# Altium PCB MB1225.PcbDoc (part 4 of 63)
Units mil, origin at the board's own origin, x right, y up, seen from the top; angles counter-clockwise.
Board outline 5000 x 3464.56 mil, 6 copper layers (TOP, L2_GND, L3_VCC, L4_SIG, L5_GND, BOTTOM), stack 62.2 mil thick; 452 components, 378 nets, 1968 pads, 949 vias.

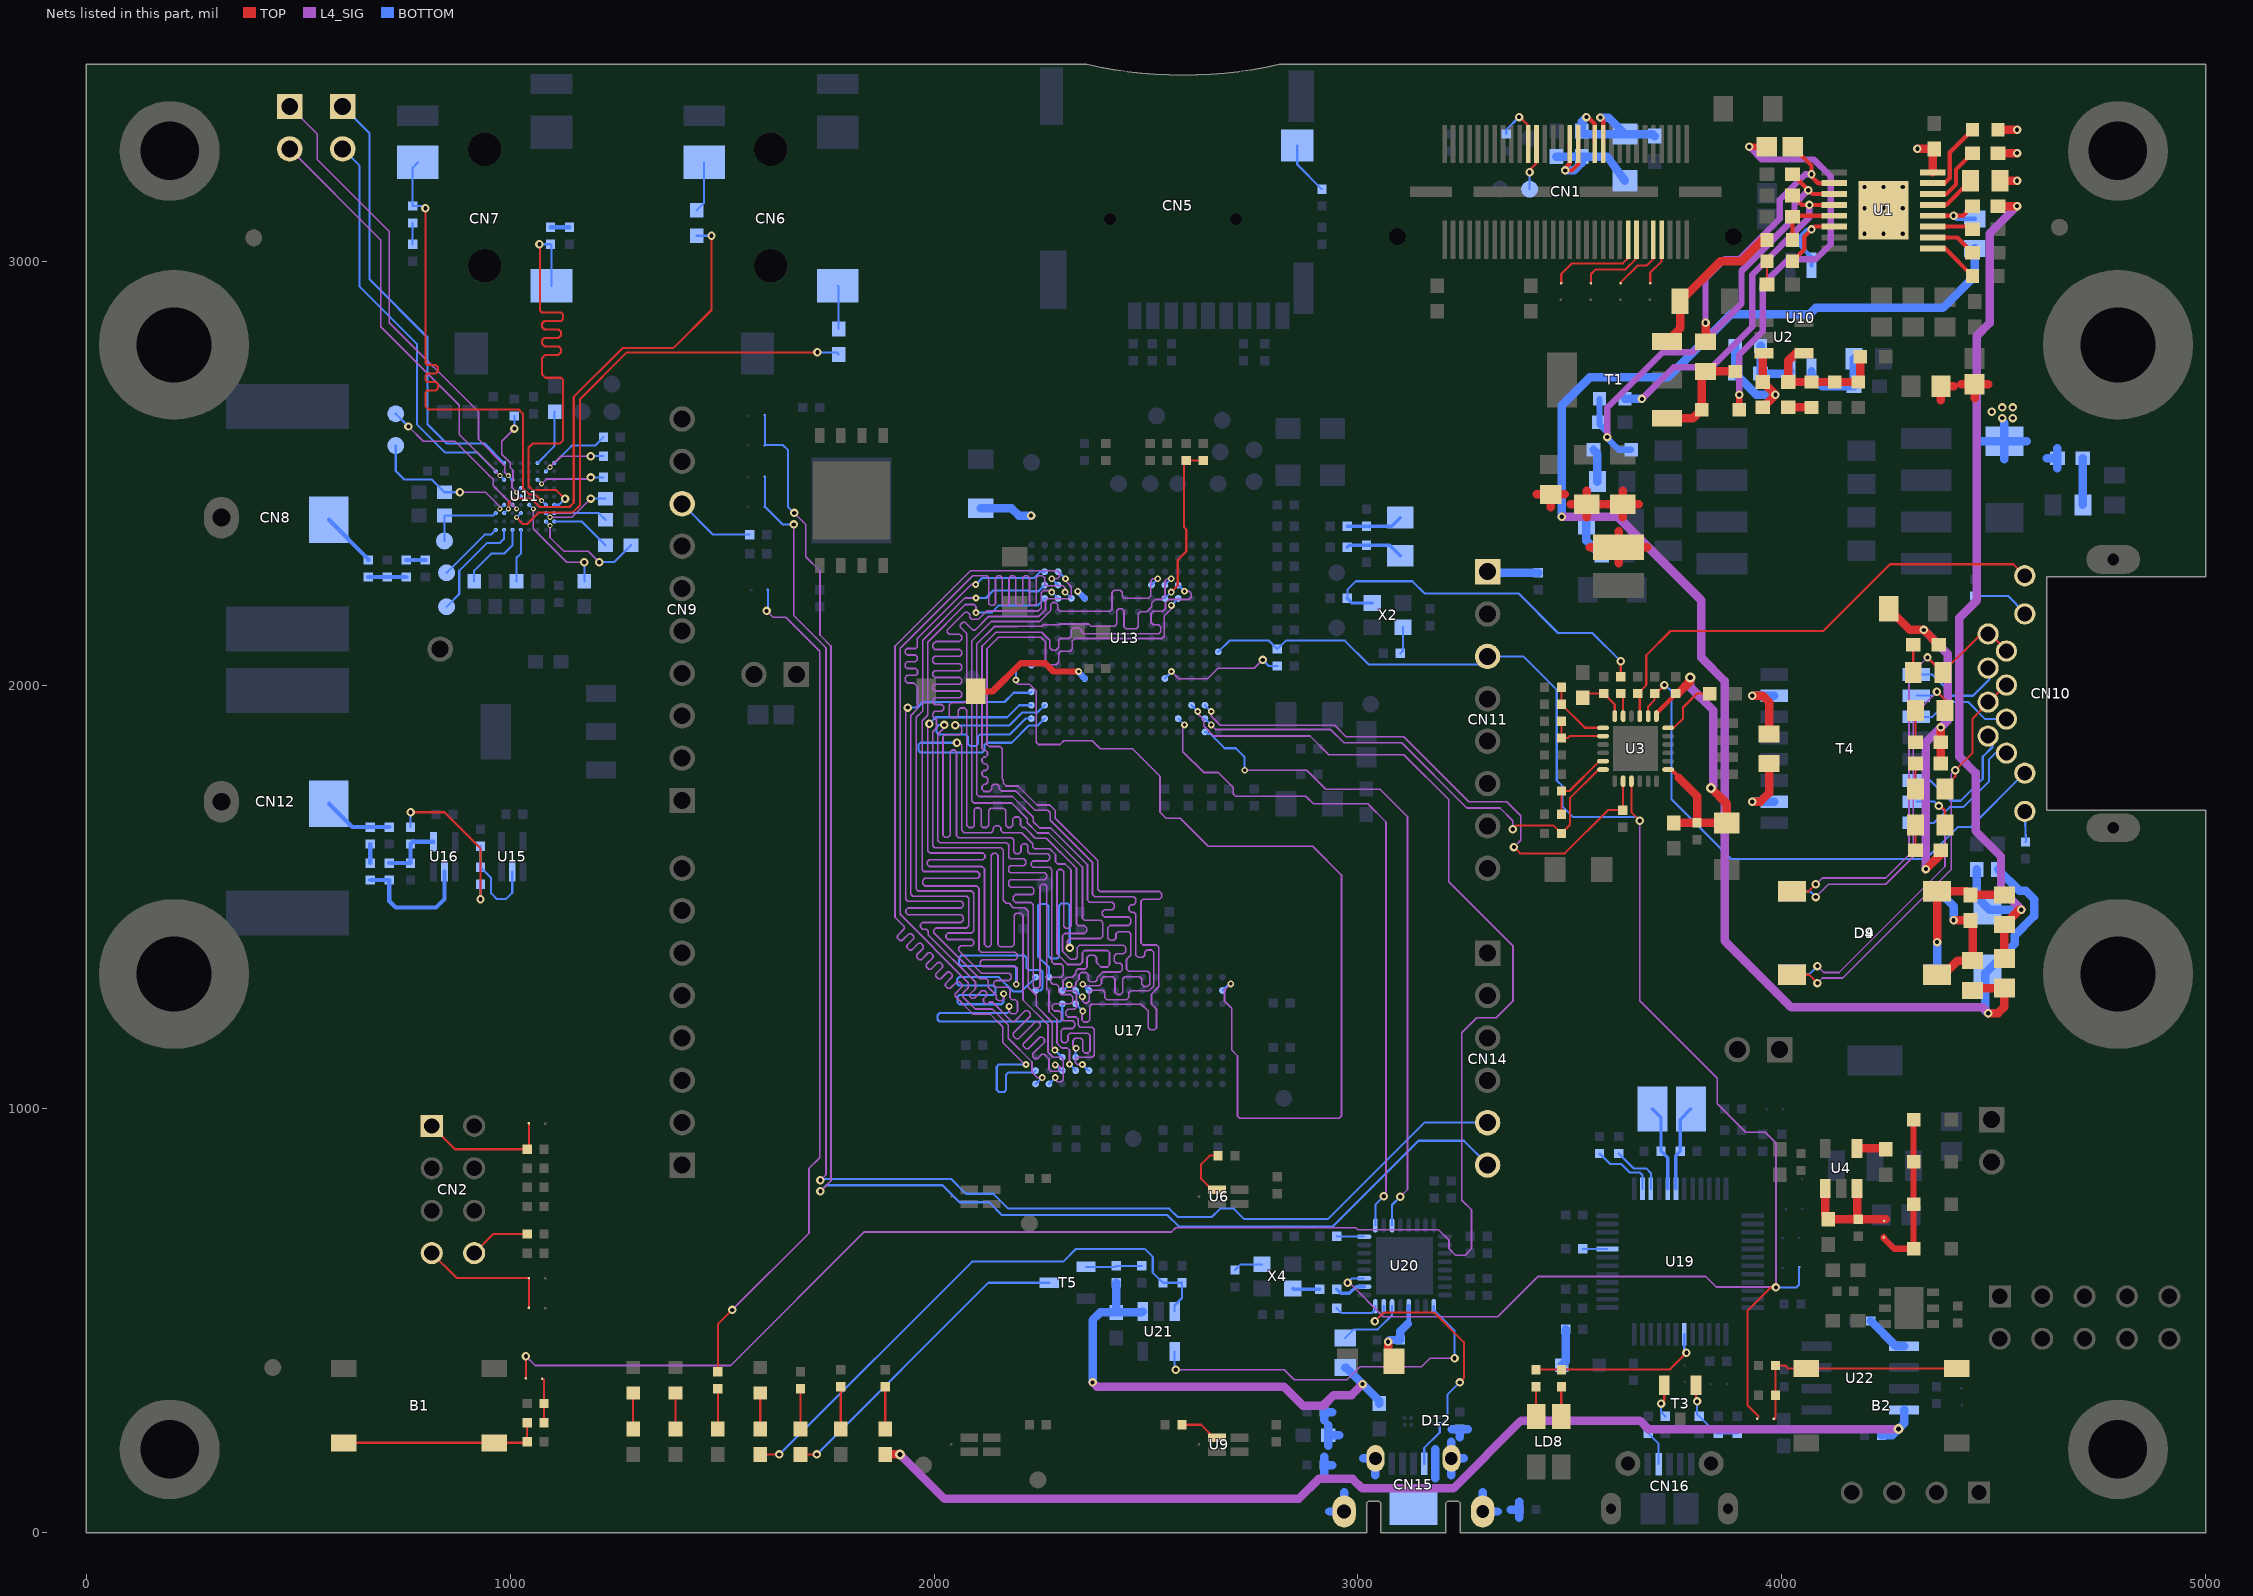
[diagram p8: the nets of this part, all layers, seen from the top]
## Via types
v1: diameter 20, hole 10, TOP to BOTTOM, 354 vias
v2: diameter 24, hole 12, TOP to BOTTOM, 349 vias
v3: diameter 16, hole 8, TOP to BOTTOM, 219 vias
v4: diameter 12, hole 6, TOP to BOTTOM, 27 vias

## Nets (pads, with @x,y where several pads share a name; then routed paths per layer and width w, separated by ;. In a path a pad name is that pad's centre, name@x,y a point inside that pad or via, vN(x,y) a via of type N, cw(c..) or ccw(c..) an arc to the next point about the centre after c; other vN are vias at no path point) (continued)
FMC_D15: U13.K15 U17.R2 | length 2329.2
  L4_SIG w4: v3(2193,2012) 2193,2007 2198,2002 2225,2002 2241,1986 2241,1865 2246,1860 2297,1860 2306,1869 2373,1869 2392,1850 2467.98,1850 2533,1784.98 2533,1700.02 2547.02,1686 2581,1686 2647,1620 2893,1620 2961,1552 2961,983 2956,978 2721,978 2716,983 2716,1125 2702,1139 2702,1238 2685,1255 2685,1280 v3(2700,1295)
  BOTTOM w5: v3(2193,2012) 2193,2035 2205.01,2047.01 U13.K15@2229.53,2047.01 ; U17.R2@2680.47,1279.49 2695.98,1295 v3(2700,1295)
FMC_D16: U13.P14 U17.E8 | length 2227.8
  L4_SIG w4: v1(2054,1864) 2060,1864 2065,1859 2065,1658 2071,1652 2135,1652 2140,1657 2140,1663 2145,1668 2153,1668 2158,1663 2158,1657 2163,1652 2207,1652 2233,1626 2233,1618 2237,1614 2273,1614 2286.5,1600.5 2286.5,1583.5 2292,1578 2309,1578 2323,1564 2323,1430.98 2318.02,1426 2310.98,1426 2306,1430.98 2306,1560.31 2301.31,1565 2294.69,1565 2290,1560.31 2290,1366 2315,1341 2345,1341 2350,1346 2350,1369 2355,1374 2409,1374 2414,1369 2414,1340 2409,1335 2394,1335 2383,1346 2383,1358.02 2378.02,1363 2366,1363 2361,1358 2361,1335 2356,1330 2339,1330 2334,1325 2334,1319 2326,1311 2314,1311 2304,1301 2304,1284 2309,1279 2331,1279 2336,1274 2336,1240 2331,1235 2316,1235 2311,1230 2311,1222 2316,1217 2335,1217 2340,1212 2340,1198 2345,1193 2373,1193 2378,1188 2378,1127 2373,1122 2338,1122 2333,1117 2333,1110 2338,1105 v3(2350,1105)
  BOTTOM w5: v1(2054,1864) 1968,1864 1963,1859 1963,1846 1968,1841 2114,1841 2119,1846 2119,1859 2124,1864 2183,1864 2224.1,1905.1 2245.1,1905.1 U13.P14@2261.02,1921.02 ; v3(2350,1105) 2364.49,1090.51 U17.E8@2365.51,1090.51
FMC_D17: U13.N14 U17.D7 | length 2223.5
  L4_SIG w4: v1(2050,1905) 2060,1905 2065,1900 2065,1888 2060,1883 2026,1883 2021,1878 2021,1645.98 2025.98,1641 2033.02,1641 2038,1645.98 2038,1842.61 2042.39,1847 2048.61,1847 2053,1842.61 2053,1645 2058,1640 2183,1640 2188,1635 2188,1607 2193,1602 2200,1602 2205,1607 2205,1621.31 2209.69,1626 2216,1626 2221,1621 2221,1607 2226,1602 2268.02,1602 2273,1597.02 2273,1589.98 2268.02,1585 2233.39,1585 2229,1580.61 2229,1574.39 2233.39,1570 2273,1570 2278,1565 2278,1347 2283,1342 2300,1342 2305,1337 2305,1316 2300,1311 2279.98,1311 2275,1306.02 2275,1298.98 2279.98,1294 2289,1294 2294,1289 2294,1276 2300,1270 2322,1270 2327,1265 2327,1253 2322,1248 2283.98,1248 2279,1243.02 2279,1235.98 2283.98,1231 2295,1231 2300,1226 2300,1213 2305,1208 2327,1208 2332,1203 2332,1195 2327,1190 2305,1190 2300,1185 2300,1161 2305,1156 2311,1156 2316,1161 2316,1174 2321,1179 2363,1179 2368,1174 2368,1137 2363,1132 2356,1132 2351,1137 2351,1162.31 2346.31,1167 2333,1167 2328,1162 2328,1148.01 2333,1143.01 v3(2335,1143.01)
  BOTTOM w5: v1(2050,1905) 2178,1905 2208.52,1935.52 2244.02,1935.52 U13.N14@2261.02,1952.52 ; U17.D7@2334.02,1122.01 2334.02,1142.03 v3(2335,1143.01)
FMC_D18: U13.P15 U17.D8 | length 2224.4
  L4_SIG w4: v1(2024,1906) 2024,1899 2009,1884 2009,1633 2014,1628 2171,1628 2176,1623 2176,1594 2180,1590 2211.31,1590 2216,1585.31 2216,1578.69 2211.31,1574 2180,1574 2176,1570 2176,1561 2180,1557 2261.31,1557 2266,1552.31 2266,1545.69 2261.31,1541 2180,1541 2176,1537 2176,1528 2181,1523 2231,1523 2235,1519 2235,1509 2232,1506 2192,1506 2187,1501 2187,1492 2192,1487 2229,1487 2234,1482 2234,1289.69 2238.69,1285 2245.31,1285 2250,1289.69 2250,1525.31 2254.69,1530 2261.31,1530 2266,1525.31 2266,1284 2271,1279 2271,1230 2290,1211 2290,1155 2301,1144 2314.41,1144 2319.41,1139 v3(2319.41,1105.61)
  BOTTOM w5: v1(2024,1906) 2011,1906 2006,1901 2006,1888 2011,1883 2075,1883 2080,1878 2080,1861 2085,1856 2098,1856 2103,1861 2103,1878 2108,1883 2178,1883 2216.02,1921.02 U13.P15@2229.53,1921.02 ; v3(2319.41,1105.61) 2334.02,1091 U17.D8@2334.02,1090.51
FMC_D19: U13.N15 U17.B9 | length 2255.1
  L4_SIG w4: v1(1989,1909) 1985,1905 1985,1609 1990,1604 2115.31,1604 2120,1599.31 2120,1592.69 2115.31,1588 1988.69,1588 1984,1583.31 1984,1576.69 1988.69,1572 2114,1572 2119,1567 2119,1388 2124,1383 2130,1383 2135,1388 2135,1598.31 2139.69,1603 2146.31,1603 2151,1598.31 2151,1388 2156,1383 2184,1383 2189,1388 2189,1457 2194,1462 2205,1462 2210,1457 2210,1257 2269,1198 2269,1134 2281,1122 2300,1122 2305,1117 2305,1069 2300,1064 2291,1064 2286,1069 v3(2286,1074)
  BOTTOM w5: v1(1989,1909) 2004,1924 2172.48,1924 2201,1952.52 U13.N15@2229.53,1952.52 ; U17.B9@2271.02,1059.02 v3(2286,1074)
FMC_D20: U13.M15 U17.C8 | length 2245.9
  L4_SIG w4: v1(1938,1947) 1933,1942 1933,1495 1938,1490 2064.31,1490 2069,1485.31 2069,1478.69 2064.31,1474 1938.69,1474 1934,1469.31 1934,1462.69 1938.69,1458 2064,1458 2069,1453 2069,1445 2064,1440 1972.69,1440 1968,1435.31 1968,1429 1973,1424 1981.5,1424 1986.5,1419 1986.5,1410.5 2098,1299 2098,1284.32 2084.82,1271.14 2084.82,1265.18 2089.02,1260.98 2094.98,1260.98 2112.63,1278.63 2119.37,1278.63 2124.13,1273.87 2124.13,1267.13 2116.48,1259.48 2116.48,1253.09 2121.02,1248.56 2127.42,1248.56 2131.43,1252.57 2137.41,1252.57 2183.99,1205.99 2188.99,1205.99 2214.46,1231.46 2221.54,1231.46 2226.96,1226.04 2226.96,1218.96 2187,1179 2187,1171.98 2193.38,1165.6 2199.04,1165.6 2239.4,1205.96 2246.04,1205.96 2250.72,1201.28 2250.72,1194.64 2210.36,1154.28 2210.36,1148.62 2216.75,1142.23 2222.41,1142.23 2249.27,1169.09 2255.91,1169.09 2260.59,1164.41 2260.59,1157.77 2233.16,1130.34 2233.16,1123.84 2237.75,1119.25 2244.25,1119.25 2254,1129 2260,1129 2271,1118 2271,1093.39 2275.39,1089 2292.22,1089 2297,1093.78 2297,1099 2292,1104 v3(2286,1104)
  BOTTOM w5: v1(1938,1947) 1961,1947 1974,1960 2166.04,1960 2188.04,1982 2227.51,1982 U13.M15@2229.53,1984.02 ; v3(2286,1104) 2299.49,1090.51 U17.C8@2302.52,1090.51
FMC_D21: U13.E12 U17.A9 | length 2242.8
  L4_SIG w4: v3(2255,1074) 2244,1074 2231,1087 2231,1111 2175,1167 2175,1198 2138,1235 2136.98,1236 2097,1236 2068,1265 2068,1273 2081,1286 2081,1298 1920,1459 1920,2087 2091,2258 2124.01,2258 2129.01,2253 2129.01,2192 2133.01,2188 2141.01,2188 2145.01,2192 2145.01,2253 2150.01,2258 2156.01,2258 2161.01,2253 2161.01,2192 2165.01,2188 2173.01,2188 2177.01,2192 2177.01,2253 2182.01,2258 2188.01,2258 2193.01,2253 2193.01,2192 2197.01,2188 2205.01,2188 2209.01,2192 2209.01,2253 2214.01,2258 2220.01,2258 2225.01,2253 2225.01,2192 2229.01,2188 2237.01,2188 2241.01,2192 2241.01,2253 2246.01,2258 2256,2258 2261,2253 2261,2239 2266,2234 2304.17,2234 2309.17,2229 v3(2309.17,2219.34)
  BOTTOM w5: U17.A9@2239.53,1059.02 2254.51,1074 v3(2255,1074) ; v3(2309.17,2219.34) U13.E12@2324.02,2204.49
FMC_D22: U13.E13 U17.C7 | length 2228.9
  L4_SIG w4: v3(2277.67,2219.34) 2274.01,2223 2258,2223 2253,2218 2253,2182 2246,2175 2125,2175 2105,2155 2089,2155 2084,2160 2084,2167 2079,2172 2073,2172 2031,2130 2031,2125 2036,2120 2060.02,2120 2065,2115.02 2065,2107.98 2060.02,2103 2004,2103 1997,2096 1997,2088.98 2002,2083.98 2060.31,2083.98 2065,2079.29 2065,2072.67 2060.31,2067.98 2002,2067.98 1997,2062.98 1997,2055 2002,2050 2060.31,2050 2065,2045.31 2065,2038.69 2060.31,2034 2002,2034 1997,2029 1997,2023 2002,2018 2060.31,2018 2065,2013.31 2065,2006.69 2060.31,2002 2002,2002 1997,1997 1997,1991 2002,1986 2060.31,1986 2065,1981.31 2065,1974.69 2060.31,1970 2002,1970 1997,1965 1997,1959 2002,1954 2018.31,1954 2023,1949.31 2023,1942.69 2018.31,1938 2002,1938 1997,1933 1997,1926 2006,1917 2006,1899 1997,1890 1997,1621 2002,1616 2158,1616 2163,1611 2163,1492 2170,1485 2177,1485 2187,1475 2213.85,1475 2222,1466.85 2222,1287 2241,1268 2241,1243 2279,1205 2279,1145 v3(2285,1139)
  BOTTOM w4: v3(2277.67,2219.34) U13.E13@2292.52,2204.49
  BOTTOM w5: v3(2285,1139) 2301.99,1122.01 U17.C7@2302.52,1122.01
FMC_D23: U13.D13 U17.A8 | length 2238.4
  L4_SIG w4: v3(2217,1105) 2214,1105 2162.04,1156.96 2162.04,1193.96 2132,1224 2092,1224 2049.74,1266.26 2049.74,1271.92 2066.08,1288.26 2066.08,1293.92 2059.7,1300.3 2054.04,1300.3 2038.2,1284.46 2032.54,1284.46 2026.88,1290.12 2026.88,1295.78 2042.72,1311.62 2042.72,1317.28 2037.06,1322.94 2031.4,1322.94 2015.56,1307.1 2009.9,1307.1 2004.24,1312.76 2004.24,1318.42 2020.08,1334.26 2020.08,1339.92 2014.42,1345.58 2008.76,1345.58 1992.92,1329.74 1987.26,1329.74 1981.6,1335.4 1981.6,1341.06 1997.44,1356.9 1997.44,1362.56 1991.78,1368.22 1986.12,1368.22 1970.28,1352.38 1964.62,1352.38 1958.96,1358.04 1958.96,1363.7 1974.8,1379.54 1974.8,1385.2 1969.14,1390.86 1963.48,1390.86 1947.64,1375.02 1941.98,1375.02 1936.32,1380.68 1936.32,1386.34 1952.16,1402.18 1952.16,1407.84 1946.5,1413.5 1940.84,1413.5 1925,1397.66 1919.34,1397.66 1913.68,1403.32 1913.68,1408.98 1929.52,1424.82 1929.52,1430.48 1908,1452 1908,2092 2086,2270 2291,2270 2296,2265 2296,2255.83 2291,2250.83 v3(2277.67,2250.83)
  BOTTOM w5: v3(2217,1105) 2153,1105 2148,1100 2148,1045 2153,1040 2165,1040 2170,1045 2170,1081 2175,1086 2235.02,1086 U17.A8@2239.53,1090.51 ; v3(2277.67,2250.83) U13.D13@2292.52,2235.98
FMC_D24: U13.E14 U17.A2 | length 2269.2
  L4_SIG w4: v3(2099,2171) 2099,2186 2095,2190 2074,2190 1985,2101 1985,1929.05 1972,1916.05 1972,1564 1976,1560 2103,1560 2107,1556 2107,1548 2103,1544 1978,1544 1973,1539 1973,1531 1978,1526 2101,1526 2106,1521 2106,1375 2111,1370 2191,1370 2196,1365 2196,1356 2192,1352 2113.69,1352 2109,1347.31 2109,1340.69 2113.69,1336 2192,1336 2196,1332 2196,1296 v3(2194,1294)
  BOTTOM w5: v3(2099,2171) 2136,2171 2153,2188 2244.53,2188 U13.E14@2261.02,2204.49 ; v3(2194,1294) 2194,1332 2189,1337 2064,1337 2059,1342 2059,1357 2064,1362 2213,1362 2218,1357 2218,1333 2223,1328 2251,1328 2256,1323 2256,1284.49 2251,1279.49 U17.A2@2239.53,1279.49
FMC_D25: U13.D14 U17.C3 | length 2242.8
  L4_SIG w4: v3(2099,2205.5) 2072.5,2205.5 1973,2106 1973,1939 1958,1924 1958,1519 1963,1514 2089,1514 2094,1509 2094,1420 2089,1415 2032.39,1415 2028,1410.61 2028,1404.39 2032.39,1400 2089.61,1400 2094,1395.61 2094,1389.39 2089.61,1385 2063,1385 2058,1380 2058,1374 2111.83,1320.17 2177,1320.17 2182,1315.17 2182,1308 2177,1303 2145.69,1303 2141,1298.31 2141,1291.69 2145.69,1287 2174,1287 2179,1282 2179,1263 2184,1258 2192,1258 2197,1253 2197,1230 2192,1225 2182,1225 2177,1230 v3(2177,1242)
  BOTTOM w5: v3(2099,2205.5) 2122.5,2205.5 2140,2223 2222,2223 2223.52,2221.48 2246.52,2221.48 U13.D14@2261.02,2235.98 ; v3(2177,1242) 2177,1230.69 2172.31,1226 2013,1226 2008,1221 2008,1211 2013,1206 2297.52,1206 2302.52,1211 U17.C3@2302.52,1247.99
FMC_D26: U13.C14 U17.A1 | length 2247.2
  L4_SIG w4: v3(2098.61,2237.39) 2087.39,2237.39 1960,2110 1960,2090 1956.5,2086.5 1936.54,2086.5 1932,2081.96 1932,2075.54 1936.54,2071 1956,2071 1960,2067 1960,2059 1956,2055 1936,2055 1932,2051 1932,2043 1936,2039 1957,2039 1961,2035 1961,2027 1957,2023 1937,2023 1932,2018 1932,2010 1937,2005 1952,2005 1961,1996 1961,1944 1945,1928 1945,1507 1950,1502 2077,1502 2082,1497 2082,1432 2077,1427 2003.69,1427 1999,1422.31 1999,1416 2107.51,1307.49 2123.51,1307.49 2128,1303 2128,1287 2147,1268 2147,1259.98 2151.98,1255 2160,1255 2165,1260 2165,1271 v3(2164,1272)
  BOTTOM w5: v3(2098.61,2237.39) 2114.22,2253 2223.5,2253 2236.02,2252.98 2250.52,2267.48 U13.C14@2261.02,2267.48 ; v3(2164,1272) 2164,1252 2159,1247 2060,1247 2055,1252 2055,1264 2060,1269 2140,1269 2145,1274 2145,1286 2140,1291 2059,1291 2054,1296 2054,1305.98 2059,1310.98 2153.02,1310.98 2187,1277 2205.55,1277 U17.A1@2239.53,1310.98
FMC_D27: U13.C13 U17.C2 | length 2224.9
  L4_SIG w4: v3(2310,2251) 2310,2246 2324,2232 2324,2212 2316,2204 2268,2204 2263,2199 2263,2178 2247,2162 2129,2162 2097,2130 2091.34,2130 2073,2148.34 2067.34,2148.34 2061.68,2142.68 2061.68,2137.02 2077,2121.7 2077,1963 2072,1958 2041,1958 2036,1953 2036,1928 2041,1923 2052,1923 2057,1928 2057,1941 2062,1946 2072,1946 2077,1941 2077,1669 2082,1664 2091,1664 2095,1668 2095,1706 2099,1710 2107,1710 2111,1706 2111,1668 2115,1664 2124,1664 2129,1669 2129,1704.68 2134,1709.68 2164,1709.68 2169,1704.68 2169,1669 2174,1664 2181,1664 2186,1669 2186,1684 2191,1689 2199,1689 2204,1684 2204,1669 2209,1664 2214,1664 2239,1639 2265,1639 2336,1568 2336,1437 2341,1432 2355,1432 2360,1427 2360,1419 2355,1414 2308,1414 2303,1409 2303,1372 2322,1353 2333,1353 2338,1358 2338,1381 2343,1386 2447,1386 2452,1381 2452,1371 2447,1366 2430,1366 2425,1361 2425,1349 2430,1344 2439,1344 2444,1339 2444,1328 2439,1323 2398,1323 2385,1310 2385,1305 2380,1300 2368,1300 2364,1304 2364,1317 2359,1322 2347,1322 2342,1317 2342,1306 2335,1299 2335,1291.81 2330.19,1287 2323.4,1287 2318.59,1291.81 v3(2318.59,1293.02)
  BOTTOM w5: U13.C13@2292.52,2267.48 2293.62,2267.48 2310,2251.1 v3(2310,2251) ; U17.C2@2302.52,1279.49 2305.06,1279.49 v3(2318.59,1293.02)
FMC_D28: U13.D6 U17.B1 | length 2244.5
  L4_SIG w4: v1(2320,1380) 2315,1385 2315,1397 2320,1402 2393,1402 2398,1407 2398,1440 2393,1445 2355,1445 2350,1450 2350,1571 2270,1651 2244,1651 2220,1675 2220,1685 2183,1722 2094,1722 2089,1727 2089,2104 2135,2150 2249,2150 2275,2176 2275,2190 2280,2195 2287,2195 2292,2190 2292,2178.84 2297,2173.84 2415,2173.84 2420,2178.84 2420,2219 2425,2224 2439,2224 2444,2219 2444,2210 2449,2205 2506,2205 2511,2210 2511,2245.83 2516,2250.83 v3(2527.84,2250.83)
  BOTTOM w5: U17.B1@2271.02,1310.98 2271.02,1333.98 2245,1360 2245,1479 2250,1484 2265,1484 2270,1479 2270,1360 2275,1355 2290,1355 2295,1360 2295,1480 2300,1485 2315,1485 2320,1480 v1(2320,1380) ; U13.D6@2512.99,2235.98 v3(2527.84,2250.83)
FMC_D29: U13.D4 U17.D2 | length 2229.2
  L4_SIG w4: v3(2350,1265) 2350,1255 2355,1250 2361,1250 2366,1255 2366,1275.61 2370.39,1280 2397.88,1280 2402.88,1275 2402.88,1263 2407.88,1258 2454,1258 2459,1263 2459,1274 2464,1279 2507,1279 2518,1290 2518,1370 2513,1375 2502,1375 2497,1370 2497,1363 2492,1358 2481,1358 2476,1363 2476,1459 2471,1464 2465,1464 2460,1469 2460,1477 2465,1482 2471,1482 2476,1487 2476,1496 2471,1501 2379,1501 2374,1506 2374,1581 2274,1681 2274,1699 2268,1705 2238,1705 2193,1750 2159,1750 2154,1755 2154,1761 2149,1766 2141,1766 2136,1761 2136,1754 2131,1749 2118,1749 2113,1754 2113,1761.31 2117.69,1766 2122,1766 2127,1771 2127,1779 2122,1784 2117.21,1784 2113,1788.21 2113,1794.17 2117.21,1798.38 2122.5,1798.38 2126.5,1802.38 2126.5,1810.38 2122.5,1814.38 2117.69,1814.38 2113,1819.07 2113,1825.69 2117.69,1830.38 2121.31,1830.38 2126,1835.07 2126,1841.69 2121.31,1846.38 2117,1846.38 2113,1850.38 2113,2092 2146,2125 2254,2125 2273,2106 2273,2088 2279,2082 2287,2082 2294,2089 2294,2107 2297,2110 2319,2110 2324,2115 2324,2130 2329,2135 2343,2135 2348,2130 2348,2126 2353,2121 2530,2121 2535,2126 2535,2137 2530,2142 2517,2142 2512,2147 2512,2168.84 2517,2173.84 2539.84,2173.84 2546,2180 2546,2193.8 2554.2,2202 2602,2202 2607,2207 2607,2216.13 2602,2221.13 v3(2590.83,2221.13)
  BOTTOM w5: U17.D2@2334.02,1279.49 2348.51,1265 v3(2350,1265) ; U13.D4@2575.98,2235.98 v3(2590.83,2221.13)
FMC_D30: U13.E4 U17.D3 | length 2236.2
  L4_SIG w4: v3(2351,1231) 2349,1229 2349,1210 2354,1205 2362,1205 2367,1210 2367,1242 2372,1247 2489,1247 2505,1231 2505,1192 2510,1187 2520,1187 2525,1192 2525,1235 2513,1247 2513,1271 2530,1288 2530,1382 2525,1387 2493,1387 2488,1392 2488,1490 2493,1495 2532,1495 2537,1500 2537,1508 2532,1513 2391,1513 2386,1518 2386,1586 2286,1686 2286,1704 2273,1717 2243,1717 2197.95,1762.05 2169.93,1762.05 2163,1768.98 2163,1776.37 2161,1778.37 2161,1850 2156,1855 2130,1855 2125,1860 2125,2086 2152,2113 2252,2113 2263,2102 2263,2054 2269,2048 2288,2048 2294,2054 2294,2075 2299,2080 2321,2080 2326,2085 2326,2104 2332,2110 2538,2110 2543,2115 2543,2163 2560,2180 v3(2560,2188)
  BOTTOM w5: U17.D3@2334.02,1247.99 v3(2351,1231) ; v3(2560,2188) 2560,2188.51 U13.E4@2575.98,2204.49
FMC_D31: U13.D5 U17.E2 | length 2253.8
  L4_SIG w4: v3(2350.66,1294.34) 2354,1291 2390,1291 2395,1296 2395,1307 2400,1312 2422,1312 2427,1307 2427,1275 2432,1270 2440,1270 2445,1275 2445,1307 2450,1312 2485,1312 2490,1307 2490,1294 2495,1289 2504,1289 2509,1294 2509,1320 2504,1325 2459,1325 2454,1330 2454,1353 2464,1363 2464,1413 2459,1418 2434,1418 2429,1413 2429,1403 2424,1398 2415,1398 2410,1403 2410,1428 2415,1433 2459,1433 2464,1438 2464,1448 2459,1453 2402,1453 2397,1458 2397,1465 2402,1470 2420,1470 2425,1475 2425,1483 2420,1488 2367,1488 2362,1493 2362,1576 2275,1663 2249,1663 2234,1678 2234,1688 2185,1737 2106,1737 2101,1742 2101,2097 2142,2138 2195.98,2138 2196.98,2139 2255,2139 2258,2142 2294,2142 2296,2144 2365.15,2144 2370.15,2139 2426,2139 2431,2144 2431,2175.02 2435.98,2180 2443.02,2180 2448,2175.02 2448,2138 2453,2133 2477,2133 2482,2138 2482,2168 2487,2173 2502,2173 2513.84,2184.84 2513.84,2193.64 2522.04,2201.84 2536.84,2201.84 2545,2210 2545,2245.83 2550,2250.83 v3(2559.34,2250.83)
  BOTTOM w5: v3(2350.66,1294.34) U17.E2@2365.51,1279.49 ; U13.D5@2544.49,2235.98 v3(2559.34,2250.83)
LED_G_A: CN10.12 R28.2 U3.3 | length 1147
  TOP w5: U3.3@3664.84,1926.77 3664.84,1975.16 R28.2@3660,1980 3680,2000 3680,2070 3737.5,2127.5 4097.5,2127.5 4255,2285 4546.14,2285 CN10.12@4573.19,2257.95
LED_G_K: CN10.11 R105.2 | length 136.5
  BOTTOM w5: R105.2@4455,2210 4533.77,2210 4553.77,2190 CN10.11@4573.19,2167.8
LED_STLINK: R60.1 R61.1 U19.30 | length 417.4
  TOP w5: R60.1@3420,385 R61.1@3480,385 3735,385 v1(3775,425)
  BOTTOM w5: U19.30@3769.84,468.74 3769.84,430.16 v1(3775,425)
LED_Y_A: CN10.10 R29.2 U3.2 | length 1344.1
  TOP w5: U3.2@3684.53,1926.77 3684.53,1949.53 3700,1965 R29.2@3700,1980 3703,1980 v1(3723,2000)
  BOTTOM w5: v1(3723,2000) 3725,2000 3740,1985 3740,1730 3880,1590 4340,1590 4415,1665 4445,1665 4572.2,1792.2 CN10.10@4573.19,1792.2
LED_Y_K: CN10.9 R113.2 | length 72.5
  BOTTOM w5: CN10.9@4573.19,1702.05 4575.97,1630.97 R113.2@4575,1630
LRCLK: CN1.37 TP3.1 | length 113.2
  TOP w5: v1(3405,3210) 3405,3215 3421.09,3231.09 CN1.37@3421.09,3276.53
  BOTTOM w5: TP3.1@3405,3170 v1(3405,3210)
MIC_CLK: TP105.1 U11.C6 | length 400.8
  L4_SIG w3.5: 950,2495 960,2485 960,2470 1014.44,2415.56 v4(1015.22,2415.56)
  L4_SIG w4: v1(760,2610) 795,2575 870,2575 950,2495
  BOTTOM w3.5: U11.C6@1005.47,2425.31 v4(1015.22,2415.56)
  BOTTOM w5: TP105.1@730,2640 v1(760,2610)
MIC_DATA1: TP106.1 U11.B9 | length 255.1
  BOTTOM w5: TP106.1@850,2185 880,2215 880,2270 945,2335 975,2335 985.79,2345.79 U11.B9@985.79,2366.26
MIC_DATA2: TP107.1 U11.A9 | length 158
  BOTTOM w5: TP107.1@850,2265 940,2355 954.84,2355 U11.A9@966.1,2366.26
MIC_VDD1: C79.2 TP108.1 U11.A7 | length 183.4
  BOTTOM w5: TP108.1@845,2340 C79.2@845,2400 960.47,2400 U11.A7@966.1,2405.63
MIC_VDD2: C73.2 TP109.1 U11.B6 | length 360.2
  L4_SIG w4: v1(881.59,2455) 941.88,2455 975.94,2420.94 v4(975.94,2415.46)
  BOTTOM w3.5: v4(975.94,2415.46) U11.B6@985.79,2425.31
  BOTTOM w5: TP109.1@730,2565 730,2505 750,2485 815,2485 C73.2@845,2455 v1(881.59,2455)
NETB1_2: B1.2 B1.3 R68.2 R70.2 | length 478.2
  TOP w5: B1.3@607.83,212.5 B1.2@962.17,212.5 1037.5,212.5 R70.2@1040,215 R68.2@1040,260
NETB2_1: B2.1 B2.4 C53.2 R67.1 SB10.2 | length 555.3
  TOP w5: 3985,270 R67.1@3985,325 C53.2@3985,395 4007.5,395 4015,387.5 B2.4@4057.83,387.5 B2.1@4412.17,387.5
NETC4_1: C4.1 C5.1 C8.1 C40.1 C122.1 D10.1 R1.1 R3.1 R48.2 U1.8 U1.17 | length 2365.9
  TOP w20: v1(4320,3265) C4.1@4360,3265 4356.14,3261.14 U1.8@4356.14,3209.57 ; C8.1@4510,3130 v1(4555,3130) ; C5.1@4510,3255 v1(4555,3255) ; R1.1@4510,3310 v1(4555,3310) ; R3.1@4515,3190 v1(4555,3190) ; C40.1@4525,1355 R48.2@4525,1435 4560,1470 v1(4565,1470)
  L4_SIG w20: v1(4555,3130) 4490,3065 4490,2854 4460,2824 4460,2200 4419,2159 4419,1831 4457,1793 4457,1656 4517,1596 4517,1518 v1(4565,1470)
  BOTTOM w20: C122.1@4460,1565 4460,1499.8 D10.1@4485,1474.8 4489.8,1470 v1(4565,1470)
  other v1: 4195,3065 4240,3065 4285,3065 4195,3125 4240,3125 4285,3125 4195,3175 4240,3175 4285,3175
NETC5_2: C5.2 U1.6 | length 154.4
  TOP w10: U1.6@4356.14,3158.39 4388.39,3158.39 4411.14,3181.14 4411.14,3216.14 C5.2@4450,3255
NETC6_2: C6.2 C24.2 D3.2 R25.2 U1.11 | length 1106.7
  TOP w10: C6.2@4025,3205 v1(4062.5,3167.5) 4071.61,3158.39 U1.11@4123.86,3158.39
  L4_SIG w15: v1(3588,2585) 3588,2654 3719,2785 3790,2785 3905,2900 3905,2977 4030,3102 4030,3135 v1(4062.5,3167.5)
  BOTTOM w15: R25.2@3570,2675 C24.2@3570,2620 3570,2615 3588,2597 v1(3588,2585) 3588,2582 3615,2555 D3.2@3644.29,2555
NETC7_2: C7.2 R25.1 U1.12 | length 822.2
  TOP w10: C7.2@4025,3155 4047.2,3132.8 v1(4065,3132.8) U1.12@4123.86,3132.8
  L4_SIG w15: v1(3670,2675) 3744.99,2749.99 3834.99,2749.99 3930,2845 3930,2968 4065,3103 v1(4065,3132.8)
  BOTTOM w20: R25.1@3630,2675 v1(3670,2675)
NETC8_2: C8.2 R75.1 U1.4 | length 156.3
  TOP w10: U1.4@4356.14,3107.2 v1(4405,3107.2) 4427.2,3107.2 C8.2@4450,3130
  BOTTOM w10: v1(4405,3107.2) 4412.2,3100 R75.1@4455,3100
NETC9_2: C9.2 R4.1 U1.13 | length 154.8
  TOP w10: R4.1@4025,3050 C9.2@4025,3105 4027.2,3107.2 U1.13@4123.86,3107.2
NETC10_1: C10.1 U1.3 | length 96.6
  TOP w10: U1.3@4356.14,3081.61 4443.39,3081.61 C10.1@4450,3075
NETC11_1: C11.1 U1.2 | length 108.8
  TOP w10: U1.2@4356.14,3056.02 4413.98,3056.02 C11.1@4450,3020
NETC12_2: C12.2 R5.1 | length 55
  TOP w5: C12.2@3965,2945 R5.1@3965,3000
NETC17_1: C17.1 C19.1 C200.2 R85.2 U2.3 | length 334.3
  TOP w20: C19.1@3955,2655 v1(3985,2685) C17.1@3955,2715 3955,2779.84 U2.3@3957.76,2782.6
  BOTTOM w20: R85.2@3890,2800 C200.2@3890,2735 3940,2685 v1(3985,2685)
NETC17_2: C17.2 R11.1 R13.2 R14.2 R15.2 U2.4 | length 321.6
  TOP w20: U2.4@4052.24,2782.6 4032.6,2782.6 4015,2765 C17.2@4015,2715 R13.2@4070,2715 R14.2@4125,2715 R15.2@4180,2715 4185,2720 R11.1@4185,2775
NETC18_2: C18.2 C21.2 D2.2 R16.1 | length 424.7
  TOP w20: 4375,2671.98 C18.2@4375,2705 4405.52,2705 ; 4423.48,2709.49 R16.1@4455,2709.49 ; 4455,2676.97 R16.1@4455,2709.49 ; 4486.52,2709.49 R16.1@4455,2709.49
  BOTTOM w20: 4471.98,2575.55 D2.2@4525,2575.55 ; 4525,2532.53 D2.2@4525,2575.55 ; 4525,2618.57 D2.2@4525,2575.55 ; 4578.02,2575.55 D2.2@4525,2575.55 ; 4624.48,2535 C21.2@4650,2535 ; 4650,2510.98 C21.2@4650,2535 ; 4650,2559.02 C21.2@4650,2535
  other v1: 4520,2630 4545,2630 4495,2645 4520,2655 4545,2655
NETC19_2: C19.2 R13.1 | length 55
  TOP w20: C19.2@4015,2655 R13.1@4070,2655
NETC21_1: C21.1 R22.2 | length 110
  BOTTOM w20: R22.2@4710,2425 C21.1@4710,2535
NETC22_1: C22.1 R23.1 | length 94.9
  BOTTOM w20: R23.1@3539,2385 3539,2341 C22.1@3575,2305
NETC26_1: C26.1 C32.1 C34.1 C37.1 C89.2 | length 905
  TOP w20: C89.2@4252,2180 4302,2130 v1(4335,2130) C26.1@4370,2095 ; v1(4340,1566) 4375,1601 C37.1@4375,1610 ; C34.1@4375,1815 C32.1@4375,1865 v1(4375,1900)
  L4_SIG w20: v1(4335,2130) 4391,2074 4391,1916 v1(4375,1900) 4340,1865 v1(4340,1566)
NETC26_2: C26.2 R26.1 | length 65
  TOP w5: R26.1@4310,2030 C26.2@4310,2095
NETC28_2: C28.2 C29.2 U3.6 | length 118.1
  TOP w5: C28.2@3530,1970 3540,1980 C29.2@3580,1980 3605.79,1954.21 U3.6@3605.79,1926.77
NETC30_2: C30.2 C35.2 C36.1 L2.1 U3.1 U3.19 | length 793.4
  TOP w10: U3.1@3704.21,1926.77 3704.21,1933.71 3750,1979.5 C30.2@3750,1980 ; U3.19@3731.77,1800.79 3739.21,1800.79 3757,1783 3757,1781
  TOP w20: L2.1@3745,1675 C35.2@3800,1675 ; C30.2@3750,1980 3755,1980 3784,2009 v2(3784,2018) ; 3757,1781 3800,1738 C35.2@3800,1675 ; v2(3833,1757) 3870,1720 C36.1@3870,1675 C35.2@3800,1675
  L4_SIG w20: v2(3784,2018) 3784,1995 3838,1941 3838,1762 v2(3833,1757)
NETC31_2: C31.2 U13.L11 | length 301.1
  TOP w15: C31.2@2098,1985 2138,1985 2204.5,2051.5 2262.24,2051.5 2281.74,2032 v3(2341,2032)
  BOTTOM w15: v3(2341,2032) 2341,2030.02 U13.L11@2355.51,2015.51
NETC32_2: C32.2 R33.1 | length 75
  TOP w5: C32.2@4315,1865 R33.1@4315,1940
NETC34_2: C34.2 R42.1 | length 60
  TOP w5: R42.1@4315,1755 C34.2@4315,1815
NETC37_2: C37.2 R46.1 | length 60
  TOP w5: C37.2@4315,1610 R46.1@4315,1670
NETC39_1: C39.1 D4.2 D9.2 R48.1 | length 359.1
  TOP w20: v1(4366.26,1393.74) D4.2@4366.26,1513.43 4436.57,1513.43 C39.1@4445,1505 R48.1@4525,1505
  BOTTOM w20: D9.2@4366.26,1316.57 v1(4366.26,1393.74)
NETC39_2: C39.2 D4.1 D9.1 R49.1 | length 323.8
  TOP w20: D4.1@4366.26,1316.57 4376.57,1311.57 4415,1350 R49.1@4450,1350 4450,1440 C39.2@4445,1445 v1(4405,1445)
  BOTTOM w20: D9.1@4366.26,1513.43 4375,1508.43 4405,1478.43 v1(4405,1445)
NETC40_2: C40.2 C70.2 C75.2 C81.2 C121.2 D10.2 L5.2 R49.2 R75.2 | length 4541.2
  TOP w20: 3421.98,2450 C81.2@3455,2450 ; 3455,2419.48 C81.2@3455,2450 ; 3488.02,2450 C81.2@3455,2450 ; 3501.98,2427 C70.2@3540,2427 ; 3540,2395.98 C70.2@3540,2427 ; 3540,2458.02 C70.2@3540,2427 ; 3546.98,2325.08 L5.2@3615,2325.08 ; 3578.02,2427 C70.2@3540,2427 ; 3586.98,2427 C75.2@3625,2427 ; 3615,2287.06 L5.2@3615,2325.08 ; 3615,2363.1 L5.2@3615,2325.08 ; 3625,2395.98 C75.2@3625,2427 ; 3625,2458.02 C75.2@3625,2427 ; 3663.02,2427 C75.2@3625,2427 ; 3683.02,2325.08 L5.2@3615,2325.08 ; R49.2@4450,1280 4455,1285 C40.2@4525,1285 4525,1241 4510,1226 v1(4487,1226)
  L4_SIG w20: v1(3481,2397) 3613,2397 3810,2200 3810,2065 3865,2010 3865,1397 4022,1240 4473,1240 v1(4487,1226)
  BOTTOM w20: v1(3481,2397) 3481,2660 3547,2726 3731,2726 3880,2875 4065,2875 4080,2890 4380,2890 4455,2965 R75.2@4455,3030 ; v1(4487,1226) 4480,1233 4480,1320.2 D10.2@4485,1325.2 4549.8,1390 4549.8,1409.8 4595,1455 4595,1495 4575,1515 4560,1515 C121.2@4510,1565
NETC43_2: C43.2 U4.4 | length 68.5
  TOP w20: U4.4@4177.4,907.24 4242.76,907.24 C43.2@4245,905
NETC46_2: C46.2 C47.2 SB7.2 U4.1 U4.3 | length 286.7
  TOP w20: U4.1@4102.6,812.76 4102.6,747.4 C47.2@4110,740 C46.2@4180,740 ; U4.3@4177.4,812.76 4177.4,747.4 4182.4,742.4 C46.2@4180,740 ; 4245,740 C46.2@4180,740
NETC52_2: C52.2 C149.2 U20.20 | length 170.4
  TOP w20: v1(3071,451) 3071,419 C52.2@3085,405
  BOTTOM w10: 3117,493 3119.84,495.84 U20.20@3119.84,534.72
  BOTTOM w20: v1(3071,451) 3075,455 C149.2@3100,455 3100,476 3117,493
NETC54_2: C54.2 R68.1 SB9.2 | length 102.4
  TOP w5: 1079,362 1080,361 C54.2@1080,305 R68.1@1080,260
NETC57_1: C57.1 CN7.4 U11.G6 | length 1185
  TOP w5: v1(800,3125) 800,2759.98 805,2754.98 824.14,2754.98 830,2749.12 830,2740.84 824.14,2734.98 805,2734.98 800,2729.98 800,2719.98 805,2714.98 824.14,2714.98 830,2709.12 830,2700.84 824.14,2694.98 805,2694.98 800,2689.98 800,2658 808,2650 1020,2650 1030,2640 1030,2465 1045,2450 1058.12,2450 1072.96,2435.16 v4(1074.36,2435.16)
  BOTTOM w5: CN7.4@782.52,3233.06 770,3220.54 C57.1@770,3130 795,3130 v1(800,3125) ; v4(1074.36,2435.16) U11.G6@1084.21,2425.31
NETC57_2: C57.2 R78.1 | length 50
  BOTTOM w5: R78.1@770,3040 C57.2@770,3090
NETC58_1: C58.1 U11.B7 | length 1069.3
  TOP w5: v4(995.64,2415.48) 995.64,2430 1005.64,2440 1050,2440 1070,2420 1140,2420 1150,2430 1150,2680 1265,2795 1385,2795 1475,2885 v1(1475,3060)
  BOTTOM w5: U11.B7@985.79,2405.63 v4(995.64,2415.48) ; C58.1@1440,3060 v1(1475,3060)
NETC58_2: C58.2 CN6.4 | length 120.3
  BOTTOM w5: C58.2@1440,3120 1457.52,3137.52 CN6.4@1457.52,3233.06
NETC59_1: C59.1 CN7.6 U11.H6 | length 1184.2
  TOP w5: v1(1069,3040) 1070,3039 1070,2884 1075,2879 1120,2879 1125,2874 1125,2864 1120,2859 1080.86,2859 1075,2853.14 1075,2844.86 1080.86,2839 1114.14,2839 1120,2833.14 1120,2824.86 1114.14,2819 1080.86,2819 1075,2813.14 1075,2804.86 1080.86,2799 1114.14,2799 1120,2793.14 1120,2784.86 1114.14,2779 1083,2779 1075,2771 1075,2733 1083,2725 1120,2725 1125,2720 1125,2578 1117,2570 1053.2,2570 1043.2,2560 1043.2,2499 1042.97,2498.77 1042.97,2489.23 1043.19,2489.01 1043.19,2469.77 1052.96,2460 1109,2460 v1(1129.49,2439.51)
  BOTTOM w5: v1(1069,3040) C59.1@1095,3040 1097.48,3037.52 CN7.6@1097.48,2941.73 ; U11.H6@1103.9,2425.31 1115.31,2425.31 v1(1129.49,2439.51)
NETC59_2: C59.2 R77.1 | length 45
  BOTTOM w10: C59.2@1095,3080 R77.1@1140,3080
NETC60_1: C60.1 C61.2 CN1.27 CN1.29 L3.2 | length 404
  TOP w10: CN1.29@3499.83,3276.53 3499.83,3230.83 3489,3220 v1(3489,3214) 3505,3214 3519.52,3228.52 CN1.27@3519.52,3276.53
  BOTTOM w20: L3.2@3467.51,3246.92 C60.1@3527.51,3246.92 ; v1(3489,3214) 3510,3214 3527.51,3231.51 C60.1@3527.51,3246.92 ; C61.2@3630,3190 3588.08,3246.92 C60.1@3527.51,3246.92
NETC60_2: C60.2 C61.1 CN1.21 CN1.23 L4.2 | length 428.1
  TOP w10: v1(3539,3340) 3542,3340 3558.89,3323.11 CN1.23@3558.89,3276.53 ; v1(3572,3339) 3578.57,3332.43 CN1.21@3578.57,3276.53
  BOTTOM w20: v1(3539,3340) 3527.51,3328.51 C60.2@3527.51,3306.92 3534.43,3300 C61.1@3630,3300 ; v1(3572,3339) 3573,3338 3592,3338 C61.1@3630,3300 ; L4.2@3700,3295 3695,3300 C61.1@3630,3300
NETC62_1: C62.1 U11.D7 | length 1097.1
  TOP w5: v4(1015.3,2395.77) 1015.3,2394.7 1030,2380 1040,2380 1067.28,2407.28 1089.09,2407.28 1089.19,2407.38 1147.38,2407.38 1165,2425 1165,2675 1275,2785 v1(1725,2785)
  BOTTOM w5: v4(1015.3,2395.77) U11.D7@1025.16,2405.63 ; v1(1725,2785) 1770,2785 C62.1@1775,2780
NETC62_2: C62.2 CN6.6 | length 102.8
  BOTTOM w5: CN6.6@1772.48,2941.73 1775,2939.21 C62.2@1775,2840
NETC63_2: C63.2 U11.F1 | length 138
  BOTTOM w5: U11.F1@1064.53,2523.74 1105,2564.21 C63.2@1105,2645
NETC66_1: C66.1 R84.1 U10.1 | length 185.3
  BOTTOM w20: U10.1@4070,2739.92 4070,2730 4095,2705 C66.1@4170,2705 R84.1@4170,2770
NETC72_2: C72.2 U13.E11 | length 149.4
  BOTTOM w15: v3(2339,2221) U13.E11@2355.51,2204.49
  BOTTOM w20: C72.2@2110,2417 2183,2417 2200,2400 v1(2229,2400)
NETC74_1: C74.1 U11.G7 | length 163.1
  L4_SIG w3.5: v4(1093.96,2395.88) 1120,2395.88
  L4_SIG w4: 1120,2395.88 1145.88,2395.88 v1(1190,2440)
  BOTTOM w3.5: U11.G7@1084.21,2405.63 v4(1093.96,2395.88)
  BOTTOM w5: v1(1190,2440) C74.1@1225,2440
NETC77_2: C77.2 R97.1 X1.1 | length 133.4
  BOTTOM w8: R97.1@2975,2375 C77.2@3020,2375 3079.72,2375 X1.1@3100,2395.28
NETC78_1: C78.1 U11.H7 | length 127.6
  BOTTOM w5: U11.H7@1103.9,2405.63 1209.37,2405.63 C78.1@1225,2390
NETC82_1: C82.1 U11.H8 | length 144.3
  BOTTOM w5: U11.H8@1103.9,2385.94 1169.06,2385.94 C82.1@1225,2330
NETC82_2: C82.2 U11.G8 | length 273.4
  L4_SIG w4: v4(1093.96,2376.19) 1093.96,2348.32 1126.87,2315.41 1184.59,2315.41 v1(1210,2290)
  BOTTOM w3.5: U11.G8@1084.21,2385.94 v4(1093.96,2376.19)
  BOTTOM w5: v1(1210,2290) 1245,2290 C82.2@1285,2330
NETC84_2: C84.2 R99.1 X1.2 | length 137.5
  BOTTOM w8: R99.1@2975,2325 2980,2330 C84.2@3020,2330 3074.72,2330 X1.2@3100,2304.72
NETC87_1: C87.1 R101.2 R102.1 | length 90
  BOTTOM w10: C87.1@665,2255 R102.1@710,2255 R101.2@755,2255
NETC87_2: C87.2 CN8.4 | length 133.4
  BOTTOM w10: CN8.4@572.41,2390 665,2297.41 C87.2@665,2295
NETC90_1: C90.1 U11.E6 | length 258.4
  L4_SIG w4: v4(1054.59,2415.56) 1054.59,2369.13 1133.72,2290 v1(1175,2290)
  BOTTOM w3.5: U11.E6@1044.84,2425.31 v4(1054.59,2415.56)
  BOTTOM w5: C90.1@1175,2245 v1(1175,2290)
NETC93_1: C93.1 U11.D9 | length 125.5
  BOTTOM w5: C93.1@1015,2245 1015,2300 1025.16,2310.16 U11.D9@1025.16,2366.26
NETC95_2: C95.2 U11.C9 | length 176.6
  BOTTOM w5: C95.2@915,2245 915,2270 955,2310 985.47,2310 1005.47,2330 U11.C9@1005.47,2366.26
NETC119_1: C119.1 R114.1 R115.2 U16.4 | length 151.7
  BOTTOM w10: R115.2@715,1580 R114.1@765,1580 C119.1@765,1625 770.43,1630.43 U16.4@819.41,1630.43
NETC119_2: C119.2 R117.1 | length 390.2
  TOP w5: v1(765,1700) 845,1700 930,1615 v1(930,1495)
  BOTTOM w5: C119.2@765,1665 v1(765,1700) ; v1(930,1495) R117.1@930,1530
NETC120_1: C120.1 CN12.4 R111.2 | length 165.4
  BOTTOM w10: CN12.4@572.41,1720 627.41,1665 C120.1@670,1665 R111.2@715,1665
NETC120_2: C120.2 R116.1 | length 45
  BOTTOM w10: R116.1@670,1580 C120.2@670,1625
NETC148_1: C148.1 L7.1 R132.1 R142.2 U21.1 | length 1144.2
  L4_SIG w20: v1(2374,355) 2384,345 2825,345 2870,300 2918,300 2943,325 2985,325 v1(3011,351)
  BOTTOM w20: v1(2374,355) 2374,502 2392,520 C148.1@2430,520 ; R132.1@2430,590 C148.1@2430,520 ; U21.1@2492.6,522.24 2490.36,520 C148.1@2430,520 ; R142.2@2970,390 2972,390 v1(3011,351) 3050,312 L7.1@3050,305
NETC153_2: C153.2 C154.2 C156.2 C157.2 CN15.5 CN15.6 CN15.7 CN15.8 CN15.9 CN15.10 L8.2 | length 709.5
  BOTTOM w20: 2920,140.98 C156.2@2920,160 ; 2920,179.02 C156.2@2920,160 ; 2920,265.98 C153.2@2920,285 ; 2920,304.02 C153.2@2920,285 ; 2930,205.98 L8.2@2930,230 ; 2930,254.02 L8.2@2930,230 ; 2931.96,50.4 CN15.9@2967.48,50.4 2967.48,95.92 ; 2939.02,160 C156.2@2920,160 ; 2939.02,285 C153.2@2920,285 ; 2955.52,230 L8.2@2930,230 ; 3012.28,175.6 CN15.6@3041.3,175.6 3041.3,136.08 ; 3182.05,128.28 CN15.5@3182.05,162.8 3182.05,197.32 ; 3220.44,136.08 CN15.7@3220.44,175.6 ; 3220.44,215.12 CN15.7@3220.44,175.6 ; 3220.98,245 C154.2@3240,245 ; 3240,225.98 C154.2@3240,245 ; 3249.46,175.6 CN15.7@3220.44,175.6 ; 3259.02,245 C154.2@3240,245 ; 3294.26,95.92 CN15.8@3294.26,50.4 3329.78,50.4 ; 3360.98,55 C157.2@3380,55 ; 3380,35.98 C157.2@3380,55 ; 3380,74.02 C157.2@3380,55
NETC200_1: C200.1 R85.1 U10.2 | length 137
  BOTTOM w20: R85.1@3950,2800 C200.1@3950,2735 4015.08,2735 U10.2@4020,2739.92
NETCN1_8: CN1.8 SB1.1 | length 113.6
  TOP w5: SB1.1@3689.67,2948.01 3689.67,2973.3 3716.37,3000 CN1.8@3716.37,3050.55
NETCN1_10: CN1.10 SB2.1 | length 145
  TOP w5: SB2.1@3620,2950 3660,2990 3681.68,2990 3696.68,3005 CN1.10@3696.68,3050.55
NETCN1_14: CN1.14 SB3.1 | length 188.1
  TOP w5: SB3.1@3549.67,2948.01 3549.67,2969.67 3560,2980 3630,2980 3657.31,3007.31 CN1.14@3657.31,3050.55
NETCN1_16: CN1.16 SB4.1 | length 238.3
  TOP w5: SB4.1@3479.67,2948.01 3479.67,2969.67 3505,2995 3625,2995 3637.63,3007.63 CN1.16@3637.63,3050.55
NETCN1_39: CN1.39 R7.2 | length 125.6
  TOP w5: v1(3380,3340) 3381.41,3340 3401.41,3320 CN1.39@3401.41,3276.53
  BOTTOM w5: R7.2@3350,3300 3350,3310 v1(3380,3340)
NETCN2_1: CN2.1 R50.2 SB5.2 | length 310.7
  TOP w5: CN2.1@815,960 870,905 R50.2@1040,905 1044.17,909.17 SB5.2@1044.17,966.19
NETCN2_7: CN2.7 SB6.2 SB8.2 | length 323.5
  TOP w5: CN2.7@815,660 873.81,601.19 SB6.2@1044.17,601.19 SB8.2@1044.17,531.19
NETCN2_8: CN2.8 R57.1 | length 143.6
  TOP w5: CN2.8@915,660 960,705 R57.1@1040,705
NETCN5_10: CN5.10 R73.2 | length 126.8
  BOTTOM w5: CN5.10@2856.93,3272.79 2856.93,3228.07 R73.2@2915,3170
NETCN9_8: CN9.8 R98.1 | length 189.3
  BOTTOM w5: CN9.8@1405.8,2427.7 1478.5,2355 R98.1@1565,2355
NETCN10_1: CN10.1 T4.16 | length 310.8
  BOTTOM w5.1: T4.16@4317.52,1675 4359,1675 4396,1712 4428,1712 4489,1773 4489,1824.78 4503.67,1839.45 CN10.1@4529.88,1839.45
NETCN10_2: CN10.2 T4.14 | length 313.2
  BOTTOM w5.1: T4.14@4317.52,1775 4350,1775 4398,1727 4421.78,1727 4474,1779.22 4474,1831 4497,1854 4497,1871.97 CN10.2@4486.58,1879.61
NETCN10_3: CN10.3 T4.11 | length 243.5
  BOTTOM w5.1: T4.11@4317.52,1925 4355,1925 4390,1960 4440,1960 4480.24,1919.76 CN10.3@4529.88,1919.76
NETCN10_4: CN10.4 CN10.5 D4.4 R42.2 | length 1038.5
  TOP w5: D4.4@4023.74,1316.57 4064.43,1316.57 v1(4084,1297) ; R42.2@4385,1755 4385,1761 4409,1785 v1(4409,1799) 4450,1840 4450,1920.56 CN10.4@4486.58,1959.92 4529.52,2000.08 CN10.5@4529.88,2000.08
  L4_SIG w4: v1(4084,1297) 4096,1309 4144,1309 4400,1565 4400,1790 v1(4409,1799)
NETCN10_6: CN10.6 T4.9 | length 244.3
  BOTTOM w5.1: T4.9@4317.52,2025 4355,2025 4385,1995 4385,1980 4390,1975 4451.12,1975 4489.36,2013.24 CN10.6@4486.58,2040.24
NETCN10_7: CN10.7 CN10.8 D4.3 R26.2 | length 1051.2
  TOP w5: D4.3@4023.74,1513.43 4063.43,1513.43 v1(4080,1530) ; v1(4343.61,2065.18) 4378.79,2030 R26.2@4380,2030 4470.55,2120.55 CN10.8@4486.58,2120.55 4492.5,2120.55 CN10.7@4529.88,2080.39
  L4_SIG w4: v1(4080,1530) 4095,1545 4245,1545 4300,1600 4300,2021.57 v1(4343.61,2065.18)
NETCN11_1: CN11.1 R103.1 | length 120.3
  BOTTOM w20: CN11.1@3305.8,2267.7 3308.5,2265 R103.1@3425,2265
NETCN14_5: CN14.5 SB13.2 SB14.2 | length 3464.8
  L4_SIG w4: v1(1669,2379) 1669,2164 1745,2088 1745,845 v1(1732,832)
  BOTTOM w5: SB13.2@1600.83,2491.19 SB14.2@1600.83,2421.19 1643.02,2379 v1(1669,2379) ; v1(1732,832) 1735,835 2040,835 2075,800 2140,800 2175,765 2555,765 2575,745 2655,745 2675,765 2707,765 2732,740 2929,740 3156.7,967.7 CN14.5@3305.8,967.7
NETCN14_6: CN14.6 SB11.2 SB12.2 | length 3658.5
  L4_SIG w4: v1(1670,2406) 1697,2379 1697,2303 1731,2269 1731,2118 1757,2092 1757,831 v1(1732,806)
  BOTTOM w5: SB11.2@1600.83,2636.19 SB12.2@1600.83,2566.19 1643.81,2566.19 1655,2555 1655,2421 v1(1670,2406) ; v1(1732,806) 1746,820 2020,820 2060,780 2130,780 2160,750 2550,750 2577,723 2941,723 3143,925 3250,925 3305.8,869.2 CN14.6@3305.8,867.7
NETCN15_4: CN15.4 D12.A2 U20.23 | length 621.1
  TOP w5: v1(3040,499) 3061,520 3180,520 3250,450 3250,365 v1(3240,355)
  BOTTOM w5: v1(3040,499) 3060.79,519.79 U20.23@3060.79,534.72 ; CN15.4@3156.46,162.8 3156.46,200.46 3192.87,236.87 D12.A2@3192.87,257.13 3198.13,257.13 3211,270 3211,326 v1(3240,355)
NETCN16_4: CN16.4 R149.2 | length 82.7
  BOTTOM w5: R149.2@3685,235 3709.41,210.59 CN16.4@3709.41,162.4
NETD1_1: D1.1 R10.2 R12.2 T1.1 | length 254.1
  TOP w20: T1.1@3729.02,2629.45 3790.16,2629.45 D1.1@3810.71,2650 3810.71,2730.71 R10.2@3820,2740 R12.2@3890,2740
NETD1_2: D1.2 R2.2 | length 939.9
  TOP w15: D1.2@3899.29,2650 v1(3899.29,2685) ; v1(3923,3270) R2.2@3964.49,3270
  L4_SIG w15: v1(3899.29,2685) 3899.29,2779.29 3955,2835 3955,2945 4015,3005 4080,3005 4115,3040 4115,3200 4075,3240 3953,3240 v1(3923,3270)
NETD3_1: D3.1 R24.1 | length 78.8
  BOTTOM w20: D3.1@3555.71,2555 3565,2545.71 R24.1@3565,2480
NETD5_2: D5.2 D6.2 D7.2 D8.2 SB7.1 | length 387.9
  TOP w15: SB7.1@4240.33,696.99 4240.33,694.67 4265,670 D8.2@4310.71,670 D7.2@4310.71,775 D6.2@4310.71,875 D5.2@4310.71,975
NETD9_3: D9.3 R46.2 T4.15 | length 739.5
  TOP w5: v1(4370,1715) 4375,1715 4385,1705 R46.2@4385,1670
  L4_SIG w4: v1(4084,1337) 4099,1322 4135,1322 4385,1572 4385,1700 v1(4370,1715)
  BOTTOM w5: D9.3@4023.74,1316.57 4063.57,1316.57 v1(4084,1337) ; T4.15@4317.52,1725 4360,1725 v1(4370,1715)
NETD9_4: D9.4 R33.2 T4.10 | length 847.4
  TOP w5: v1(4366,1984) 4385,1965 R33.2@4385,1940
  L4_SIG w4: v1(4080,1500) 4110,1530 4245,1530 4310,1595 4310,1928 v1(4366,1984)
  BOTTOM w5: D9.4@4023.74,1513.43 4066.57,1513.43 v1(4080,1500) ; T4.10@4317.52,1975 4357,1975 v1(4366,1984)
NETD11_2: D11.2 R141.2 | length 88.8
  BOTTOM w20: D11.2@3480.71,395 3490,404.29 R141.2@3490,480
NETJP2_1: JP2.1 U11.B1 | length 1051.4
  BOTTOM w5: JP2.1@605,3365 668,3302 668,2957 805,2820 805,2615 850.21,2569.79 939.74,2569.79 U11.B1@985.79,2523.74
NETJP2_2: JP2.2 U11.A2 | length 954.5
  BOTTOM w5: JP2.2@605,3265 645,3225 645,2940 780,2805 780,2615 845.96,2549.04 921.12,2549.04 U11.A2@966.1,2504.06
NETJP3_1: JP3.1 U11.C3 | length 1098.3
  L4_SIG w4: JP3.1@480,3365 545,3300 545,3240 715,3070 715,2855 925.35,2644.65 925.35,2580 987.54,2517.81 987.54,2502.3 v4(995.72,2494.12)
  BOTTOM w3.5: v4(995.72,2494.12) U11.C3@1005.47,2484.37
NETJP3_2: JP3.2 U11.B3 | length 990.1
  L4_SIG w4: JP3.2@480,3265 695,3050 695,2845 880,2660 880,2591.23 965,2506.23 965,2505.16 v4(976.04,2494.12)
  BOTTOM w3.5: v4(976.04,2494.12) U11.B3@985.79,2484.37
NETLD1_1: LD1.1 R62.2 | length 85
  TOP w5: LD1.1@1290,245 R62.2@1290,330
NETLD2_1: LD2.1 R63.2 | length 85
  TOP w5: LD2.1@1390,245 R63.2@1390,330
NETLD3_1: LD3.1 R64.1 | length 95
  TOP w5: LD3.1@1490,245 R64.1@1490,340
NETLD4_1: LD4.1 R65.1 | length 85
  TOP w5: LD4.1@1590,245 R65.1@1590,330
NETLD4_2: LD4.2 R129.1 R130.2 U21.3 | length 1325.8
  TOP w5: LD4.2@1590,185 v1(1635,185)
  BOTTOM w5: v1(1635,185) 2090,640 2305,640 2335,670 2497,670 2516,651 2516,614 R130.2@2540,590 R129.1@2585,590 2585,554 2567.4,536.4 U21.3@2567.4,522.24
NETLD5_1: LD5.1 R66.1 | length 95
  TOP w5: LD5.1@1685,245 R66.1@1685,340
NETLD5_2: LD5.2 T5.3 | length 754.4
  TOP w5: LD5.2@1685,185 v1(1723,185)
  BOTTOM w5: v1(1723,185) 2128,590 T5.3@2271.69,590
NETLD6_1: LD6.1 R58.2 | length 100
  TOP w5: LD6.1@1780,245 R58.2@1780,345
NETLD7_1: LD7.1 R59.1 | length 100
  TOP w5: LD7.1@1885,245 R59.1@1885,345
NETLD7_2: LD7.2 R150.1 U22.8 | length 2633.8
  TOP w20: LD7.2@1885,185 v2(1920,185)
  L4_SIG w20: v2(1920,185) 2025,80 2860,80 2907.49,127.49 2987.51,127.49 3010,105 3225,105 3385,265 3665,265 3685,245 v2(4275,245)
  BOTTOM w20: R150.1@4235,230 4260,230 v2(4275,245) 4288.3,258.3 U22.8@4288.3,290
NETLD8_2: LD8.2 R60.2 | length 71.1
  TOP w5: R60.2@3420,345 3420.47,344.53 LD8.2@3420.47,274.06
NETLD8_3: LD8.3 R61.2 | length 71.1
  TOP w5: LD8.3@3479.53,274.06 3479.53,344.53 R61.2@3480,345
NETR1_2: R1.2 U1.7 | length 181.2
  TOP w10: U1.7@4356.14,3183.98 4383.98,3183.98 4396.14,3196.14 4396.14,3256.14 R1.2@4450,3310
NETR2_1: R2.1 R10.1 U1.10 | length 676.8
  TOP w10: R2.1@4025.51,3270 4070,3225.51 v1(4070,3205) 4070,3200 4086.02,3183.98 U1.10@4123.86,3183.98
  TOP w20: R10.1@3820,2810 v1(3820,2855)
  L4_SIG w15: v1(3820,2855) 3820,2960 3865,3005 3900,3005 3995,3100 3995,3145 4055,3205 v1(4070,3205)
NETR3_2: R3.2 U1.5 | length 112.6
  TOP w10: U1.5@4356.14,3132.8 4387.8,3132.8 R3.2@4445,3190
NETR4_2: R4.2 R9.2 T1.3 | length 372.3
  TOP w20: T1.3@3729.02,2810.55 3760,2841.53 R9.2@3760,2905 3855,3000 3905,3000 3955,3050 R4.2@3965,3050
NETR5_2: R5.2 U1.14 U10.4 | length 261.7
  TOP w10: R5.2@4025,3000 4053,3028 4053,3058 v1(4070,3075) 4076.61,3081.61 U1.14@4123.86,3081.61
  BOTTOM w10: U10.4@4070,2990.08 4070,3010 4045,3035 4045,3060 4060,3075 v1(4070,3075)
NETR6_1: R6.1 U1.1 | length 121
  TOP w10: U1.1@4356.14,3030.43 4384.57,3030.43 R6.1@4450,2965
NETR20_2: R20.2 R21.2 U13.E5 | length 391
  TOP w5: v3(2559.34,2219.34) 2575,2235 2575,2295 2595,2315 2595,2367 2590,2372 2590,2492.25 2589.5,2492.75 2589.5,2507.25 2590,2507.75 2590,2525 R20.2@2595,2530 R21.2@2635,2530
  BOTTOM w4: U13.E5@2544.49,2204.49 v3(2559.34,2219.34)
NETR27_2: R27.2 U3.5 | length 55.5
  TOP w5: R27.2@3620,1980 3625.47,1974.53 U3.5@3625.47,1926.77
NETR30_1: R30.1 R32.1 U3.7 | length 161.3
  TOP w5: R30.1@3480,1995 R32.1@3480,1955 3535.79,1899.21 U3.7@3578.23,1899.21
NETR31_1: R31.1 U3.24 | length 146.9
  TOP w5: U3.24@3731.77,1899.21 3745.21,1899.21 3767,1921 3767,1947 3800,1980 R31.1@3830,1980
NETR34_1: R34.1 R36.1 U3.8 | length 140.1
  TOP w5: R34.1@3480,1915 R36.1@3480,1875 3495,1875 3499.53,1879.53 U3.8@3578.23,1879.53
NETR38_1: R38.1 T4.7 | length 173.7
  TOP w20: v1(3930,1975) 3955,1975 3970,1960 R38.1@3970,1885
  BOTTOM w20: v1(3930,1975) T4.7@3982.48,1975
NETR38_2: R38.2 T4.2 | length 170.8
  TOP w20: v1(3930,1725) 3950,1725 3970,1745 R38.2@3970,1815
  BOTTOM w20: v1(3930,1725) T4.2@3982.48,1725
NETR43_1: R43.1 R44.1 U3.11 | length 182.4
  TOP w5: R44.1@3480,1695 R43.1@3480,1750 3499,1750 3569.47,1820.47 U3.11@3578.23,1820.47
NETR51_1: R51.1 U6.2 | length 131.4
  TOP w5: U6.2@2667.47,809.28 2655.72,809.28 2630,835 2630,870 2650,890 R51.1@2670,890
NETR64_2: R64.2 SB15.1 | length 2014.7
  TOP w5: R64.2@1490,380 1490,492 v1(1524,526)
  L4_SIG w4: v1(1524,526) 1705,707 1705,860 1730,885 1730,2080 1650,2160 1620,2160 v1(1605,2175)
  BOTTOM w5: v1(1605,2175) 1608.01,2178.01 SB15.1@1608.01,2224.67
NETR71_1: R71.1 U9.2 | length 95
  TOP w5: R71.1@2585,255 2630,255 2660.33,224.67 U9.2@2667.47,224.67
NETR87_1: R87.1 U11.D4 U11.D5 | length 237
  L4_SIG w4: v1(1010,2605) 980,2575 980,2544.54 1000,2524.54 1000,2513.42 1006.72,2506.7 1006.72,2485 1004.45,2482.73 1004.45,2465.71 v4(1015.45,2454.71)
  BOTTOM w3.5: U11.D5@1025.16,2445 v4(1015.45,2454.71) 1015.45,2454.98 U11.D4@1025.16,2464.69
  BOTTOM w5: v1(1010,2605) R87.1@1010,2635
NETR88_2: R88.2 U11.H1 | length 141.5
  BOTTOM w5: U11.H1@1103.9,2523.74 1145.16,2565 1200,2565 R88.2@1220,2585
NETR94_1: R94.1 U11.G2 | length 150.7
  L4_SIG w3.5: v4(1093.96,2513.81) 1120,2539.85
  L4_SIG w4: 1120,2539.85 1120.15,2540 v1(1190,2540)
  BOTTOM w3.5: U11.G2@1084.21,2504.06 v4(1093.96,2513.81)
  BOTTOM w5: v1(1190,2540) R94.1@1220,2540
NETR95_2: R95.2 U11.F3 | length 165.9
  L4_SIG w4: v4(1074.28,2474.62) 1085.66,2486 1186,2486 v1(1190,2490)
  BOTTOM w3.5: U11.F3@1064.53,2484.37 v4(1074.28,2474.62)
  BOTTOM w5: v1(1190,2490) R95.2@1220,2490
NETR100_2: R100.2 R101.1 | length 45
  BOTTOM w10: R101.1@755,2295 R100.2@800,2295
NETR107_2: R107.2 X2.1 | length 64.1
  BOTTOM w5: R107.2@3100,2075 3106.42,2081.42 X2.1@3106.42,2136.46
NETR108_2: R108.2 U13.L5 | length 304.4
  L4_SIG w4: v3(2560,2032) 2577,2015 2645,2015 2670,2040 2755.74,2040 2775.12,2059.38 2775.12,2059.31 v1(2775.21,2059.31)
  BOTTOM w5: U13.L5@2544.49,2015.51 2560,2031.02 v3(2560,2032) ; v1(2775.21,2059.31) 2789.5,2045 R108.2@2810,2045
NETR112_1: R112.1 R117.2 U15.2 | length 232.9
  BOTTOM w5: R112.1@930,1620 R117.2@930,1570 955,1545 955,1509 969,1495 990,1495 1005,1510 U15.2@1005,1559.57
NETR115_1: R115.1 R116.2 U16.2 | length 304.1
  BOTTOM w10: R116.2@670,1540 R115.1@715,1540 715,1490 730,1475 825,1475 845,1495 U16.2@845,1559.57
NETR121_2: R121.2 U19.3 | length 132.8
  BOTTOM w5: R121.2@3615,895 3650,860 3680,860 3691.1,848.9 U19.3@3691.1,811.26
NETR122_2: R122.2 U19.2 | length 155
  BOTTOM w5: R122.2@3570,895 3594.5,870.5 3620.5,870.5 3641,850 3665,850 3671.42,843.58 U19.2@3671.42,811.26
NETR126_1: R126.1 U20.32 | length 65.2
  BOTTOM w5: R126.1@2950,700 2951.1,698.9 U20.32@3014.72,698.9
NETR127_2: R127.2 U19.44 | length 58.9
  BOTTOM w5: R127.2@3530,670 3530.47,669.53 U19.44@3588.74,669.53
NETR131_1: R131.1 R132.2 T5.1 | length 132.8
  BOTTOM w5: T5.1@2358.31,627.4 2427.4,627.4 R132.2@2430,630 R131.1@2490,630
NETR134_2: R134.2 X4.1 | length 69.2
  BOTTOM w5: R134.2@2710,620 2723.54,633.54 X4.1@2773.58,633.54
NETR136_2: R136.2 U20.26 | length 75.4
  BOTTOM w8: R136.2@2950,575 2960,565 2980,565 2995.79,580.79 U20.26@3014.72,580.79
NETR139_1: R139.1 U20.24 | length 106.6
  BOTTOM w5: R139.1@2950,530 2961,519 3033,519 3041.1,527.1 U20.24@3041.1,534.72
NETR140_1: R140.1 U22.5 | length 103.2
  BOTTOM w20: R140.1@4210,500 4270,440 U22.5@4288.3,440
NETR142_1: R142.1 U20.22 | length 153.9
  BOTTOM w5: R142.1@2970,460 2990,480 3047,480 3080.47,513.47 U20.22@3080.47,534.72
NETR145_1: R145.1 R146.2 R147.1 T3.1 | length 183
  TOP w5: T3.1@3797.4,348.31 3797.4,312.6 v1(3800,310)
  BOTTOM w5: v1(3800,310) 3800,280 R147.1@3805,275 3845,235 R146.2@3850,235 R145.1@3895,235
NETR148_2: R148.2 T3.2 | length 80.6
  TOP w5: v1(3715,305) 3722.6,312.6 T3.2@3722.6,348.31
  BOTTOM w5: v1(3715,305) 3715,285 R148.2@3725,275
NETU20_17: U20.17 U21.4 | length 876
  L4_SIG w4: v1(2570,385) 2826,385 2850,361 2974,361 3005,392 3150,392 3170,412 v1(3228,412)
  BOTTOM w5: U21.4@2567.4,427.76 2567.4,387.6 v1(2570,385) ; U20.17@3178.9,534.72 3178.9,526.1 3228,477 v1(3228,412)
NRST: CN11.3 R106.1 SB10.1 SB20.2 U3.15 U13.J1 U20.27 | length 4315.3
  TOP w5: U3.15@3645.16,1773.23 3645.16,1699.84 v1(3665,1680) ; 3945,275 3919,301 3919,524 3974,579 v1(3986,579)
  L4_SIG w4: v1(2975.63,590) 2975,589.37 2980.63,589.37 3060,510 3330,510 3425,605 3820,605 3845,580 3985,580 v1(3986,579) 3986,920 3961,945 3915,945 3847.5,1012.5 3847.5,1072.5 3665,1255 v1(3665,1680)
  BOTTOM w5: U13.J1@2670.47,2078.5 2696.97,2105 2790,2105 R106.1@2810,2085 2830,2105 2969,2105 3025,2049 3287.1,2049 CN11.3@3305.8,2067.7 3390.3,2067.7 3469,1989 3469,1775 3483,1761 3483,1713 3507,1689 3656,1689 v1(3665,1680) ; v1(2975.63,590) 2986.1,600.47 U20.27@3014.72,600.47 ; v1(3986,579) 4034,579 4040.83,585.83 SB20.2@4040.83,626.19
OSC_24M: R136.1 X4.3 | length 64.2
  BOTTOM w8: X4.3@2846.42,576.46 2847.88,575 R136.1@2910,575
OSC_25M: R27.1 R104.1 X2.3 | length 850.9
  TOP w5: R27.1@3620,2020 v1(3620,2056)
  BOTTOM w5: R104.1@2975,2205 2975,2225 2995,2245 3128.5,2245 3157.5,2216 3379,2216 3472,2123 3553,2123 v1(3620,2056)
  BOTTOM w8: R104.1@2975,2205 2986.46,2193.54 X2.3@3033.58,2193.54
OSC_IN: C142.2 U19.5 X3.2 | length 203.5
  BOTTOM w8: X3.2@3694.72,1000 3715,979.72 C142.2@3715,900 3730.47,884.53 U19.5@3730.47,811.26
OSC_OUT: C141.2 U19.6 X3.1 | length 203.3
  BOTTOM w8: U19.6@3750.16,811.26 3750.16,890.16 C141.2@3760,900 3760,974.72 X3.1@3785.28,1000
PA0: SB9.1 U13.N3 | length 4391.8
  TOP w5: SB9.1@1037.13,364.47 v1(1037.13,416.87)
  L4_SIG w4: v1(1037.13,416.87) 1059,395 1520,395 1835,710 2560,710 2570,720 2995,720 3000,715 3190,715 3215,690 3215,670 3230,655 3253,655 3268,670 3268,762 3245,785 3245,1180 3280,1215 3326,1215 3366,1255 3366,1384 3214,1536 3214,1730 3108,1836 2931,1836 2887,1880 2660,1880 2636.33,1903.67 2636.33,1918.67 2622.33,1932.67 v3(2622.33,1937.67)
  BOTTOM w5: U13.N3@2607.48,1952.52 v3(2622.33,1937.67)
PA1: R45.1 U3.14 U13.N2 | length 1314.2
  TOP w5: v1(3368,1618) 3383,1603 3488,1603 3590,1705 R45.1@3625,1705 3625.47,1705.47 U3.14@3625.47,1773.23
  L4_SIG w4: v3(2653.83,1937.67) 2653.83,1926.17 2675,1905 2945,1905 2972,1878 3108,1878 3261,1725 3351,1725 3384,1692 3384,1634 v1(3368,1618)
  BOTTOM w5: U13.N2@2638.98,1952.52 v3(2653.83,1937.67)
PA2: R47.1 U3.12 U13.P2 | length 1170
  TOP w5: v1(3365,1660) 3374,1669 3461,1669 R47.1@3480,1650 3500,1670 3500,1733 3567.79,1800.79 U3.12@3578.23,1800.79
  L4_SIG w4: v3(2653.83,1906.17) 2665,1895 2936,1895 2967,1864 3103,1864 3257,1710 3335,1710 3365,1680 v1(3365,1660)
  BOTTOM w5: U13.P2@2638.98,1921.02 v3(2653.83,1906.17)
PA3: U13.R2 U20.3 | length 1558.1
  L4_SIG w4: v3(2733,1799) 2879,1799 2924,1754 3052,1754 3117,1689 3117,810 v1(3100,793)
  BOTTOM w5: U13.R2@2638.98,1889.53 2641.47,1889.53 2646,1885 2651.66,1885 2685.66,1851 2712,1851 2732,1831 2732,1800 v3(2733,1799) ; U20.3@3080.47,725.28 3080.47,773.47 v1(3100,793)
PA5: U13.P4 U20.1 | length 1604.4
  L4_SIG w4: v3(2590.83,1906.17) 2590.83,1905.83 2586.89,1901.89 2586.89,1843.11 2636,1794 2670,1794 2705.5,1758.5 2705.5,1743.5 2711,1738 2877,1738 2895,1720 3023,1720 3066,1677 3066,799 v1(3061,794)
  BOTTOM w4: U13.P4@2575.98,1921.02 v3(2590.83,1906.17)
  BOTTOM w5: U20.1@3041.1,725.28 3041.1,774.1 v1(3061,794)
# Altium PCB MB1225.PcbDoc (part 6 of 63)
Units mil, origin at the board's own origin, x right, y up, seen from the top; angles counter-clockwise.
Board outline 5000 x 3464.56 mil, 6 copper layers (TOP, L2_GND, L3_VCC, L4_SIG, L5_GND, BOTTOM), stack 62.2 mil thick; 452 components, 378 nets, 1968 pads, 949 vias.

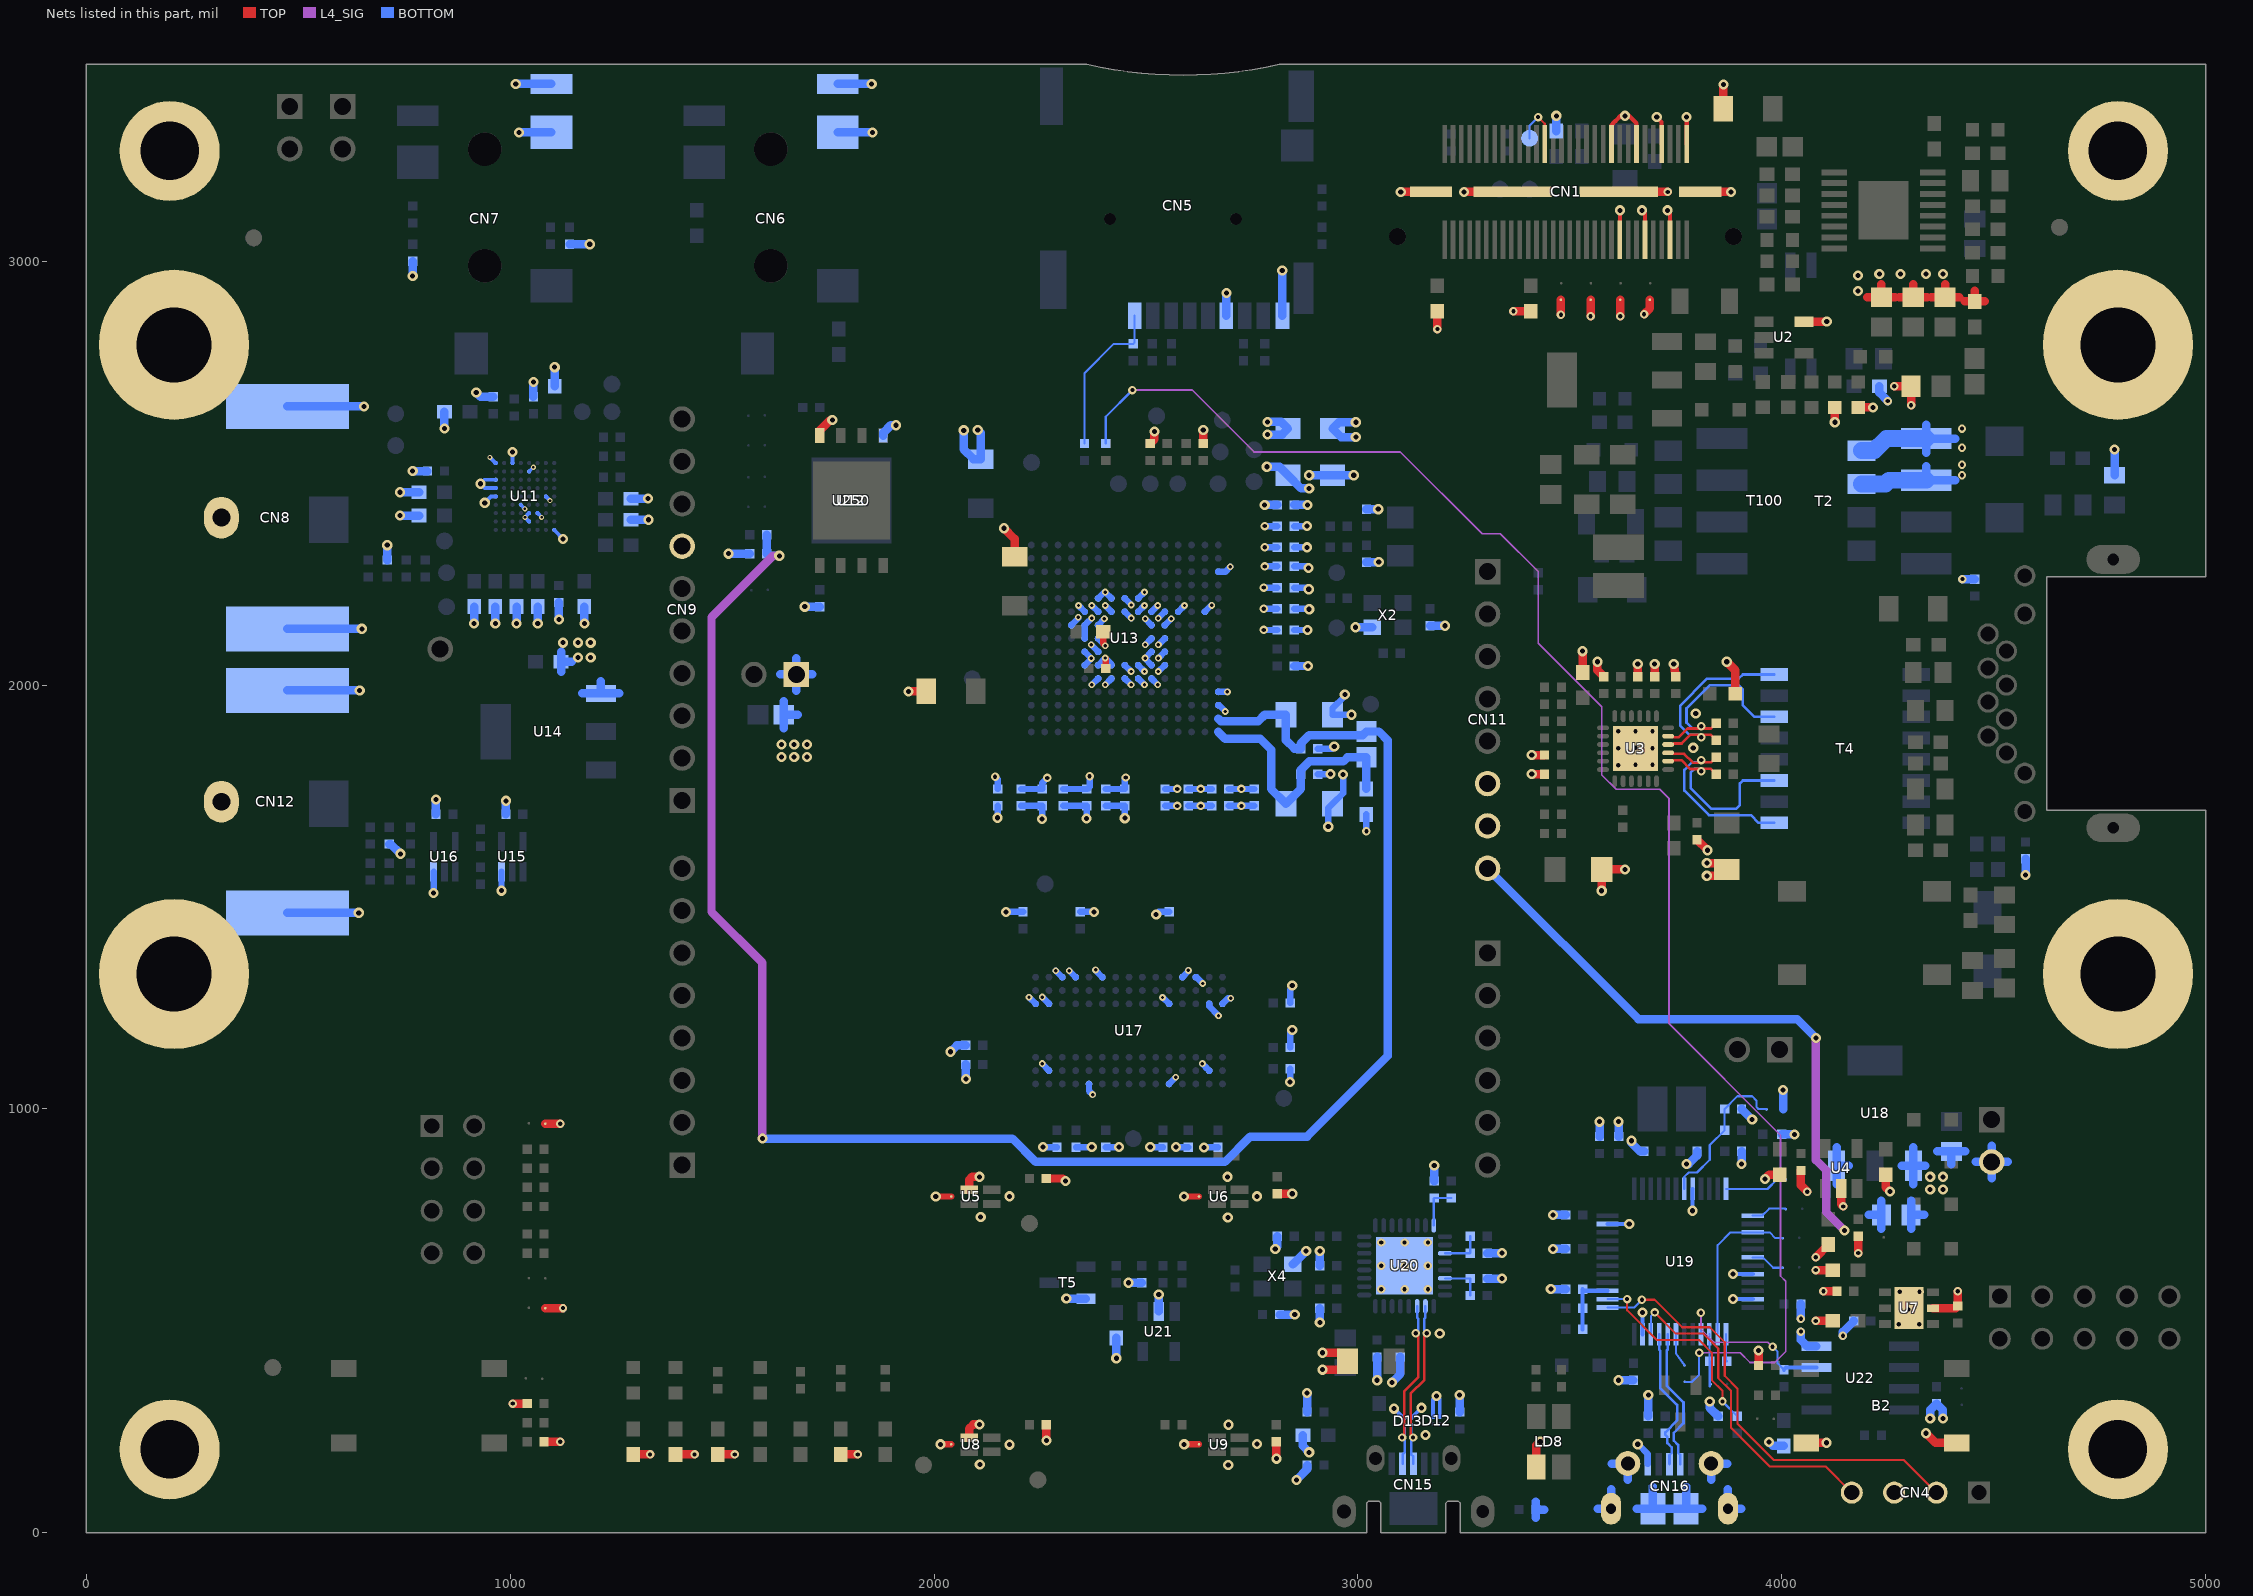
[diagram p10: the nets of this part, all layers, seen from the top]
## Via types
v1: diameter 20, hole 10, TOP to BOTTOM, 354 vias
v2: diameter 24, hole 12, TOP to BOTTOM, 349 vias
v3: diameter 16, hole 8, TOP to BOTTOM, 219 vias
v4: diameter 12, hole 6, TOP to BOTTOM, 27 vias

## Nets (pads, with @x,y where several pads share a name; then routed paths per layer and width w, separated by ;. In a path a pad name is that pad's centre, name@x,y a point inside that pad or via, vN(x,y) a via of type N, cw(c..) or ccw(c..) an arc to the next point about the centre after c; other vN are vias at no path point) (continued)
POE7: B2.2 B2.3 C1.1 C2.1 C3.2 C13.1 C14.1 C15.1 C16.1 C18.1 C23.1 C25.1 C27.1 C28.1 C29.1 C30.1 C31.1 C33.1 C35.1 C36.2 C38.2 C41.2 C42.1 C43.1 C44.2 C45.2 C46.1 C47.1 C48.1 C49.1 C50.1 C51.1 C52.1 C53.1 C54.1 C55.2 C56.2 C63.1 C64.2 C65.2 C66.2 C67.1 C68.2 C69.2 C71.2 C72.1 C73.1 C74.2 C76.1 C77.1 C78.2 C79.1 C80.1 C83.1 C84.1 C85.1 C86.1 C88.1 C90.2 C91.2 C92.2 C93.2 C94.2 C95.1 C96.1 C97.1 C98.1 C99.1 C100.1 C101.2 C102.1 C103.1 C104.1 C105.1 C106.1 C107.1 C108.1 C109.1 C110.1 C111.1 C112.1 C113.1 C114.1 C115.1 C116.2 C117.1 C118.1 C123.1 C124.1 C125.1 C126.1 C127.1 C128.1 C129.1 C130.1 C131.1 C132.1 C133.1 C134.1 C135.1 C136.1 C137.1 C138.1 C139.1 C140.2 C141.1 C142.1 C143.1 C144.2 C145.1 C146.1 C147.2 C148.2 C149.1 C150.2 C151.1 C152.1 C153.1 C154.1 C155.1 C156.1 C157.1 CN1.1 CN1.6 CN1.7 CN1.12 CN1.13 CN1.18 CN1.19 CN1.61 CN1.62 CN1.63 CN1.64 CN4.3 CN5.6 CN5.9 CN6.2 CN6.3 CN7.2 CN7.3 CN8.1 CN8.2 CN8.3 CN9.7 CN11.6 CN11.7 CN12.1 CN12.2 CN12.3 CN16.5 CN16.6 CN16.7 CN16.8 CN16.9 CN16.10 CN16.11 D12.B1 D12.B2 D13.B1 D13.B2 H1.1 H2.1 H3.1 H4.1 H5.1 H6.1 H7.1 H8.1 JP1.2 L3.1 L8.1 LD1.2 LD2.2 LD3.2 LD6.2 LD8.1 R14.1 R15.1 R18.1 R21.1 R28.1 R29.1 R31.2 R40.1 R70.1 R77.2 R78.2 R96.2 R102.2 R105.1 R108.1 R111.1 R113.1 R119.1 R121.1 R122.1 R124.1 R127.1 R128.1 R131.2 R133.1 R135.1 R139.2 R140.2 R146.1 R149.1 SB1.2 SB2.2 SB3.2 SB4.2 SB5.1 SB8.1 SB16.1 T2.7 T2.8 T5.2 T100.5 T100.6 U2.5 U3.25 U4.2 U5.2 U5.5 U6.5 U7.2 U7.7 U8.2 U8.5 U9.5 U11.A1 U11.A3 U11.A4 U11.A5 U11.C1 U11.D6 U11.E2 U11.E7 U11.E8 U11.F7 U11.G5 U11.H9 U12.4 U13.F2 U13.F6 U13.F7 U13.F8 U13.F9 U13.F10 U13.G6 U13.G10 U13.G12 U13.H6 U13.H10 U13.J6 U13.J10 U13.K6 U13.K7 U13.K8 U13.K9 U13.K10 U13.L6 U13.M1 U13.N1 U14.1 U15.3 U16.3 U17.A3 U17.B3 U17.B8 U17.C1 U17.D1 U17.E9 U17.F1 U17.L3 U17.L9 U17.M1 U17.N1 U17.P3 U17.P8 U17.R3 U18.1 U19.8 U19.20 U19.23 U19.35 U19.47 U20.33 U21.2 U22.4 U250.4 X2.2 X4.2 | length 13554.8
  TOP w10: CN1.19@3598.26,3276.53 3598.26,3321.26 3602.44,3325.44 3602.44,3325.68 3608.29,3331.53 3608.53,3331.53 3620,3343 v2(3630,3343) 3639.62,3343 3657.31,3325.31 CN1.13@3657.31,3276.53 ; CN1.18@3617.94,3050.55 v2(3617.94,3120) ; v2(3670,3120) 3677,3113 CN1.12@3677,3050.55 ; v2(3705,3340) 3716.37,3328.63 CN1.7@3716.37,3276.53 ; v2(3730,3120) 3736.05,3113.95 CN1.6@3736.05,3050.55
  TOP w11: CN1.1@3775.42,3276.53 v2(3775.42,3340)
  TOP w15: v2(2004,793.55) U5.5@2040.43,793.55 ; v2(2015.06,208.94) U8.5@2040.43,208.94 ; C25.1@2399,2126 2399,2098 v3(2404,2093) ; v3(2404,2064) 2405,2063 C27.1@2405,2039 ; v2(2590,793.55) U6.5@2625.04,793.55 ; v2(2590.06,208.94) U9.5@2625.04,208.94
  TOP w20: v1(1006,305) C54.1@1040,305 ; R70.1@1080,215 v1(1118,215) ; SB8.1@1083.01,530.33 v1(1124.67,530.33) ; SB5.1@1083.01,965.33 v1(1118.01,965.33) ; LD1.2@1290,185 v1(1330,185) ; LD2.2@1390,185 v1(1435,185) ; LD3.2@1490,185 v1(1530,185) ; U250.4@1730,2588.98 1730,2600 1755,2625 v2(1760,2625) ; LD6.2@1780,185 v1(1820,185) ; v2(1940,1985) C31.1@1982,1985 ; U8.2@2082.86,224.67 2082.86,245.86 2093,256 v2(2107,256) ; U5.2@2082.86,809.28 2082.86,832.86 2090,840 v2(2107,840) ; v2(2165,2370) 2190,2345 C23.1@2190,2303 ; v2(2265,218) C55.2@2265,255 ; C44.2@2265,836 2304,836 v2(2310,830) ; R18.1@2510,2570 2519.76,2579.76 v2(2519.76,2598) ; R21.1@2635,2570 v2(2635,2602) ; v2(2807.57,175) C56.2@2807.57,215 ; C45.2@2810,800 v2(2845,800) ; v2(2916,385) 2955,385 C52.1@2975,405 2955,425 v2(2916,425) ; v2(3101,3163.54) CN1.64@3172.47,3163.54 ; v1(3187.51,2840) C2.1@3187.51,2881.92 ; v2(3250,3163.54) CN1.63@3364.99,3163.54 ; v1(3366.92,2881.92) C1.1@3407.51,2881.92 ; v2(3410,1790) R40.1@3440,1790 ; v2(3410,1835) C33.1@3440,1835 ; LD8.1@3420.47,155.94 3420.47,206.47 3429,215 v2(3430,215) ; v1(3478.81,2873.81) SB4.2@3478.81,2909.17 ; C28.1@3530,2030 v2(3530,2080) ; v1(3548.81,2870) SB3.2@3548.81,2909.17 ; v2(3565,2055) 3565,2035 C29.1@3580,2020 ; v2(3575,1514.9) C38.2@3575,1565 v2(3630,1565) ; CN1.62@3614.99,3163.54 v1(3731,3163.54) ; v1(3618.81,2870) SB2.2@3618.81,2909.17 ; R28.1@3660,2020 v2(3660,2050) ; v1(3675,2875) 3688.81,2888.81 SB1.2@3688.81,2909.17 ; R29.1@3700,2020 v2(3700,2050) ; v2(3745,2050) C30.1@3750,2020 ; C35.1@3800,1635 3824.3,1610.7 v2(3824.3,1610.4) ; CN1.61@3807.51,3163.54 v2(3880,3163.54) ; v2(3823,1550) 3855,1550 C36.2@3870,1565 3855,1580 v2(3823,1580) ; C3.2@3862,3360 v2(3862,3417) ; v2(3870,2055) 3890,2035 R31.2@3890,1980 ; C53.1@3945,395 v2(3945,430) ; v2(3960,835) 3970,845 C41.2@3995,845 ; C42.1@4045,855 4045,820 v1(4060,805) ; U2.5@4052.24,2857.4 v2(4106,2857.4) ; B2.3@4057.83,212.5 v2(4105,212.5) ; v1(4080,500) C51.1@4120,500 ; v1(4080,620) C48.1@4120,620 ; v1(4080,650) C47.1@4110,680 ; v1(4098,570) C49.1@4130,570 ; v2(4125,2620) R14.1@4125,2655 ; U4.2@4140,812.76 4140,775 v1(4145,770) ; v1(4180,660) C46.1@4180,700 ; R15.1@4180,2655 v2(4215,2655) ; 4201.98,2915 C13.1@4235,2915 ; 4235,2945.52 C13.1@4235,2915 ; C43.1@4245,845 4245,815 v2(4255,805) ; v1(4265,2705) C18.1@4305,2705 v1(4305,2660) ; 4268.02,2915 C13.1@4235,2915 ; 4276.98,2915 C14.1@4310,2915 ; 4310,2945.52 C14.1@4310,2915 ; v2(4340,235) 4362.5,212.5 B2.2@4412.17,212.5 ; 4343.02,2915 C14.1@4310,2915 ; 4351.98,2915 C15.1@4385,2915 ; U7.2@4356.52,530 4410,530 C50.1@4415,535 v1(4415,570) ; 4385,2945.52 C15.1@4385,2915 ; 4418.02,2915 C15.1@4385,2915 ; 4430.98,2905 C16.1@4455,2905 ; 4455,2930.52 C16.1@4455,2905 ; 4479.02,2905 C16.1@4455,2905
  BOTTOM w9: v2(930,2475) 939.37,2484.37 U11.A3@966.1,2484.37 ; U11.C1@1005.47,2523.74 v2(1005.47,2549.6) ; U11.D6@1025.16,2425.31 v4(1034.91,2415.56) ; U11.E8@1044.84,2385.94 v4(1035,2395.79) U11.E7@1044.84,2405.63 ; U11.E2@1044.84,2504.06 1049.88,2509.1 v4(1054.7,2513.9) ; U11.F7@1064.53,2405.63 v4(1074.38,2395.78) ; U11.G5@1084.21,2445 v4(1093.96,2435.25) ; U11.H9@1103.9,2366.26 1103.9,2366.1 v2(1125,2345) ; v2(3085,293) 3107.13,270.87 D13.B1@3110.13,270.87 ; D13.B2@3125.87,270.87 v2(3150,295) ; D12.B1@3177.13,272.87 3177.13,314.46 v2(3185.67,323) 3192.87,315.8 D12.B2@3192.87,272.87
  BOTTOM w10: v2(930,2475) 940.31,2464.69 U11.A4@966.1,2464.69 ; v2(940,2430) 955,2445 U11.A5@966.1,2445 ; v4(952.26,2537.36) 952.26,2536.48 965,2523.74 U11.A1@966.1,2523.74 ; U19.47@3588.74,728.58 v2(3640,728.58) ; U19.35@3671.42,468.74 v2(3671.42,520) ; v2(3789.53,760) U19.8@3789.53,811.26 ; v2(3885,551.42) U19.23@3931.26,551.42 ; v2(3885,610.47) U19.20@3931.26,610.47
  BOTTOM w15: v2(819.41,1509.41) U16.3@819.41,1559.57 ; v2(979.41,1515) U15.3@979.41,1559.57 ; v2(2150,1687) C115.1@2150,1715 ; v2(2170,1465) C125.1@2210,1465 ; C114.1@2205,1715 C113.1@2255,1715 v2(2255,1684) ; v3(2224,1263.51) U17.A3@2239.53,1247.99 ; v3(2255,1107) 2255,1106.53 U17.B8@2271.02,1090.51 ; v3(2255,1264) U17.B3@2271.02,1247.99 ; v2(2257,910) C138.1@2290,910 ; v3(2287,1326) 2287,1326.5 U17.C1@2302.52,1310.98 ; C112.1@2305,1715 C111.1@2360,1715 v2(2360,1685) ; v3(2319,1325.99) U17.D1@2334.02,1310.98 ; U13.G12@2324.02,2141.5 2340,2157.48 v3(2340,2159.84) ; C137.1@2335,910 v2(2372,910) ; C124.1@2345,1465 v2(2377,1465) ; U17.E9@2365.51,1059.02 2365.51,1042.49 v3(2374,1034) ; v3(2371,2095) 2387.01,2078.99 U13.J10@2387.01,2078.5 ; v3(2372.16,2187.84) U13.F10@2387.01,2172.99 ; v3(2381,1328) 2380,1328 U17.F1@2397.01,1310.98 ; U13.K10@2387.01,2047.01 v3(2404,2064) 2418.5,2049.5 U13.K9@2418.5,2047.01 ; U13.H10@2387.01,2110 v3(2404,2093) ; U13.G10@2387.01,2141.5 v3(2401.86,2156.35) ; v3(2403.65,2187.84) U13.F9@2418.5,2172.99 ; C136.1@2405,910 v2(2436,910) ; C110.1@2405,1715 C109.1@2450,1715 v2(2450,1686) ; U13.K8@2450,2047.01 v3(2464.85,2032.16) ; U13.F8@2450,2172.99 v3(2465,2157.99) ; U13.K7@2481.5,2047.01 v3(2496.35,2032.16) ; U13.F7@2481.5,2172.99 v3(2496.35,2187.84) ; v3(2498,2156.49) U13.G6@2512.99,2141.5 ; v3(2498.14,2095.15) U13.H6@2512.99,2110 ; v2(2510,910) C135.1@2540,910 ; U13.L6@2512.99,2015.51 v3(2527.84,2000.66) ; U13.K6@2512.99,2047.01 2497.84,2062.16 v3(2497.84,2063.65) 2512.69,2078.5 U13.J6@2512.99,2078.5 ; U13.F6@2512.99,2172.99 v3(2527.84,2187.84) ; v2(2524,1459) 2530,1465 C123.1@2555,1465 ; v3(2539,1263) 2539,1263.48 U17.L3@2554.49,1247.99 ; C108.1@2545,1715 v1(2574,1715) ; U17.L9@2554.49,1059.02 2554.49,1059.49 v3(2570,1075) ; v2(2571,910) C134.1@2600,910 ; U17.M1@2585.98,1310.98 2600,1325 v3(2600,1327) ; C107.1@2600,1715 v1(2629,1715) C106.1@2655,1715 ; U17.N1@2617.48,1310.98 2619.02,1310.98 v3(2634,1296) ; v3(2633,1107) 2640.53,1099.47 2640.53,1098.96 U17.P8@2648.98,1090.51 ; v2(2637,909) 2638,910 C133.1@2670,910 ; U13.F2@2638.98,2172.99 2654,2188.01 v3(2655,2188.01) ; U17.P3@2648.98,1247.99 2648.98,1242.02 v3(2671,1220) ; U13.N1@2670.47,1952.52 2672.48,1952.52 2686.99,1938.01 v3(2686.99,1937.67) ; U13.M1@2670.47,1984.02 v3(2692,1984.02) ; U17.R3@2680.47,1247.99 2693.48,1261 v3(2700,1261) ; C105.1@2695,1715 v1(2725,1715) C104.1@2755,1715 ; v2(2840,1064) C131.1@2840,1095 ; C128.1@2840,1145 2840,1181 v2(2845,1186) ; C126.1@2840,1250 2840,1282 2845,1287 v2(2845,1291) ; C99.1@2850,2130 v2(2881,2130) ; C97.1@2850,2180 2884,2180 v2(2885,2179) ; C88.1@2850,2230 2880,2230 v2(2884,2226) ; C86.1@2850,2280 2879,2280 v2(2883,2276) ; C83.1@2850,2325 v2(2880,2325) ; C80.1@2850,2375 v2(2880,2375) ; C103.1@2905,1790 v2(2935,1790) ; C102.1@2905,1850 2940,1850 2944,1854 v2(2944,1855) ; v2(2930,1666) 2930,1710 C116.2@2940,1720 2965,1745 v2(2965,1789) ; v2(2969,1978) 2969,1974 2940,1945 C101.2@2940,1930 v2(2985,1930) ; v2(3660,209) 3661,209 3683.82,186.18 CN16.5@3683.82,162.4
  BOTTOM w20: CN12.2@474.65,1462.72 v2(642.72,1462.72) ; CN12.3@474.65,1987.28 v2(645.03,1987.32) v2(645.03,1987.32) ; CN8.2@474.65,2132.72 v2(650,2132.72) ; CN8.3@474.65,2657.28 v2(655,2657.28) ; R102.2@710,2295 v2(710,2330) ; R111.1@715,1625 718,1625 v2(741,1602) ; v2(740,2400) C79.1@785,2400 ; v2(740,2455) C73.1@785,2455 ; v2(770,2505) C71.2@805,2505 ; v2(770,2965) R78.2@770,3000 ; C118.1@825,1695 v2(825,1730) ; v2(845,2605) C67.1@845,2645 ; v2(915,2145) C95.1@915,2185 ; v2(920,2690) 930,2680 C65.2@960,2680 ; v2(965,2145) C94.2@965,2185 ; C117.1@990,1695 v2(990,1727) ; v2(1013.1,3418.1) CN7.2@1097.48,3418.1 ; v2(1015,2145) C93.2@1015,2185 ; v2(1021.07,3303.93) CN7.3@1097.48,3303.93 ; C64.2@1055,2680 v2(1055,2715) ; v2(1065,2145) C92.2@1065,2185 ; C63.1@1105,2705 v2(1105,2750) ; v2(1115,2155) C91.2@1115,2195 ; 1120,2030.98 C100.1@1120,2055 ; 1120,2079.02 C100.1@1120,2055 ; R77.2@1140,3040 v2(1187.7,3040) ; 1145.52,2055 C100.1@1120,2055 ; 1170.5,1980.55 U14.1@1214.02,1980.55 ; v2(1175,2145) C90.2@1175,2185 ; 1214.02,2008.57 U14.1@1214.02,1980.55 ; 1257.54,1980.55 U14.1@1214.02,1980.55 ; C78.2@1285,2390 v2(1326,2390) ; C74.2@1285,2440 v2(1325,2440) ; v2(1515,2310) C85.1@1565,2310 ; v2(1695,2185) C96.1@1730,2185 ; CN6.3@1772.48,3303.93 v2(1854.93,3303.93) ; CN6.2@1772.48,3418.1 v2(1852.9,3418.1) ; U12.4@1880,2588.54 1880,2595 1898,2613 v2(1910,2613) ; v2(2039,1135) 2054,1150 C127.1@2075,1150 ; v2(2070,2601) 2070,2556 2093,2533 C72.1@2110,2533 2110,2595 v2(2103,2602) ; v2(2075,1071) C130.1@2075,1105 ; v2(2312,552.6) T5.2@2358.31,552.6 ; v2(2430,412) C148.2@2430,460 ; v2(2459,590) R131.2@2490,590 ; U21.2@2530,522.24 v2(2530,562) ; CN5.6@2689.61,2871.21 v2(2689.61,2925) ; v2(2787,2591) 2821,2591 C69.2@2835,2605 2819,2621 v2(2787,2621) ; v2(2805,670) 2810,675 C144.2@2810,700 ; C147.2@2815,515 v2(2851,515) ; CN5.9@2821.5,2871.21 v2(2821.5,2978) ; X4.2@2846.42,633.54 v2(2877.88,665.04) ; R108.1@2850,2045 v2(2882,2045) ; C76.1@2850,2425 v2(2880.86,2425) ; v2(2855,125) 2880,150 C156.1@2880,160 ; L8.1@2870,230 2870,205 v2(2885,190) ; C153.1@2880,285 v2(2880,330) ; v2(2910,496) R139.2@2910,530 ; C145.1@2910,630 v2(2910,665) ; v2(2994,2136.46) X2.2@3033.58,2136.46 ; v2(2995,2585) 2960,2585 C68.2@2940,2605 2955,2620 v2(2995,2620) ; C84.1@3020,2290 v2(3049,2290) ; C77.1@3020,2415 v2(3048,2415) ; C150.2@3045,415 3045.36,414.64 v2(3045.36,360) ; v2(3080,355) 3100,375 C149.1@3100,415 ; C98.1@3170,2140 v2(3205,2140) ; R124.1@3180,830 v2(3180,867) ; C154.1@3240,285 v2(3240,325) ; R133.1@3305,600 v2(3340,600) ; R128.1@3305,660 v2(3340,660) ; 3420,35.98 C157.1@3420,55 ; 3420,74.02 C157.1@3420,55 ; 3439.02,55 C157.1@3420,55 ; v2(3455,575) R135.1@3490,575 ; v2(3460,670) R127.1@3490,670 ; v2(3460,750) C143.1@3490,750 ; L3.1@3467.51,3306.92 3467.51,3342.51 v2(3468,3343) ; 3565.68,57.09 CN16.7@3597.2,57.09 3597.2,102.61 ; R122.1@3570,935 v2(3570,970) ; 3599.05,163.39 CN16.9@3636.57,163.39 3636.57,125.87 ; v2(3615,360) C151.1@3650,360 ; R121.1@3615,935 v2(3615,970) ; v2(3645,925) 3645,920 3665,900 C142.1@3675,900 ; 3657.91,57.09 CN16.11@3695.63,57.09 ; R149.1@3685,275 v2(3685,325) ; 3695.63,109.37 CN16.11@3695.63,57.09 ; 3774.37,109.37 CN16.10@3774.37,57.09 ; v2(3775,870) 3780,870 3800,890 C141.1@3800,900 ; 3812.09,57.09 CN16.10@3774.37,57.09 ; v2(3830,310) 3830,295 R146.1@3850,275 ; 3833.43,125.87 CN16.8@3833.43,163.39 3870.95,163.39 ; 3872.8,102.61 CN16.6@3872.8,57.09 3904.32,57.09 ; v2(3905,870) C140.2@3905,900 ; C132.1@3905,1000 v2(3930,975) ; v2(3970,214) 3979,205 C155.1@4005,205 ; R119.1@4000,940 v2(4030,940) ; SB16.1@4003.01,999.67 v2(4003.01,1045) ; v1(4045,475) 4045,455 4060,440 U22.4@4081.7,440 ; v1(4045,505) C146.1@4045,540 ; v1(4144,465) 4144,474 R140.2@4170,500 ; C66.2@4230,2705 4230,2690 v1(4250,2670) ; 4282.53,865.98 U18.1@4310.55,865.98 ; 4305,716.98 C129.1@4305,750 ; 4305,783.02 C129.1@4305,750 ; 4310.55,822.46 U18.1@4310.55,865.98 ; 4310.55,909.5 U18.1@4310.55,865.98 ; 4335.52,750 C129.1@4305,750 ; 4338.57,865.98 U18.1@4310.55,865.98 ; 4340.79,2516.23 T2.7@4340.79,2483.21 4408.81,2483.21 ; 4340.79,2548.62 T2.8@4340.79,2581.64 ; 4340.79,2614.66 T2.8@4340.79,2581.64 ; v2(4350,270) 4350,290 C152.1@4365,305 4380,290 v2(4380,270) ; 4366.98,900 C139.1@4400,900 ; 4400,869.48 C139.1@4400,900 ; 4408.81,2581.64 T2.8@4340.79,2581.64 ; v1(4426,2250) R105.1@4455,2250 ; 4433.02,900 C139.1@4400,900 ; 4456.98,875 JP1.2@4495,875 ; 4495,836.98 JP1.2@4495,875 ; 4495,913.02 JP1.2@4495,875 ; 4533.02,875 JP1.2@4495,875 ; v2(4575,1551.8) R113.1@4575,1590 ; R96.2@4785,2495 v2(4785,2556) ; CN16.11@3695.63,57.09 CN16.10@3774.37,57.09
  BOTTOM w40: T100.6@4187.95,2474.37 4244.37,2474.37 4253.21,2483.21 T2.7@4340.79,2483.21 ; T100.5@4187.95,2553.11 4218.11,2553.11 4246.64,2581.64 T2.8@4340.79,2581.64
  other v1: 4276,492 4324,492 4299,527 4278,569 4325,569 3055,575 3110,575 3165,575 3055,630 3110,630 3165,630 3055,685 3110,685 3165,685 3614,1811 3655,1812 3695,1812 3614,1851 3695,1851 3655,1852 3614,1891 3655,1891 3695,1891 4425,2495 4425,2520 4425,2560 4425,2605
  other v2: 2694,160 2108,161 2178,208 2762,210 3159,231 2695,255 3193,470 2693,744 2110,745 2178,794 2762,794 4350,810 4380,810 2692,840 4350,840 4380,840 3791,1852 3797,1933 1160,2065 1190,2065 1125,2100 1160,2100 1190,2100 4180,2930 4180,2966 4230,2970 4280,2970 4340,2970 4380,2970
PWR_ENN: R144.1 U19.28 U22.3 | length 418.9
  L4_SIG w4: v1(3809.21,519.21) 3809.21,480.79 3840,450 3967,450 v1(3978,439)
  BOTTOM w5: U19.28@3809.21,468.74 v1(3809.21,519.21) ; v1(3978,439) 3990,427 3990,400 R144.1@4005,385
  BOTTOM w10: R144.1@4005,385 4010,390 U22.3@4081.7,390
PWR_EXT: R135.2 R138.1 R141.1 U19.39 | length 155.4
  BOTTOM w10: R141.1@3530,480 R138.1@3530,530 R135.2@3530,575 3533.9,571.1 U19.39@3588.74,571.1
RD_N: R37.2 T4.8 U3.22 | length 493
  TOP w6.1: U3.22@3731.77,1859.84 3742.65,1859.84 3745,1862.19 3763.41,1862.19 3783.72,1882.5 3804.31,1882.5 v1(3809.81,1877) 3815.31,1882.5 3832.5,1882.5 R37.2@3845,1870
  BOTTOM w6.1: v1(3809.81,1877) 3804.31,1882.5 3782.5,1882.5 3760,1905 3760,1951.22 3823.78,2015 3898,2015 3908,2025 T4.8@3982.48,2025
RD_P: R35.2 T4.6 U3.23 | length 492.5
  TOP w6.1: U3.23@3731.77,1879.53 3742.66,1879.53 3745,1877.19 3757.19,1877.19 3777.5,1897.5 3804.31,1897.5 v1(3809.81,1903) 3815.31,1897.5 3832.5,1897.5 R35.2@3845,1910
  BOTTOM w6.1: v1(3809.81,1903) 3804.31,1897.5 3788.72,1897.5 3775,1911.22 3775,1945 3830,2000 3898,2000 3908,1990 3908,1952 3935,1925 T4.6@3982.48,1925
REFSEL0: R123.1 R124.2 U20.8 | length 105.2
  BOTTOM w5: U20.8@3178.9,725.28 3178.9,788.9 R124.2@3180,790 R123.1@3220,790
REFSEL1: R125.1 R128.2 U20.11 | length 99.9
  BOTTOM w5: U20.11@3205.28,659.53 3264.53,659.53 R128.2@3265,660 R125.1@3265,700
REFSEL2: R133.2 R137.1 U20.14 | length 99.9
  BOTTOM w5: U20.14@3205.28,600.47 3264.53,600.47 R133.2@3265,600 R137.1@3265,560
SCLK_MCLK: CN1.35 TP1.1 | length 128.3
  TOP w5: v1(3425,3340) 3440.78,3324.22 CN1.35@3440.78,3276.53
  BOTTOM w5: TP1.1@3405,3290 3405,3320 v1(3425,3340)
STLINK_RX: SB18.2 U19.13 | length 85.3
  BOTTOM w5: U19.13@3931.26,748.27 3953.27,748.27 3970,765 4007.98,765 SB18.2@4009.17,763.81
STLINK_TX: SB17.2 U19.12 | length 150.2
  BOTTOM w5: U19.12@3868.27,811.26 3966.26,811.26 3988.81,833.81 SB17.2@4009.17,833.81
STM_JTCK: CN4.2 U19.37 | length 1067.2
  TOP w5: v1(3670,550) 3700,550 3765,485 3830,485 3865.39,449.61 3865.39,370.28 3895,340.67 3895,258 3981,172 4288,172 CN4.2@4365,95
  BOTTOM w5: U19.37@3588.74,531.73 3651.73,531.73 v1(3670,550)
STM_JTMS: CN4.4 U19.34 | length 788
  TOP w5: v1(3700,520) 3750,470 3815,470 3850,435 3850,365 3880,335 3880,248 3971,157 4103,157 CN4.4@4165,95
  BOTTOM w5: U19.34@3691.1,468.74 3691.1,511.1 v1(3700,520)
STM_RST: C132.2 R118.1 SB16.2 U19.7 | length 373.2
  BOTTOM w5: U19.7@3769.84,811.26 3769.84,839.84 3780,850 3800,850 3830,880 3830,915 R118.1@3865,950 C132.2@3865,1000 3895,1030 3930,1030 3940,1020 3940,1005 3945,1000 3962.98,1000 SB16.2@3964.17,998.81
SWO: R92.1 SB21.2 | length 3745.7
  L4_SIG w4: v1(2468,2696) 2609,2696 2755,2550 3100,2550 3293,2357 3336.02,2357 3425,2268.02 3425,2099 3575,1949 3575,1788 3609,1754 3712,1754 3734,1732 3734,1201 3997,938 3997,606 4009,594 4009,428 3983,402 3925,402 3902,425 v1(3805,425)
  BOTTOM w5: R92.1@2405,2570 2405,2633 v1(2468,2696) ; SB21.2@3771.19,356.17 3788.17,356.17 3805,373 v1(3805,425)
T_JTCK: SB19.1 U19.15 U19.26 | length 381.4
  BOTTOM w5: U19.26@3848.58,468.74 3848.58,678.58 3878.9,708.9 U19.15@3931.26,708.9 3971.1,708.9 3984.67,695.33 SB19.1@4001.99,695.33
T_JTMS: R143.1 SB22.1 U19.27 | length 124.2
  BOTTOM w5: U19.27@3828.9,468.74 3828.9,406.1 R143.1@3830,405 3830,345
T_NRST: SB20.1 U19.18 | length 80.9
  BOTTOM w5: U19.18@3931.26,649.84 3955.16,649.84 3979.67,625.33 SB20.1@4001.99,625.33
T_SWDIO_IN: R143.2 U19.25 | length 64.5
  BOTTOM w5: U19.25@3868.27,468.74 3868.27,406.73 R143.2@3870,405
T_SWO: SB21.1 U19.31 | length 80.2
  BOTTOM w5: U19.31@3750.16,468.74 3750.16,423.18 SB21.1@3770.33,395.01
TD_N: R41.2 T4.3 U3.20 | length 475.1
  TOP w6.1: U3.20@3731.77,1820.47 3742.65,1820.47 3745,1822.82 3762.96,1822.82 3783.78,1802 3804.81,1802 v1(3809.81,1797) 3815.31,1802.5 3832.5,1802.5 R41.2@3845,1790
  BOTTOM w6.1: v1(3809.81,1797) 3804.31,1802.5 3793.72,1802.5 3785,1793.78 3785,1757.22 3834.22,1708 3892,1708 3901,1717 3901,1768 3908,1775 T4.3@3982.48,1775
TD_P: R39.2 T4.1 U3.21 | length 475.1
  TOP w6.1: U3.21@3731.77,1840.16 3740,1840.16 3742.34,1837.82 3769.18,1837.82 3790,1817 3803.81,1817 v1(3809.81,1823) 3815.31,1817.5 3832.5,1817.5 R39.2@3845,1830
  BOTTOM w6.1: v1(3809.81,1823) 3804.31,1817.5 3787.5,1817.5 3770,1800 3770,1751 3828,1693 3927,1693 3945,1675 T4.1@3982.48,1675
USB_HS_N: CN15.2 D13.A1 U20.19 | length 431.1
  TOP w6.1: v1(3104,225) 3109.5,230.5 3109.5,334.5 3141.87,366.87 3141.87,465.31 v1(3136.37,470.81)
  BOTTOM w6.1: CN15.2@3105.28,162.8 3105.28,185 3110.57,190.29 3110.57,218.43 v1(3104,225) 3110.57,231.57 3110.57,254.69 D13.A1@3110.13,255.13 ; v1(3136.37,470.81) 3141.87,476.31 3141.87,505.35 3139.53,507.69 U20.19@3139.53,534.72
USB_HS_P: CN15.3 D13.A2 U20.18 | length 429.3
  TOP w6.1: v1(3130,225) 3124.5,230.5 3124.5,328.28 3156.87,360.65 3156.87,465.31 v1(3162.37,470.81)
  BOTTOM w6.1: D13.A2@3125.87,255.13 3125.57,254.83 3125.57,229.43 v1(3130,225) 3125.57,220.57 3125.57,185 3130.87,179.7 CN15.3@3130.87,162.8 ; U20.18@3159.21,534.72 3159.21,507.69 3156.87,505.35 3156.87,476.31 v1(3162.37,470.81)
USB_RENUMN: R145.2 U19.38 | length 489
  TOP w5: v1(3635,551.42) 3635,525 3705,455 3805,455 3835,425 3835,360 3860,335 v1(3860,310)
  BOTTOM w5: U19.38@3588.74,551.42 v1(3635,551.42) ; v1(3860,310) R145.2@3895,275
USB_STLK_N: CN16.2 U19.32 | length 339.8
  BOTTOM w6.1: U19.32@3730.47,468.74 3730.47,432.21 3728.13,429.87 3728.13,347.87 3768,308 3768,259 3745,236 3745,218 3755.3,207.7 3755.3,189 3760.59,183.71 CN16.2@3760.59,162.4
USB_STLK_P: CN16.3 R148.1 U19.33 | length 344
  BOTTOM w6.1: U19.33@3710.79,468.74 3710.79,432.21 3713.13,429.87 3713.13,341.65 3753,301.78 3753,265.22 3725,237.22 R148.1@3725,235 3725,231 3730,226 3730,211.78 3740.3,201.48 3740.3,189 3735,183.7 CN16.3@3735,162.4
USD_D2: CN5.1 R83.1 R93.1 | length 377.1
  BOTTOM w5: R93.1@2355,2570 2355,2736 2424,2805 R83.1@2470,2805 2473.07,2808.07 CN5.1@2473.07,2871.21
VDD: C68.1 C69.1 C76.2 C80.2 C83.2 C86.2 C88.2 C97.2 C99.2 C104.2 C105.2 C106.2 C107.2 C108.2 C109.2 C110.2 C111.2 C112.2 C113.2 C114.2 C115.2 JP4.1 L6.1 R109.1 U13.C1 U13.E7 U13.E8 U13.E9 U13.E10 U13.F4 U13.F5 U13.F11 U13.G5 U13.G11 U13.H5 U13.H11 U13.J5 U13.J11 U13.K5 U13.K11 U13.L7 U13.L8 U13.L9 U13.L10 | length 1600.3
  BOTTOM w15: v1(2144,1784) 2150,1778 C115.2@2150,1755 ; C114.2@2205,1755 C113.2@2255,1755 2255,1769 v1(2267,1781) ; C112.2@2305,1755 C111.2@2360,1755 2362,1755 2367,1760 v1(2367,1785) ; v3(2340.66,2187.84) U13.F11@2355.51,2172.99 ; U13.K11@2355.51,2047.01 2371,2062.5 v3(2371,2063) U13.J11@2355.51,2078.5 ; U13.H11@2355.51,2110 U13.G11@2355.51,2141.5 2362,2147.99 v3(2372,2158) ; v3(2372.16,2000.66) U13.L10@2387.01,2015.51 ; U13.E10@2387.01,2204.49 2401.86,2219.34 v3(2403.65,2219.34) U13.E9@2418.5,2204.49 ; v3(2403.65,2000.66) U13.L9@2418.5,2015.51 ; C110.2@2405,1755 C109.2@2450,1755 2450,1780 v1(2452,1782) ; U13.L8@2450,2015.51 v3(2464.85,2000.66) ; U13.E8@2450,2204.49 2465,2189.49 v3(2465,2189) ; U13.L7@2481.5,2015.51 v3(2496.35,2000.66) ; U13.E7@2481.5,2204.49 v3(2496.35,2219.34) ; v3(2529,2032) 2544.01,2047.01 U13.K5@2544.49,2047.01 ; v3(2529,2157.5) U13.F5@2544.49,2172.99 ; v3(2529.34,2063.65) 2529.64,2063.65 U13.J5@2544.49,2078.5 ; v3(2529.34,2095.15) 2529.64,2095.15 U13.H5@2544.49,2110 ; U13.G5@2544.49,2141.5 v3(2559.34,2156.35) ; C108.2@2545,1755 v1(2574,1755) ; U13.F4@2575.98,2172.99 v3(2590.83,2187.84) ; C107.2@2600,1755 v1(2629,1755) C106.2@2655,1755 ; U13.C1@2670.47,2267.48 2687.48,2267.48 v3(2699,2279) ; C105.2@2695,1755 v1(2725,1755) C104.2@2755,1755 ; v1(2778,2130) C99.2@2810,2130 ; v1(2778,2180) C97.2@2810,2180 ; v1(2778,2230) C88.2@2810,2230 ; v1(2780,2280) C86.2@2810,2280 ; v1(2780,2325) C83.2@2810,2325 ; v1(2780,2375) C80.2@2810,2375 ; v1(3020,1655) L6.1@3020,1695
  BOTTOM w20: 1636.98,2025 JP4.1@1675,2025 ; 1645.51,1898.48 R109.1@1645.51,1930 ; 1645.51,1961.52 R109.1@1645.51,1930 ; 1675,1986.98 JP4.1@1675,2025 ; 1675,2063.02 JP4.1@1675,2025 ; 1678.03,1930 R109.1@1645.51,1930 ; 1713.02,2025 JP4.1@1675,2025 ; v2(2780,2425) C76.2@2810,2425 ; v2(2785,2515) 2815,2515 C69.1@2835,2495 2866,2464 v2(2885,2464) ; v2(2885,2495) C68.1@2940,2495 v2(2990,2495)
  other v2: 1640,1830 1670,1830 1700,1830 1640,1860 1670,1860 1700,1860
VDDA: C103.2 C116.1 L6.2 R110.1 U13.R1 | length 620.4
  BOTTOM w20: U13.R1@2670.47,1889.53 2687,1873 2770,1873 2795,1848 2795,1755 C116.1@2830,1720 2865,1755 C103.2@2865,1790 2865,1800 2885,1820 2965.51,1820 2975,1829.49 R110.1@3020,1829.49 L6.2@3020,1755
VIN: C129.2 CN11.8 U18.3 | length 1634.5
  L4_SIG w20: v2(4080.51,1167.49) 4080.51,879.49 4105,855 4105,756 v2(4148,713)
  BOTTOM w20: CN11.8@3305.8,1567.7 3661.5,1212 4036,1212 v2(4080.51,1167.49) ; 4129.45,822.46 U18.3@4129.45,865.98 ; 4129.45,909.5 U18.3@4129.45,865.98 ; 4157.47,865.98 U18.3@4129.45,865.98 ; 4204.48,750 C129.2@4235,750 ; 4235,716.98 C129.2@4235,750 ; 4235,783.02 C129.2@4235,750
VREF+: C85.2 C101.1 C102.2 R98.2 R110.2 U13.P1 | length 4432
  L4_SIG w20: v2(1595,930) 1595,1345 1475,1465 1475,2160 1620,2305 v2(1635,2305)
  BOTTOM w20: v2(1595,930) 2185,930 2240,875 2686,875 2746,935 2880,935 3070,1125 3070,1870 3049.49,1890.51 R110.2@3020,1890.51 3011.49,1882 2885,1882 2865,1862 C102.2@2865,1850 2850,1850 2830,1870 C101.1@2830,1930 2780,1930 2765,1915 2676.49,1915 U13.P1@2670.47,1921.02 ; R98.2@1605,2355 C85.2@1605,2310 1610,2305 v2(1635,2305)
pads on no net: "CN1. " "CN5. " "CN6. " "CN7. " CN1.2 CN1.20 CN1.22 CN1.24 CN1.25 CN1.26 CN1.28 CN1.30 CN1.31 CN1.32 CN1.33 CN1.34 CN1.38 CN1.41 CN1.42 CN1.43 CN1.46 CN1.48 CN1.50 CN1.51 CN1.52 CN1.54 CN1.55 CN1.56 CN1.58 CN1.59 CN5.11 CN5.12 CN5.13 CN5.14 CN6.5 CN6.7 CN7.5 CN7.7 T4.4 T4.5 T4.12 T4.13 U2.1 U2.2 U3.4 U7.3 U7.5 U11.A6 U11.A8 U11.B4 U11.B5 U11.B8 U11.C4 U11.C5 U11.C7 U11.C8 U11.E1 U11.E5 U11.F4 U11.F5 U11.F6 U11.F8 U11.F9 U11.G4 U11.H2 U11.H3 U11.H4 U11.H5 U12.9 U15.1 U16.1 U17.E7 U17.H3 U17.H7 U17.K2 U17.K3 U19.4 U19.11 U19.14 U19.16 U19.17 U19.19 U19.21 U19.22 U19.29 U19.40 U19.41 U19.42 U19.43 U19.45 U19.46 U20.12 U20.15 U20.16 U20.25 U250.9
copper on no net: | length 384679.8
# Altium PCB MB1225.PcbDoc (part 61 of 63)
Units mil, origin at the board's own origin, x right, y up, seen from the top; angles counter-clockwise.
Board outline 5000 x 3464.56 mil, 6 copper layers (TOP, L2_GND, L3_VCC, L4_SIG, L5_GND, BOTTOM), stack 62.2 mil thick; 452 components, 378 nets, 1968 pads, 949 vias.

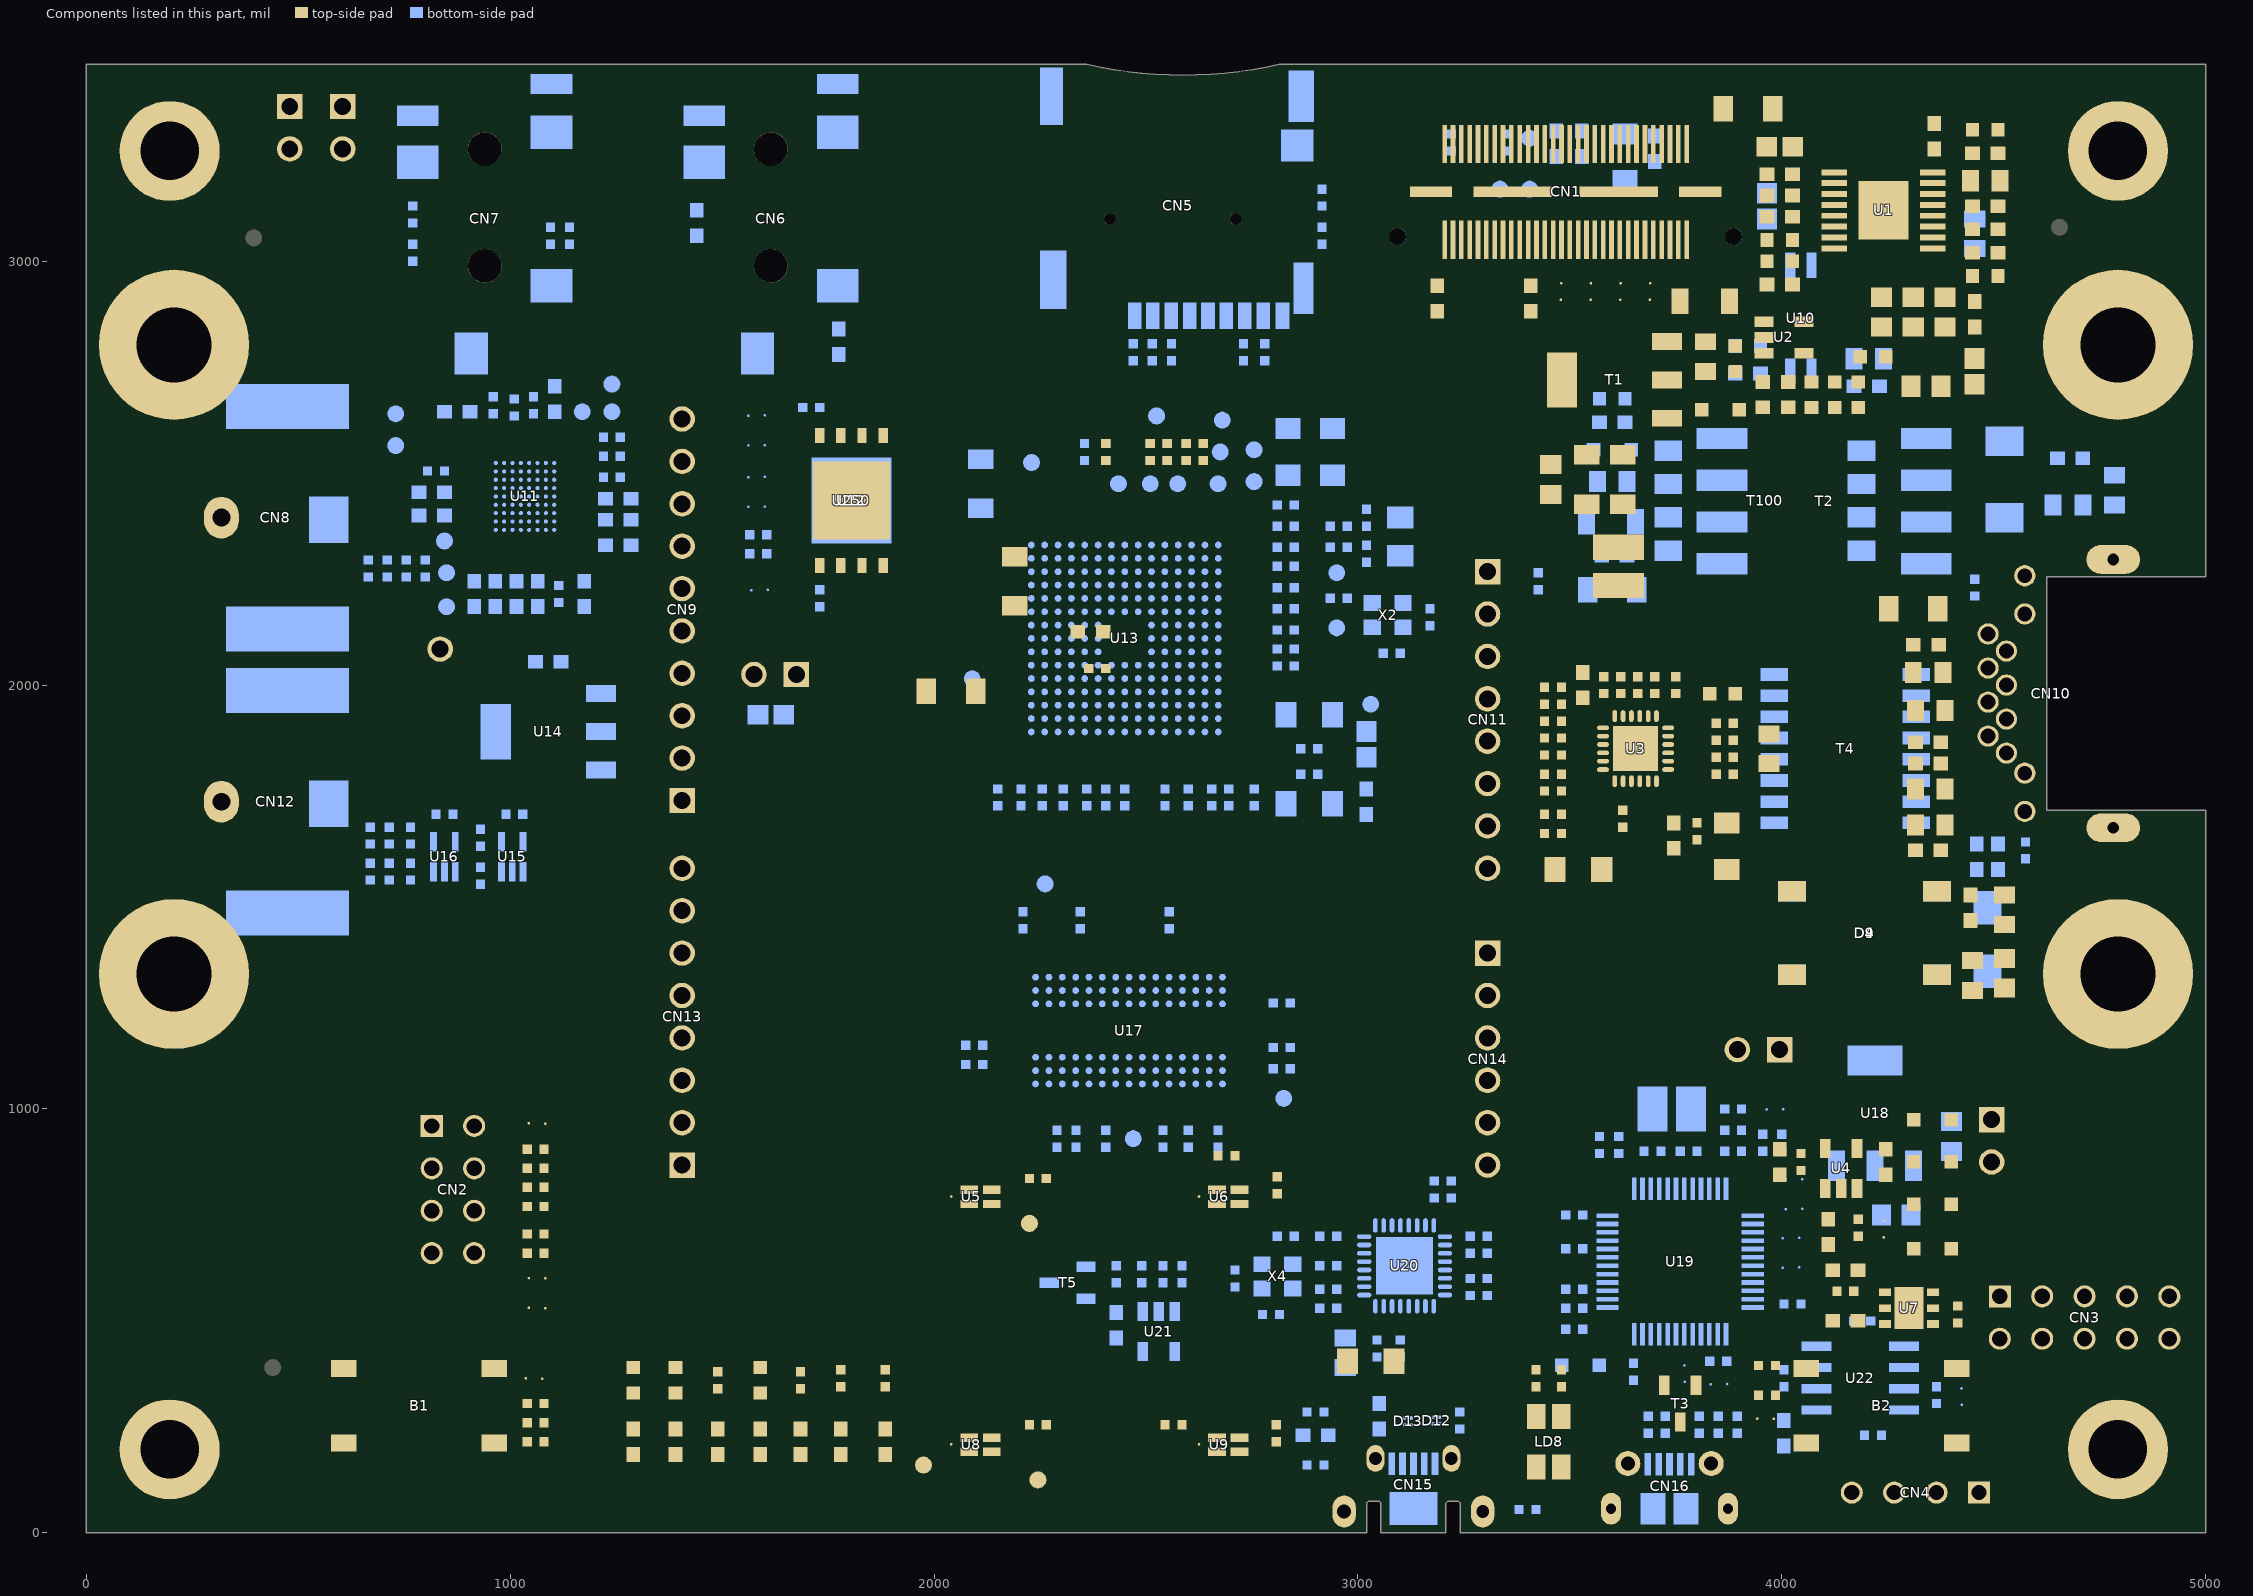
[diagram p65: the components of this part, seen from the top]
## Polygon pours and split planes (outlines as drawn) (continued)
no net on MB988 (solid): 1726.97,6530.31 1805.71,6530.31 1805.71,6569.68 1726.97,6569.68 1726.97,6530.31
no net on MB988 (solid): 1726.97,6230.31 1805.71,6230.31 1805.71,6269.68 1726.97,6269.68 1726.97,6230.31
no net on MB988 (solid): 1726.97,6330.31 1805.71,6330.31 1805.71,6369.68 1726.97,6369.68 1726.97,6330.31
no net on MB988 (solid): 1726.97,6430.31 1805.71,6430.31 1805.71,6469.68 1726.97,6469.68 1726.97,6430.31
no net on MB988 (solid): 1463.84,6550 1713.84,6550 1713.84,6600 1463.84,6600 1463.84,6550
no net on MB988 (solid): 1413.84,6600 1413.84,6550 1463.84,6550 1463.84,6600 1413.84,6600
no net on MB988 (solid): 1323.84,6570 1323.84,6530 1398.84,6530 1398.84,6570 1323.84,6570
no net on MB988 (solid): 1321.97,6228.35 1400.71,6228.35 1400.71,6271.65 1321.97,6271.65 1321.97,6228.35
no net on MB988 (solid): 1321.97,6328.35 1400.71,6328.35 1400.71,6371.65 1321.97,6371.65 1321.97,6328.35
no net on MB988 (solid): 1321.97,6428.35 1400.71,6428.35 1400.71,6471.65 1321.97,6471.65 1321.97,6428.35
no net on MB988 (solid): 0,6100 660,6100 660,6800 0,6800 0,6100
no net on DXF_0731 (solid): 3459.78,5620.18 3487.62,5648.02 3418.02,5717.62 3390.18,5689.78 3459.78,5620.18
no net on DXF_0731 (solid): 3459.78,5614.52 3493.27,5648.02 3418.02,5723.27 3384.52,5689.78 3459.78,5614.52
no net on DXF_0731 (solid): 3487.62,5051.98 3459.78,5079.82 3390.18,5010.22 3418.02,4982.38 3487.62,5051.98
no net on DXF_0731 (solid): 3493.27,5051.98 3459.78,5085.48 3384.52,5010.22 3418.02,4976.73 3493.27,5051.98
no net on DXF_0731 (solid): 2849.82,5689.78 2821.98,5717.62 2752.38,5648.02 2780.22,5620.18 2849.82,5689.78
no net on DXF_0731 (solid): 2855.48,5689.78 2821.98,5723.27 2746.73,5648.02 2780.22,5614.52 2855.48,5689.78
no net on DXF_0731 (solid): 2821.98,4982.38 2849.82,5010.22 2780.22,5079.82 2752.38,5051.98 2821.98,4982.38
no net on DXF_0731 (solid): 2821.98,4976.73 2855.48,5010.22 2780.22,5085.48 2746.73,5051.98 2821.98,4976.73
no net on DXF_0731 (solid): 1961.38,273.28 2010.88,223.78 2039.17,252.07 1989.67,301.56 1961.38,273.28
no net on DXF_0731 (solid): 1955.73,273.28 2010.88,218.13 2044.82,252.07 1989.67,307.22 1955.73,273.28
no net on DXF_0731 (solid): 1935.1,419.6 1984.6,370.1 2012.89,398.39 1963.39,447.89 1935.1,419.6
no net on DXF_0731 (solid): 1929.45,419.6 1984.6,364.45 2018.54,398.39 1963.39,453.54 1929.45,419.6
no net on DXF_0731 (solid): 1922.41,234.31 1971.91,184.81 2000.19,213.09 1950.69,262.59 1922.41,234.31
no net on DXF_0731 (solid): 1916.75,234.31 1971.91,179.15 2005.85,213.09 1950.69,268.25 1916.75,234.31
no net on DXF_0731 (solid): 1883.44,195.33 1932.93,145.83 1961.22,174.12 1911.72,223.62 1883.44,195.33
no net on DXF_0731 (solid): 1877.78,195.33 1932.93,140.18 1966.87,174.12 1911.72,229.27 1877.78,195.33
no net on DXF_0731 (solid): 1788.78,445.88 1838.28,396.38 1866.57,424.67 1817.07,474.17 1788.78,445.88
no net on DXF_0731 (solid): 1783.13,445.88 1838.28,390.73 1872.22,424.67 1817.07,479.82 1783.13,445.88
no net on DXF_0731 (solid): 1749.81,406.91 1799.31,357.41 1827.59,385.69 1778.09,435.19 1749.81,406.91
no net on DXF_0731 (solid): 1744.15,406.91 1799.31,351.75 1833.25,385.69 1778.09,440.85 1744.15,406.91
no net on DXF_0731 (solid): 1710.83,367.93 1760.33,318.43 1788.62,346.72 1739.12,396.22 1710.83,367.93
no net on DXF_0731 (solid): 1733.58,218.08 1783.08,168.58 1811.36,196.86 1761.86,246.36 1733.58,218.08
no net on DXF_0731 (solid): 1727.92,218.08 1783.08,162.92 1817.02,196.86 1761.86,252.02 1727.92,218.08
no net on DXF_0731 (solid): 1705.18,367.93 1760.33,312.78 1794.27,346.72 1739.12,401.87 1705.18,367.93
no net on DXF_0731 (solid): 7.03,12.17 7.12,12.17 7.12,12.22 7.03,12.22 7.03,12.17
no net on DXF_0731 (solid): 7.03,12.17 7.11,12.17 7.11,12.22 7.03,12.22 7.03,12.17
no net on DXF_0731 (solid): 7.03,12.27 7.12,12.27 7.12,12.32 7.03,12.32 7.03,12.27
no net on DXF_0731 (solid): 7.03,12.27 7.11,12.27 7.11,12.32 7.03,12.32 7.03,12.27
no net on DXF_0731 (solid): 7.03,12.37 7.12,12.37 7.12,12.42 7.03,12.42 7.03,12.37
no net on DXF_0731 (solid): 7.03,12.37 7.11,12.37 7.11,12.42 7.03,12.42 7.03,12.37
no net on DXF_0731 (solid): 7.03,12.52 7.03,12.47 7.11,12.47 7.11,12.52 7.03,12.52
no net on DXF_0731 (solid): 7.04,12.52 7.04,12.48 7.11,12.48 7.11,12.52 7.04,12.52
no net on DXF_0731 (solid): 7.43,12.17 7.52,12.17 7.52,12.22 7.43,12.22 7.43,12.17
no net on DXF_0731 (solid): 7.44,12.18 7.52,12.18 7.52,12.21 7.44,12.21 7.44,12.18
no net on DXF_0731 (solid): 7.43,12.27 7.52,12.27 7.52,12.32 7.43,12.32 7.43,12.27
no net on DXF_0731 (solid): 7.44,12.28 7.52,12.28 7.52,12.31 7.44,12.31 7.44,12.28
no net on DXF_0731 (solid): 7.43,12.37 7.52,12.37 7.52,12.42 7.43,12.42 7.43,12.37
no net on DXF_0731 (solid): 7.44,12.38 7.52,12.38 7.52,12.41 7.44,12.41 7.44,12.38
no net on DXF_0731 (solid): 7.43,12.47 7.52,12.47 7.52,12.52 7.43,12.52 7.43,12.47
no net on DXF_0731 (solid): 7.44,12.48 7.52,12.48 7.52,12.51 7.44,12.51 7.44,12.48
no net on DXF_0731 (solid): 7.13,12.55 7.13,12.5 7.18,12.5 7.18,12.55 7.13,12.55
no net on DXF_0731 (solid): 10.86,10.01 10.86,9.97 10.96,9.97 10.96,10.01 10.86,10.01
no net on DXF_0731 (solid): 10.86,10 10.86,9.98 10.96,9.98 10.96,10 10.86,10
no net on DXF_0731 (solid): 10.86,10.06 10.86,10.02 10.96,10.02 10.96,10.06 10.86,10.06
no net on DXF_0731 (solid): 10.86,10.05 10.86,10.03 10.96,10.03 10.96,10.05 10.86,10.05
no net on DXF_0731 (solid): 10.86,10.11 10.86,10.07 10.96,10.07 10.96,10.11 10.86,10.11
no net on DXF_0731 (solid): 10.86,10.1 10.86,10.08 10.96,10.08 10.96,10.1 10.86,10.1
no net on DXF_0731 (solid): 10.86,10.16 10.86,10.12 10.96,10.12 10.96,10.16 10.86,10.16
no net on DXF_0731 (solid): 10.86,10.15 10.86,10.13 10.96,10.13 10.96,10.15 10.86,10.15
no net on DXF_0731 (solid): 10.69,10.01 10.69,9.97 10.79,9.97 10.79,10.01 10.69,10.01
no net on DXF_0731 (solid): 10.69,10 10.69,9.98 10.79,9.98 10.79,10 10.69,10
no net on DXF_0731 (solid): 10.69,10.06 10.69,10.02 10.79,10.02 10.79,10.06 10.69,10.06
no net on DXF_0731 (solid): 10.69,10.05 10.69,10.03 10.79,10.03 10.79,10.05 10.69,10.05
no net on DXF_0731 (solid): 10.69,10.11 10.69,10.07 10.79,10.07 10.79,10.11 10.69,10.11
no net on DXF_0731 (solid): 10.69,10.1 10.69,10.08 10.79,10.08 10.79,10.1 10.69,10.1
no net on DXF_0731 (solid): 10.86,10.21 10.86,10.17 10.96,10.17 10.96,10.21 10.86,10.21
no net on DXF_0731 (solid): 10.86,10.2 10.86,10.18 10.96,10.18 10.96,10.2 10.86,10.2
no net on DXF_0731 (solid): 10.69,10.21 10.69,10.17 10.79,10.17 10.79,10.21 10.69,10.21
no net on DXF_0731 (solid): 10.69,10.2 10.69,10.18 10.79,10.18 10.79,10.2 10.69,10.2
no net on DXF_0731 (solid): 10.69,10.16 10.69,10.12 10.79,10.12 10.79,10.16 10.69,10.16
no net on DXF_0731 (solid): 10.69,10.15 10.69,10.13 10.79,10.13 10.79,10.15 10.69,10.15
no net on DXF_0731 (solid): 10.86,9.96 10.86,9.92 10.96,9.92 10.96,9.96 10.86,9.96
no net on DXF_0731 (solid): 10.86,9.95 10.86,9.93 10.96,9.93 10.96,9.95 10.86,9.95
no net on DXF_0731 (solid): 10.69,9.96 10.69,9.92 10.79,9.92 10.79,9.96 10.69,9.96
no net on DXF_0731 (solid): 10.69,9.95 10.69,9.93 10.79,9.93 10.79,9.95 10.69,9.95
no net on DXF_0731 (solid): 10.86,9.91 10.86,9.87 10.96,9.87 10.96,9.91 10.86,9.91
no net on DXF_0731 (solid): 10.86,9.9 10.86,9.88 10.96,9.88 10.96,9.9 10.86,9.9
no net on DXF_0731 (solid): 10.69,9.91 10.69,9.87 10.79,9.87 10.79,9.91 10.69,9.91
no net on DXF_0731 (solid): 10.69,9.9 10.69,9.88 10.79,9.88 10.79,9.9 10.69,9.9
no net on DXF_0731 (solid): 10.86,9.86 10.86,9.82 10.96,9.82 10.96,9.86 10.86,9.86
no net on DXF_0731 (solid): 10.86,9.85 10.86,9.83 10.96,9.83 10.96,9.85 10.86,9.85
no net on DXF_0731 (solid): 10.69,9.86 10.69,9.82 10.79,9.82 10.79,9.86 10.69,9.86
no net on DXF_0731 (solid): 10.69,9.85 10.69,9.83 10.79,9.83 10.79,9.85 10.69,9.85
no net on DXF_0731 (solid): 10.86,9.81 10.86,9.77 10.96,9.77 10.96,9.81 10.86,9.81
no net on DXF_0731 (solid): 10.86,9.8 10.86,9.78 10.96,9.78 10.96,9.8 10.86,9.8
no net on DXF_0731 (solid): 10.69,9.81 10.69,9.77 10.79,9.77 10.79,9.81 10.69,9.81
no net on DXF_0731 (solid): 10.69,9.8 10.69,9.78 10.79,9.78 10.79,9.8 10.69,9.8
no net on DXF_0731 (solid): 10.86,9.76 10.86,9.72 10.96,9.72 10.96,9.76 10.86,9.76
no net on DXF_0731 (solid): 10.86,9.75 10.86,9.73 10.96,9.73 10.96,9.75 10.86,9.75
no net on DXF_0731 (solid): 10.69,9.76 10.69,9.72 10.79,9.72 10.79,9.76 10.69,9.76
no net on DXF_0731 (solid): 10.69,9.75 10.69,9.73 10.79,9.73 10.79,9.75 10.69,9.75
no net on DXF_0731 (solid): 11.89,7.42 11.89,7.46 11.83,7.46 11.83,7.42 11.89,7.42
no net on DXF_0731 (solid): 11.89,7.43 11.89,7.45 11.84,7.45 11.84,7.43 11.89,7.43
no net on DXF_0731 (solid): 12.02,7.42 12.02,7.46 11.96,7.46 11.96,7.42 12.02,7.42
no net on DXF_0731 (solid): 12.02,7.43 12.02,7.45 11.96,7.45 11.96,7.43 12.02,7.43
no net on DXF_0731 (solid): 11.89,7.38 11.89,7.42 11.83,7.42 11.83,7.38 11.89,7.38
no net on DXF_0731 (solid): 11.89,7.39 11.89,7.41 11.84,7.41 11.84,7.39 11.89,7.39
no net on DXF_0731 (solid): 12.02,7.38 12.02,7.42 11.96,7.42 11.96,7.38 12.02,7.38
no net on DXF_0731 (solid): 12.02,7.39 12.02,7.41 11.96,7.41 11.96,7.39 12.02,7.39
no net on DXF_0731 (solid): 11.89,7.34 11.89,7.38 11.83,7.38 11.83,7.34 11.89,7.34
no net on DXF_0731 (solid): 11.89,7.35 11.89,7.37 11.84,7.37 11.84,7.35 11.89,7.35
no net on DXF_0731 (solid): 12.02,7.34 12.02,7.38 11.96,7.38 11.96,7.34 12.02,7.34
no net on DXF_0731 (solid): 12.02,7.35 12.02,7.37 11.96,7.37 11.96,7.35 12.02,7.35
no net on DXF_0731 (solid): 11.89,7.3 11.89,7.34 11.83,7.34 11.83,7.3 11.89,7.3
no net on DXF_0731 (solid): 11.89,7.31 11.89,7.33 11.84,7.33 11.84,7.31 11.89,7.31
no net on DXF_0731 (solid): 12.02,7.3 12.02,7.34 11.96,7.34 11.96,7.3 12.02,7.3
no net on DXF_0731 (solid): 12.02,7.31 12.02,7.33 11.96,7.33 11.96,7.31 12.02,7.31
no net on DXF_0731 (solid): 11.89,7.27 11.89,7.3 11.83,7.3 11.83,7.27 11.89,7.27
no net on DXF_0731 (solid): 11.89,7.27 11.89,7.29 11.84,7.29 11.84,7.27 11.89,7.27
no net on DXF_0731 (solid): 12.02,7.27 12.02,7.3 11.96,7.3 11.96,7.27 12.02,7.27
no net on DXF_0731 (solid): 12.02,7.27 12.02,7.29 11.96,7.29 11.96,7.27 12.02,7.27
no net on DXF_0731 (solid): 11.89,7.23 11.89,7.26 11.83,7.26 11.83,7.23 11.89,7.23
no net on DXF_0731 (solid): 11.89,7.23 11.89,7.25 11.84,7.25 11.84,7.23 11.89,7.23
no net on DXF_0731 (solid): 12.02,7.23 12.02,7.26 11.96,7.26 11.96,7.23 12.02,7.23
no net on DXF_0731 (solid): 12.02,7.23 12.02,7.25 11.96,7.25 11.96,7.23 12.02,7.23
no net on DXF_0731 (solid): 11.89,7.19 11.89,7.22 11.83,7.22 11.83,7.19 11.89,7.19
no net on DXF_0731 (solid): 11.89,7.19 11.89,7.21 11.84,7.21 11.84,7.19 11.89,7.19
no net on DXF_0731 (solid): 12.02,7.19 12.02,7.22 11.96,7.22 11.96,7.19 12.02,7.19
no net on DXF_0731 (solid): 12.02,7.19 12.02,7.21 11.96,7.21 11.96,7.19 12.02,7.19
no net on DXF_0731 (solid): 11.89,7.15 11.89,7.18 11.83,7.18 11.83,7.15 11.89,7.15
no net on DXF_0731 (solid): 11.89,7.15 11.89,7.18 11.84,7.18 11.84,7.15 11.89,7.15
no net on DXF_0731 (solid): 12.02,7.15 12.02,7.18 11.96,7.18 11.96,7.15 12.02,7.15
no net on DXF_0731 (solid): 11.89,7.11 11.89,7.14 11.83,7.14 11.83,7.11 11.89,7.11
no net on DXF_0731 (solid): 11.89,7.11 11.89,7.14 11.84,7.14 11.84,7.11 11.89,7.11
no net on DXF_0731 (solid): 12.02,7.11 12.02,7.14 11.96,7.14 11.96,7.11 12.02,7.11
no net on DXF_0731 (solid): 11.89,7.07 11.89,7.1 11.83,7.1 11.83,7.07 11.89,7.07
no net on DXF_0731 (solid): 11.89,7.07 11.89,7.1 11.84,7.1 11.84,7.07 11.89,7.07
no net on DXF_0731 (solid): 12.02,7.07 12.02,7.1 11.96,7.1 11.96,7.07 12.02,7.07
no net on DXF_0731 (solid): 12.02,7.03 12.02,7.06 11.96,7.06 11.96,7.03 12.02,7.03
no net on DXF_0731 (solid): 12.01,7.03 12.01,7.06 11.96,7.06 11.96,7.03 12.01,7.03
no net on DXF_0731 (solid): 11.89,7.03 11.89,7.06 11.83,7.06 11.83,7.03 11.89,7.03
no net on DXF_0731 (solid): 12.02,6.99 12.02,7.02 11.96,7.02 11.96,6.99 12.02,6.99
no net on DXF_0731 (solid): 12.01,6.99 12.01,7.02 11.96,7.02 11.96,6.99 12.01,6.99
no net on DXF_0731 (solid): 11.89,6.99 11.89,7.02 11.83,7.02 11.83,6.99 11.89,6.99
no net on DXF_0731 (solid): 12.02,6.95 12.02,6.98 11.96,6.98 11.96,6.95 12.02,6.95
no net on DXF_0731 (solid): 12.01,6.95 12.01,6.98 11.96,6.98 11.96,6.95 12.01,6.95
no net on DXF_0731 (solid): 11.89,6.95 11.89,6.98 11.83,6.98 11.83,6.95 11.89,6.95
no net on DXF_0731 (solid): 12.02,6.91 12.02,6.94 11.96,6.94 11.96,6.91 12.02,6.91
no net on DXF_0731 (solid): 12.01,6.92 12.01,6.94 11.96,6.94 11.96,6.92 12.01,6.92
no net on DXF_0731 (solid): 11.89,6.91 11.89,6.94 11.83,6.94 11.83,6.91 11.89,6.91
no net on DXF_0731 (solid): 11.89,6.92 11.89,6.94 11.83,6.94 11.83,6.92 11.89,6.92
no net on DXF_0731 (solid): 12.02,6.87 12.02,6.9 11.96,6.9 11.96,6.87 12.02,6.87
no net on DXF_0731 (solid): 12.01,6.88 12.01,6.9 11.96,6.9 11.96,6.88 12.01,6.88
no net on DXF_0731 (solid): 11.89,6.87 11.89,6.9 11.83,6.9 11.83,6.87 11.89,6.87
no net on DXF_0731 (solid): 11.89,6.88 11.89,6.9 11.83,6.9 11.83,6.88 11.89,6.88
no net on DXF_0731 (solid): 12.02,6.71 12.02,6.75 11.96,6.75 11.96,6.71 12.02,6.71
no net on DXF_0731 (solid): 12.01,6.72 12.01,6.74 11.96,6.74 11.96,6.72 12.01,6.72
no net on DXF_0731 (solid): 12.02,6.67 12.02,6.71 11.96,6.71 11.96,6.67 12.02,6.67
no net on DXF_0731 (solid): 12.01,6.68 12.01,6.7 11.96,6.7 11.96,6.68 12.01,6.68
no net on DXF_0731 (solid): 11.89,6.67 11.89,6.71 11.83,6.71 11.83,6.67 11.89,6.67
no net on DXF_0731 (solid): 11.89,6.68 11.89,6.7 11.83,6.7 11.83,6.68 11.89,6.68
no net on DXF_0731 (solid): 12.02,6.75 12.02,6.79 11.96,6.79 11.96,6.75 12.02,6.75
no net on DXF_0731 (solid): 12.01,6.76 12.01,6.78 11.96,6.78 11.96,6.76 12.01,6.76
no net on DXF_0731 (solid): 12.02,6.79 12.02,6.83 11.96,6.83 11.96,6.79 12.02,6.79
no net on DXF_0731 (solid): 12.01,6.8 12.01,6.82 11.96,6.82 11.96,6.8 12.01,6.8
no net on DXF_0731 (solid): 12.02,6.83 12.02,6.86 11.96,6.86 11.96,6.83 12.02,6.83
no net on DXF_0731 (solid): 12.01,6.84 12.01,6.86 11.96,6.86 11.96,6.84 12.01,6.84
no net on DXF_0731 (solid): 11.89,6.71 11.89,6.75 11.83,6.75 11.83,6.71 11.89,6.71
no net on DXF_0731 (solid): 11.89,6.72 11.89,6.74 11.83,6.74 11.83,6.72 11.89,6.72
no net on DXF_0731 (solid): 11.89,6.75 11.89,6.79 11.83,6.79 11.83,6.75 11.89,6.75
no net on DXF_0731 (solid): 11.89,6.76 11.89,6.78 11.83,6.78 11.83,6.76 11.89,6.76
no net on DXF_0731 (solid): 11.89,6.79 11.89,6.83 11.83,6.83 11.83,6.79 11.89,6.79
no net on DXF_0731 (solid): 11.89,6.8 11.89,6.82 11.83,6.82 11.83,6.8 11.89,6.8
no net on DXF_0731 (solid): 11.89,6.83 11.89,6.86 11.83,6.86 11.83,6.83 11.89,6.83
no net on DXF_0731 (solid): 11.89,6.84 11.89,6.86 11.83,6.86 11.83,6.84 11.89,6.84
no net on DXF_0731 (solid): 12.05,6.67 12.05,6.69 12.02,6.69 12.02,6.67 12.05,6.67
no net on DXF_0731 (solid): 5.9,8.77 5.9,8.65 5.99,8.65 5.99,8.77 5.9,8.77
no net on DXF_0731 (solid): 5.9,8.77 5.9,8.65 5.98,8.65 5.98,8.77 5.9,8.77
no net on DXF_0731 (solid): 6.04,8.7 6.04,8.67 6.1,8.67 6.1,8.7 6.04,8.7
no net on DXF_0731 (solid): 6.04,8.69 6.04,8.68 6.1,8.68 6.1,8.69 6.04,8.69
no net on DXF_0731 (solid): 6.04,8.72 6.04,8.7 6.1,8.7 6.1,8.72 6.04,8.72
no net on DXF_0731 (solid): 6.04,8.67 6.04,8.65 6.1,8.65 6.1,8.67 6.04,8.67
no net on DXF_0731 (solid): 6.04,8.77 6.04,8.75 6.1,8.75 6.1,8.77 6.04,8.77
no net on DXF_0731 (solid): 6.04,8.75 6.04,8.72 6.1,8.72 6.1,8.75 6.04,8.75
no net on DXF_0731 (solid): 6.04,8.74 6.04,8.73 6.1,8.73 6.1,8.74 6.04,8.74
no net on DXF_0731 (solid): 5.92,8.52 6.01,8.52 6.01,8.57 5.92,8.57 5.92,8.52
no net on DXF_0731 (solid): 5.92,8.51 6.01,8.51 6.01,8.58 5.92,8.58 5.92,8.51
no net on DXF_0731 (solid): 5.92,8.85 6.01,8.85 6.01,8.9 5.92,8.9 5.92,8.85
no net on DXF_0731 (solid): 5.92,8.84 6.01,8.84 6.01,8.91 5.92,8.91 5.92,8.84
no net on DXF_0731 (solid): 5.92,9.33 5.92,9.22 6,9.22 6,9.33 5.92,9.33
no net on DXF_0731 (solid): 6.05,9.26 6.05,9.24 6.12,9.24 6.12,9.26 6.05,9.26
no net on DXF_0731 (solid): 6.06,9.26 6.06,9.24 6.11,9.24 6.11,9.26 6.06,9.26
no net on DXF_0731 (solid): 6.05,9.29 6.05,9.26 6.12,9.26 6.12,9.29 6.05,9.29
no net on DXF_0731 (solid): 6.06,9.28 6.06,9.27 6.11,9.27 6.11,9.28 6.06,9.28
no net on DXF_0731 (solid): 6.05,9.24 6.05,9.21 6.12,9.21 6.12,9.24 6.05,9.24
no net on DXF_0731 (solid): 6.06,9.23 6.06,9.22 6.11,9.22 6.11,9.23 6.06,9.23
no net on DXF_0731 (solid): 6.05,9.34 6.05,9.31 6.12,9.31 6.12,9.34 6.05,9.34
no net on DXF_0731 (solid): 6.06,9.33 6.06,9.32 6.11,9.32 6.11,9.33 6.06,9.33
no net on DXF_0731 (solid): 6.05,9.31 6.05,9.29 6.12,9.29 6.12,9.31 6.05,9.31
no net on DXF_0731 (solid): 6.06,9.31 6.06,9.29 6.11,9.29 6.11,9.31 6.06,9.31
no net on DXF_0731 (solid): 5.94,9.08 6.02,9.08 6.02,9.14 5.94,9.14 5.94,9.08
no net on DXF_0731 (solid): 5.93,9.08 6.03,9.08 6.03,9.14 5.93,9.14 5.93,9.08
no net on DXF_0731 (solid): 5.94,9.41 6.02,9.41 6.02,9.47 5.94,9.47 5.94,9.41
no net on DXF_0731 (solid): 5.93,9.41 6.03,9.41 6.03,9.47 5.93,9.47 5.93,9.41
no net on DXF_0731 (solid): 5.92,9.87 5.92,9.75 6,9.75 6,9.87 5.92,9.87
no net on DXF_0731 (solid): 6.05,9.8 6.05,9.77 6.12,9.77 6.12,9.8 6.05,9.8
no net on DXF_0731 (solid): 6.06,9.79 6.06,9.78 6.11,9.78 6.11,9.79 6.06,9.79
no net on DXF_0731 (solid): 6.05,9.82 6.05,9.8 6.12,9.8 6.12,9.82 6.05,9.82
no net on DXF_0731 (solid): 6.06,9.82 6.06,9.8 6.11,9.8 6.11,9.82 6.06,9.82
no net on DXF_0731 (solid): 6.05,9.77 6.05,9.75 6.12,9.75 6.12,9.77 6.05,9.77
no net on DXF_0731 (solid): 6.06,9.77 6.06,9.75 6.11,9.75 6.11,9.77 6.06,9.77
no net on DXF_0731 (solid): 6.05,9.87 6.05,9.85 6.12,9.85 6.12,9.87 6.05,9.87
no net on DXF_0731 (solid): 6.06,9.87 6.06,9.85 6.11,9.85 6.11,9.87 6.06,9.87
no net on DXF_0731 (solid): 6.05,9.85 6.05,9.82 6.12,9.82 6.12,9.85 6.05,9.85
no net on DXF_0731 (solid): 6.06,9.84 6.06,9.83 6.11,9.83 6.11,9.84 6.06,9.84
no net on DXF_0731 (solid): 5.94,9.62 6.02,9.62 6.02,9.67 5.94,9.67 5.94,9.62
no net on DXF_0731 (solid): 5.93,9.61 6.03,9.61 6.03,9.68 5.93,9.68 5.93,9.61
no net on DXF_0731 (solid): 5.94,9.95 6.02,9.95 6.02,10 5.94,10 5.94,9.95
no net on DXF_0731 (solid): 5.93,9.94 6.03,9.94 6.03,10.01 5.93,10.01 5.93,9.94
no net on DXF_0731 (solid): 8.21,6.4 8.21,6.45 8.14,6.45 8.14,6.4 8.21,6.4
no net on DXF_0731 (solid): 8.2,6.4 8.2,6.44 8.14,6.44 8.14,6.4 8.2,6.4
no net on DXF_0731 (solid): 8.56,6.4 8.56,6.45 8.49,6.45 8.49,6.4 8.56,6.4
no net on DXF_0731 (solid): 8.56,6.4 8.56,6.44 8.5,6.44 8.5,6.4 8.56,6.4
no net on DXF_0731 (solid): 8.56,6.22 8.56,6.27 8.49,6.27 8.49,6.22 8.56,6.22
no net on DXF_0731 (solid): 8.56,6.23 8.56,6.27 8.5,6.27 8.5,6.23 8.56,6.23
no net on DXF_0731 (solid): 8.21,6.22 8.21,6.27 8.14,6.27 8.14,6.22 8.21,6.22
no net on DXF_0731 (solid): 8.2,6.23 8.2,6.27 8.14,6.27 8.14,6.23 8.2,6.23
no net on DXF_0731 (solid): 8.81,6.38 8.81,6.43 8.74,6.43 8.74,6.38 8.81,6.38
no net on DXF_0731 (solid): 8.8,6.39 8.8,6.43 8.74,6.43 8.74,6.39 8.8,6.39
no net on DXF_0731 (solid): 9.16,6.38 9.16,6.43 9.09,6.43 9.09,6.38 9.16,6.38
no net on DXF_0731 (solid): 9.16,6.39 9.16,6.43 9.1,6.43 9.1,6.39 9.16,6.39
no net on DXF_0731 (solid): 9.16,6.21 9.16,6.26 9.09,6.26 9.09,6.21 9.16,6.21
no net on DXF_0731 (solid): 9.16,6.21 9.16,6.25 9.1,6.25 9.1,6.21 9.16,6.21
no net on DXF_0731 (solid): 8.81,6.21 8.81,6.26 8.74,6.26 8.74,6.21 8.81,6.21
no net on DXF_0731 (solid): 8.8,6.21 8.8,6.25 8.74,6.25 8.74,6.21 8.8,6.21
no net on DXF_0731 (solid): 7.83,6.42 7.88,6.36 7.92,6.4 7.86,6.45 7.83,6.42
no net on DXF_0731 (solid): 7.84,6.42 7.88,6.37 7.91,6.4 7.86,6.45 7.84,6.42
no net on DXF_0731 (solid): 7.63,6.22 7.68,6.16 7.72,6.2 7.66,6.25 7.63,6.22
no net on DXF_0731 (solid): 7.63,6.22 7.68,6.17 7.71,6.2 7.66,6.25 7.63,6.22
no net on DXF_0731 (solid): 7.68,6.45 7.74,6.39 7.77,6.42 7.72,6.48 7.68,6.45
no net on DXF_0731 (solid): 7.69,6.45 7.74,6.4 7.77,6.42 7.72,6.47 7.69,6.45
no net on DXF_0731 (solid): 7.61,6.37 7.66,6.31 7.69,6.35 7.64,6.4 7.61,6.37
no net on DXF_0731 (solid): 7.61,6.37 7.66,6.32 7.69,6.35 7.64,6.4 7.61,6.37
no net on DXF_0731 (solid): 7.86,6.27 7.91,6.22 7.94,6.25 7.89,6.31 7.86,6.27
no net on DXF_0731 (solid): 7.86,6.27 7.91,6.22 7.94,6.25 7.89,6.3 7.86,6.27
no net on DXF_0731 (solid): 7.78,6.2 7.83,6.14 7.87,6.17 7.81,6.23 7.78,6.2
no net on DXF_0731 (solid): 7.78,6.2 7.83,6.15 7.86,6.17 7.81,6.22 7.78,6.2
no net on DXF_0731 (solid): 7.82,6.23 7.87,6.18 7.91,6.21 7.85,6.27 7.82,6.23
no net on DXF_0731 (solid): 7.82,6.23 7.87,6.18 7.9,6.21 7.85,6.26 7.82,6.23
no net on DXF_0731 (solid): 7.64,6.41 7.7,6.35 7.73,6.39 7.68,6.44 7.64,6.41
no net on DXF_0731 (solid): 7.65,6.41 7.7,6.36 7.73,6.39 7.68,6.44 7.65,6.41
no net on DXF_0731 (solid): 8.88,10.71 8.87,10.71 8.87,10.63 8.88,10.63 8.88,10.71
no net on DXF_0731 (solid): 8.88,10.71 8.81,10.71 8.81,10.7 8.88,10.7 8.88,10.71
no net on DXF_0731 (solid): 8.41,10.04 8.41,9.97 8.42,9.97 8.42,10.04 8.41,10.04
no net on DXF_0731 (solid): 8.41,10.04 8.41,10.03 8.49,10.03 8.49,10.04 8.41,10.04
no net on DXF_0731 (solid): 8.75,11.1 8.75,11.12 8.68,11.12 8.68,11.1 8.75,11.1
no net on DXF_0731 (solid): 8.75,11.11 8.75,11.12 8.68,11.12 8.68,11.11 8.75,11.11
no net on DXF_0731 (solid): 8.75,11.12 8.75,11.14 8.68,11.14 8.68,11.12 8.75,11.12
no net on DXF_0731 (solid): 8.75,11.13 8.75,11.14 8.68,11.14 8.68,11.13 8.75,11.13
no net on DXF_0731 (solid): 8.75,11.14 8.75,11.16 8.68,11.16 8.68,11.14 8.75,11.14
no net on DXF_0731 (solid): 8.75,11.15 8.75,11.16 8.68,11.16 8.68,11.15 8.75,11.15
no net on DXF_0731 (solid): 8.75,11.16 8.75,11.18 8.68,11.18 8.68,11.16 8.75,11.16
no net on DXF_0731 (solid): 8.75,11.17 8.75,11.18 8.68,11.18 8.68,11.17 8.75,11.17
no net on DXF_0731 (solid): 8.75,11.18 8.75,11.2 8.68,11.2 8.68,11.18 8.75,11.18
no net on DXF_0731 (solid): 8.75,11.19 8.75,11.2 8.68,11.2 8.68,11.19 8.75,11.19
no net on DXF_0731 (solid): 8.75,11.2 8.75,11.22 8.68,11.22 8.68,11.2 8.75,11.2
no net on DXF_0731 (solid): 8.75,11.21 8.75,11.22 8.68,11.22 8.68,11.21 8.75,11.21
no net on DXF_0731 (solid): 8.75,11.22 8.75,11.24 8.68,11.24 8.68,11.22 8.75,11.22
no net on DXF_0731 (solid): 8.75,11.23 8.75,11.24 8.68,11.24 8.68,11.23 8.75,11.23
no net on DXF_0731 (solid): 8.75,11.24 8.75,11.26 8.68,11.26 8.68,11.24 8.75,11.24
no net on DXF_0731 (solid): 8.75,11.25 8.75,11.26 8.68,11.26 8.68,11.25 8.75,11.25
no net on DXF_0731 (solid): 8.75,11.26 8.75,11.28 8.68,11.28 8.68,11.26 8.75,11.26
no net on DXF_0731 (solid): 8.75,11.27 8.75,11.28 8.68,11.28 8.68,11.27 8.75,11.27
no net on DXF_0731 (solid): 8.75,11.28 8.75,11.3 8.68,11.3 8.68,11.28 8.75,11.28
no net on DXF_0731 (solid): 8.75,11.29 8.75,11.3 8.68,11.3 8.68,11.29 8.75,11.29
no net on DXF_0731 (solid): 8.75,11.3 8.75,11.32 8.68,11.32 8.68,11.3 8.75,11.3
no net on DXF_0731 (solid): 8.75,11.31 8.75,11.32 8.68,11.32 8.68,11.31 8.75,11.31
no net on DXF_0731 (solid): 8.75,11.32 8.75,11.34 8.68,11.34 8.68,11.32 8.75,11.32
no net on DXF_0731 (solid): 8.75,11.33 8.75,11.34 8.68,11.34 8.68,11.33 8.75,11.33
no net on DXF_0731 (solid): 8.75,11.34 8.75,11.36 8.68,11.36 8.68,11.34 8.75,11.34
no net on DXF_0731 (solid): 8.75,11.36 8.75,11.38 8.68,11.38 8.68,11.36 8.75,11.36
no net on DXF_0731 (solid): 8.75,11.36 8.75,11.37 8.68,11.37 8.68,11.36 8.75,11.36
no net on DXF_0731 (solid): 8.75,11.38 8.75,11.4 8.68,11.4 8.68,11.38 8.75,11.38
no net on DXF_0731 (solid): 8.75,11.38 8.75,11.39 8.68,11.39 8.68,11.38 8.75,11.38
no net on DXF_0731 (solid): 8.75,11.44 8.75,11.46 8.68,11.46 8.68,11.44 8.75,11.44
no net on DXF_0731 (solid): 8.75,11.44 8.75,11.45 8.68,11.45 8.68,11.44 8.75,11.44
no net on DXF_0731 (solid): 8.75,11.46 8.75,11.48 8.68,11.48 8.68,11.46 8.75,11.46
no net on DXF_0731 (solid): 8.75,11.46 8.75,11.47 8.68,11.47 8.68,11.46 8.75,11.46
no net on DXF_0731 (solid): 8.75,11.48 8.75,11.5 8.68,11.5 8.68,11.48 8.75,11.48
no net on DXF_0731 (solid): 8.75,11.48 8.75,11.49 8.68,11.49 8.68,11.48 8.75,11.48
no net on DXF_0731 (solid): 8.75,11.5 8.75,11.52 8.68,11.52 8.68,11.5 8.75,11.5
no net on DXF_0731 (solid): 8.75,11.5 8.75,11.51 8.68,11.51 8.68,11.5 8.75,11.5
no net on DXF_0731 (solid): 8.75,11.52 8.75,11.54 8.68,11.54 8.68,11.52 8.75,11.52
no net on DXF_0731 (solid): 8.75,11.52 8.75,11.53 8.68,11.53 8.68,11.52 8.75,11.52
no net on DXF_0731 (solid): 8.75,11.54 8.75,11.56 8.68,11.56 8.68,11.54 8.75,11.54
no net on DXF_0731 (solid): 8.75,11.54 8.75,11.55 8.68,11.55 8.68,11.54 8.75,11.54
no net on DXF_0731 (solid): 8.75,11.56 8.75,11.58 8.68,11.58 8.68,11.56 8.75,11.56
no net on DXF_0731 (solid): 8.75,11.56 8.75,11.57 8.68,11.57 8.68,11.56 8.75,11.56
no net on DXF_0731 (solid): 8.75,11.58 8.75,11.6 8.68,11.6 8.68,11.58 8.75,11.58
no net on DXF_0731 (solid): 8.75,11.58 8.75,11.59 8.68,11.59 8.68,11.58 8.75,11.58
no net on DXF_0731 (solid): 8.79,11.69 8.77,11.69 8.77,11.62 8.79,11.62 8.79,11.69
no net on DXF_0731 (solid): 8.79,11.69 8.78,11.69 8.78,11.62 8.79,11.62 8.79,11.69
no net on DXF_0731 (solid): 8.81,11.69 8.79,11.69 8.79,11.62 8.81,11.62 8.81,11.69
no net on DXF_0731 (solid): 8.81,11.69 8.8,11.69 8.8,11.62 8.81,11.62 8.81,11.69
no net on DXF_0731 (solid): 8.85,11.69 8.83,11.69 8.83,11.62 8.85,11.62 8.85,11.69
no net on DXF_0731 (solid): 8.85,11.69 8.84,11.69 8.84,11.62 8.85,11.62 8.85,11.69
no net on DXF_0731 (solid): 8.87,11.69 8.85,11.69 8.85,11.62 8.87,11.62 8.87,11.69
no net on DXF_0731 (solid): 8.87,11.69 8.86,11.69 8.86,11.62 8.87,11.62 8.87,11.69
no net on DXF_0731 (solid): 8.89,11.69 8.87,11.69 8.87,11.62 8.89,11.62 8.89,11.69
no net on DXF_0731 (solid): 8.89,11.69 8.88,11.69 8.88,11.62 8.89,11.62 8.89,11.69
no net on DXF_0731 (solid): 8.93,11.69 8.91,11.69 8.91,11.62 8.93,11.62 8.93,11.69
no net on DXF_0731 (solid): 8.93,11.69 8.92,11.69 8.92,11.62 8.93,11.62 8.93,11.69
no net on DXF_0731 (solid): 8.95,11.69 8.93,11.69 8.93,11.62 8.95,11.62 8.95,11.69
no net on DXF_0731 (solid): 8.95,11.69 8.94,11.69 8.94,11.62 8.95,11.62 8.95,11.69
no net on DXF_0731 (solid): 8.97,11.69 8.95,11.69 8.95,11.62 8.97,11.62 8.97,11.69
no net on DXF_0731 (solid): 8.97,11.69 8.96,11.69 8.96,11.62 8.97,11.62 8.97,11.69
no net on DXF_0731 (solid): 8.99,11.69 8.97,11.69 8.97,11.62 8.99,11.62 8.99,11.69
no net on DXF_0731 (solid): 8.99,11.69 8.98,11.69 8.98,11.62 8.99,11.62 8.99,11.69
no net on DXF_0731 (solid): 9.01,11.69 8.99,11.69 8.99,11.62 9.01,11.62 9.01,11.69
no net on DXF_0731 (solid): 9.01,11.69 9,11.69 9,11.62 9.01,11.62 9.01,11.69
no net on DXF_0731 (solid): 9.03,11.69 9.01,11.69 9.01,11.62 9.03,11.62 9.03,11.69
no net on DXF_0731 (solid): 9.05,11.69 9.03,11.69 9.03,11.62 9.05,11.62 9.05,11.69
no net on DXF_0731 (solid): 9.04,11.69 9.03,11.69 9.03,11.62 9.04,11.62 9.04,11.69
no net on DXF_0731 (solid): 9.07,11.69 9.05,11.69 9.05,11.62 9.07,11.62 9.07,11.69
no net on DXF_0731 (solid): 9.06,11.69 9.05,11.69 9.05,11.62 9.06,11.62 9.06,11.69
no net on DXF_0731 (solid): 9.09,11.69 9.07,11.69 9.07,11.62 9.09,11.62 9.09,11.69
no net on DXF_0731 (solid): 9.08,11.69 9.07,11.69 9.07,11.62 9.08,11.62 9.08,11.69
no net on DXF_0731 (solid): 9.11,11.69 9.09,11.69 9.09,11.62 9.11,11.62 9.11,11.69
no net on DXF_0731 (solid): 9.1,11.69 9.09,11.69 9.09,11.62 9.1,11.62 9.1,11.69
no net on DXF_0731 (solid): 9.13,11.69 9.11,11.69 9.11,11.62 9.13,11.62 9.13,11.69
no net on DXF_0731 (solid): 9.12,11.69 9.11,11.69 9.11,11.62 9.12,11.62 9.12,11.69
no net on DXF_0731 (solid): 9.15,11.69 9.13,11.69 9.13,11.62 9.15,11.62 9.15,11.69
no net on DXF_0731 (solid): 9.14,11.69 9.13,11.69 9.13,11.62 9.14,11.62 9.14,11.69
no net on DXF_0731 (solid): 9.17,11.69 9.15,11.69 9.15,11.62 9.17,11.62 9.17,11.69
no net on DXF_0731 (solid): 9.16,11.69 9.15,11.69 9.15,11.62 9.16,11.62 9.16,11.69
no net on DXF_0731 (solid): 9.19,11.69 9.17,11.69 9.17,11.62 9.19,11.62 9.19,11.69
no net on DXF_0731 (solid): 9.18,11.69 9.17,11.69 9.17,11.62 9.18,11.62 9.18,11.69
no net on DXF_0731 (solid): 9.21,11.69 9.19,11.69 9.19,11.62 9.21,11.62 9.21,11.69
no net on DXF_0731 (solid): 9.2,11.69 9.19,11.69 9.19,11.62 9.2,11.62 9.2,11.69
no net on DXF_0731 (solid): 9.23,11.69 9.21,11.69 9.21,11.62 9.23,11.62 9.23,11.69
no net on DXF_0731 (solid): 9.22,11.69 9.21,11.69 9.21,11.62 9.22,11.62 9.22,11.69
no net on DXF_0731 (solid): 9.25,11.69 9.23,11.69 9.23,11.62 9.25,11.62 9.25,11.69
no net on DXF_0731 (solid): 9.24,11.69 9.23,11.69 9.23,11.62 9.24,11.62 9.24,11.69
no net on DXF_0731 (solid): 9.27,11.69 9.25,11.69 9.25,11.62 9.27,11.62 9.27,11.69
no net on DXF_0731 (solid): 9.26,11.69 9.25,11.69 9.25,11.62 9.26,11.62 9.26,11.69
no net on DXF_0731 (solid): 9.36,11.58 9.36,11.6 9.29,11.6 9.29,11.58 9.36,11.58
no net on DXF_0731 (solid): 9.36,11.58 9.36,11.59 9.29,11.59 9.29,11.58 9.36,11.58
no net on DXF_0731 (solid): 9.36,11.56 9.36,11.58 9.29,11.58 9.29,11.56 9.36,11.56
no net on DXF_0731 (solid): 9.36,11.56 9.36,11.57 9.29,11.57 9.29,11.56 9.36,11.56
no net on DXF_0731 (solid): 9.36,11.54 9.36,11.56 9.29,11.56 9.29,11.54 9.36,11.54
no net on DXF_0731 (solid): 9.36,11.54 9.36,11.55 9.29,11.55 9.29,11.54 9.36,11.54
no net on DXF_0731 (solid): 9.36,11.52 9.36,11.54 9.29,11.54 9.29,11.52 9.36,11.52
no net on DXF_0731 (solid): 9.36,11.52 9.36,11.53 9.29,11.53 9.29,11.52 9.36,11.52
no net on DXF_0731 (solid): 9.36,11.5 9.36,11.52 9.29,11.52 9.29,11.5 9.36,11.5
no net on DXF_0731 (solid): 9.36,11.5 9.36,11.51 9.29,11.51 9.29,11.5 9.36,11.5
no net on DXF_0731 (solid): 9.36,11.48 9.36,11.5 9.29,11.5 9.29,11.48 9.36,11.48
no net on DXF_0731 (solid): 9.36,11.48 9.36,11.49 9.29,11.49 9.29,11.48 9.36,11.48
no net on DXF_0731 (solid): 9.36,11.46 9.36,11.48 9.29,11.48 9.29,11.46 9.36,11.46
no net on DXF_0731 (solid): 9.36,11.46 9.36,11.47 9.29,11.47 9.29,11.46 9.36,11.46
no net on DXF_0731 (solid): 9.36,11.44 9.36,11.46 9.29,11.46 9.29,11.44 9.36,11.44
no net on DXF_0731 (solid): 9.36,11.44 9.36,11.45 9.29,11.45 9.29,11.44 9.36,11.44
no net on DXF_0731 (solid): 9.36,11.42 9.36,11.44 9.29,11.44 9.29,11.42 9.36,11.42
no net on DXF_0731 (solid): 9.36,11.42 9.36,11.43 9.29,11.43 9.29,11.42 9.36,11.42
no net on DXF_0731 (solid): 9.36,11.4 9.36,11.42 9.29,11.42 9.29,11.4 9.36,11.4
no net on DXF_0731 (solid): 9.36,11.4 9.36,11.41 9.29,11.41 9.29,11.4 9.36,11.4
no net on DXF_0731 (solid): 9.36,11.38 9.36,11.4 9.29,11.4 9.29,11.38 9.36,11.38
no net on DXF_0731 (solid): 9.36,11.38 9.36,11.39 9.29,11.39 9.29,11.38 9.36,11.38
no net on DXF_0731 (solid): 9.36,11.36 9.36,11.38 9.29,11.38 9.29,11.36 9.36,11.36
no net on DXF_0731 (solid): 9.36,11.36 9.36,11.37 9.29,11.37 9.29,11.36 9.36,11.36
no net on DXF_0731 (solid): 9.36,11.34 9.36,11.36 9.29,11.36 9.29,11.34 9.36,11.34
no net on DXF_0731 (solid): 9.36,11.32 9.36,11.34 9.29,11.34 9.29,11.32 9.36,11.32
no net on DXF_0731 (solid): 9.36,11.33 9.36,11.34 9.29,11.34 9.29,11.33 9.36,11.33
no net on DXF_0731 (solid): 9.36,11.3 9.36,11.32 9.29,11.32 9.29,11.3 9.36,11.3
no net on DXF_0731 (solid): 9.36,11.31 9.36,11.32 9.29,11.32 9.29,11.31 9.36,11.31
no net on DXF_0731 (solid): 9.36,11.28 9.36,11.3 9.29,11.3 9.29,11.28 9.36,11.28
no net on DXF_0731 (solid): 9.36,11.29 9.36,11.3 9.29,11.3 9.29,11.29 9.36,11.29
no net on DXF_0731 (solid): 9.36,11.26 9.36,11.28 9.29,11.28 9.29,11.26 9.36,11.26
no net on DXF_0731 (solid): 9.36,11.27 9.36,11.28 9.29,11.28 9.29,11.27 9.36,11.27
no net on DXF_0731 (solid): 9.36,11.24 9.36,11.26 9.29,11.26 9.29,11.24 9.36,11.24
no net on DXF_0731 (solid): 9.36,11.25 9.36,11.26 9.29,11.26 9.29,11.25 9.36,11.25
no net on DXF_0731 (solid): 9.36,11.22 9.36,11.24 9.29,11.24 9.29,11.22 9.36,11.22
no net on DXF_0731 (solid): 9.36,11.23 9.36,11.24 9.29,11.24 9.29,11.23 9.36,11.23
no net on DXF_0731 (solid): 9.36,11.2 9.36,11.22 9.29,11.22 9.29,11.2 9.36,11.2
no net on DXF_0731 (solid): 9.36,11.21 9.36,11.22 9.29,11.22 9.29,11.21 9.36,11.21
no net on DXF_0731 (solid): 9.36,11.18 9.36,11.2 9.29,11.2 9.29,11.18 9.36,11.18
no net on DXF_0731 (solid): 9.36,11.19 9.36,11.2 9.29,11.2 9.29,11.19 9.36,11.19
no net on DXF_0731 (solid): 9.36,11.16 9.36,11.18 9.29,11.18 9.29,11.16 9.36,11.16
no net on DXF_0731 (solid): 9.36,11.17 9.36,11.18 9.29,11.18 9.29,11.17 9.36,11.17
no net on DXF_0731 (solid): 9.36,11.14 9.36,11.16 9.29,11.16 9.29,11.14 9.36,11.14
no net on DXF_0731 (solid): 9.36,11.15 9.36,11.16 9.29,11.16 9.29,11.15 9.36,11.15
no net on DXF_0731 (solid): 9.36,11.12 9.36,11.14 9.29,11.14 9.29,11.12 9.36,11.12
no net on DXF_0731 (solid): 9.36,11.13 9.36,11.14 9.29,11.14 9.29,11.13 9.36,11.13
no net on DXF_0731 (solid): 9.36,11.1 9.36,11.12 9.29,11.12 9.29,11.1 9.36,11.1
no net on DXF_0731 (solid): 9.36,11.11 9.36,11.12 9.29,11.12 9.29,11.11 9.36,11.11
no net on DXF_0731 (solid): 9.27,11.08 9.25,11.08 9.25,11.01 9.27,11.01 9.27,11.08
no net on DXF_0731 (solid): 9.26,11.08 9.25,11.08 9.25,11.01 9.26,11.01 9.26,11.08
no net on DXF_0731 (solid): 9.25,11.08 9.23,11.08 9.23,11.01 9.25,11.01 9.25,11.08
no net on DXF_0731 (solid): 9.24,11.08 9.23,11.08 9.23,11.01 9.24,11.01 9.24,11.08
no net on DXF_0731 (solid): 9.23,11.08 9.21,11.08 9.21,11.01 9.23,11.01 9.23,11.08
no net on DXF_0731 (solid): 9.22,11.08 9.21,11.08 9.21,11.01 9.22,11.01 9.22,11.08
no net on DXF_0731 (solid): 9.21,11.08 9.19,11.08 9.19,11.01 9.21,11.01 9.21,11.08
no net on DXF_0731 (solid): 9.2,11.08 9.19,11.08 9.19,11.01 9.2,11.01 9.2,11.08
no net on DXF_0731 (solid): 9.19,11.08 9.17,11.08 9.17,11.01 9.19,11.01 9.19,11.08
no net on DXF_0731 (solid): 9.18,11.08 9.17,11.08 9.17,11.01 9.18,11.01 9.18,11.08
no net on DXF_0731 (solid): 9.17,11.08 9.15,11.08 9.15,11.01 9.17,11.01 9.17,11.08
no net on DXF_0731 (solid): 9.16,11.08 9.15,11.08 9.15,11.01 9.16,11.01 9.16,11.08
no net on DXF_0731 (solid): 9.15,11.08 9.13,11.08 9.13,11.01 9.15,11.01 9.15,11.08
no net on DXF_0731 (solid): 9.14,11.08 9.13,11.08 9.13,11.01 9.14,11.01 9.14,11.08
no net on DXF_0731 (solid): 9.13,11.08 9.11,11.08 9.11,11.01 9.13,11.01 9.13,11.08
no net on DXF_0731 (solid): 9.12,11.08 9.11,11.08 9.11,11.01 9.12,11.01 9.12,11.08
no net on DXF_0731 (solid): 9.11,11.08 9.09,11.08 9.09,11.01 9.11,11.01 9.11,11.08
no net on DXF_0731 (solid): 9.1,11.08 9.09,11.08 9.09,11.01 9.1,11.01 9.1,11.08
no net on DXF_0731 (solid): 9.09,11.08 9.07,11.08 9.07,11.01 9.09,11.01 9.09,11.08
no net on DXF_0731 (solid): 9.08,11.08 9.07,11.08 9.07,11.01 9.08,11.01 9.08,11.08
no net on DXF_0731 (solid): 9.07,11.08 9.05,11.08 9.05,11.01 9.07,11.01 9.07,11.08
no net on DXF_0731 (solid): 9.06,11.08 9.05,11.08 9.05,11.01 9.06,11.01 9.06,11.08
no net on DXF_0731 (solid): 9.05,11.08 9.03,11.08 9.03,11.01 9.05,11.01 9.05,11.08
no net on DXF_0731 (solid): 9.04,11.08 9.03,11.08 9.03,11.01 9.04,11.01 9.04,11.08
no net on DXF_0731 (solid): 9.03,11.08 9.01,11.08 9.01,11.01 9.03,11.01 9.03,11.08
no net on DXF_0731 (solid): 9.01,11.08 8.99,11.08 8.99,11.01 9.01,11.01 9.01,11.08
no net on DXF_0731 (solid): 9.01,11.08 9,11.08 9,11.01 9.01,11.01 9.01,11.08
no net on DXF_0731 (solid): 8.99,11.08 8.97,11.08 8.97,11.01 8.99,11.01 8.99,11.08
no net on DXF_0731 (solid): 8.99,11.08 8.98,11.08 8.98,11.01 8.99,11.01 8.99,11.08
no net on DXF_0731 (solid): 8.97,11.08 8.95,11.08 8.95,11.01 8.97,11.01 8.97,11.08
no net on DXF_0731 (solid): 8.97,11.08 8.96,11.08 8.96,11.01 8.97,11.01 8.97,11.08
no net on DXF_0731 (solid): 8.95,11.08 8.93,11.08 8.93,11.01 8.95,11.01 8.95,11.08
no net on DXF_0731 (solid): 8.95,11.08 8.94,11.08 8.94,11.01 8.95,11.01 8.95,11.08
no net on DXF_0731 (solid): 8.93,11.08 8.91,11.08 8.91,11.01 8.93,11.01 8.93,11.08
no net on DXF_0731 (solid): 8.93,11.08 8.92,11.08 8.92,11.01 8.93,11.01 8.93,11.08
no net on DXF_0731 (solid): 8.91,11.08 8.89,11.08 8.89,11.01 8.91,11.01 8.91,11.08
no net on DXF_0731 (solid): 8.91,11.08 8.9,11.08 8.9,11.01 8.91,11.01 8.91,11.08
no net on DXF_0731 (solid): 8.89,11.08 8.87,11.08 8.87,11.01 8.89,11.01 8.89,11.08
no net on DXF_0731 (solid): 8.89,11.08 8.88,11.08 8.88,11.01 8.89,11.01 8.89,11.08
no net on DXF_0731 (solid): 8.87,11.08 8.85,11.08 8.85,11.01 8.87,11.01 8.87,11.08
no net on DXF_0731 (solid): 8.87,11.08 8.86,11.08 8.86,11.01 8.87,11.01 8.87,11.08
no net on DXF_0731 (solid): 8.85,11.08 8.83,11.08 8.83,11.01 8.85,11.01 8.85,11.08
no net on DXF_0731 (solid): 8.85,11.08 8.84,11.08 8.84,11.01 8.85,11.01 8.85,11.08
no net on DXF_0731 (solid): 8.83,11.08 8.81,11.08 8.81,11.01 8.83,11.01 8.83,11.08
no net on DXF_0731 (solid): 8.83,11.08 8.82,11.08 8.82,11.01 8.83,11.01 8.83,11.08
no net on DXF_0731 (solid): 8.81,11.08 8.79,11.08 8.79,11.01 8.81,11.01 8.81,11.08
no net on DXF_0731 (solid): 8.81,11.08 8.8,11.08 8.8,11.01 8.81,11.01 8.81,11.08
no net on DXF_0731 (solid): 8.79,11.08 8.77,11.08 8.77,11.01 8.79,11.01 8.79,11.08
no net on DXF_0731 (solid): 8.79,11.08 8.78,11.08 8.78,11.01 8.79,11.01 8.79,11.08
no net on DXF_0731 (solid): 8.76,11.69 8.72,11.72 8.65,11.65 8.68,11.61 8.76,11.69
no net on DXF_0731 (solid): 8.75,11.69 8.72,11.72 8.65,11.65 8.68,11.62 8.75,11.69
no net on DXF_0731 (solid): 9.36,11.61 9.39,11.65 9.32,11.72 9.28,11.69 9.36,11.61
no net on DXF_0731 (solid): 9.36,11.62 9.39,11.65 9.32,11.72 9.29,11.69 9.36,11.62
no net on DXF_0731 (solid): 8.72,10.98 8.76,11.01 8.68,11.09 8.65,11.05 8.72,10.98
no net on DXF_0731 (solid): 8.72,10.98 8.75,11.01 8.68,11.08 8.65,11.05 8.72,10.98
no net on DXF_0731 (solid): 9.39,11.05 9.36,11.09 9.28,11.01 9.32,10.98 9.39,11.05
no net on DXF_0731 (solid): 9.39,11.05 9.36,11.08 9.29,11.01 9.32,10.98 9.39,11.05
no net on DXF_0731 (solid): 8.75,11.42 8.75,11.44 8.68,11.44 8.68,11.42 8.75,11.42
no net on DXF_0731 (solid): 8.75,11.42 8.75,11.43 8.68,11.43 8.68,11.42 8.75,11.42
no net on DXF_0731 (solid): 8.75,11.4 8.75,11.42 8.68,11.42 8.68,11.4 8.75,11.4
no net on DXF_0731 (solid): 8.75,11.4 8.75,11.41 8.68,11.41 8.68,11.4 8.75,11.4
no net on DXF_0731 (solid): 8.83,11.69 8.81,11.69 8.81,11.62 8.83,11.62 8.83,11.69
no net on DXF_0731 (solid): 8.83,11.69 8.82,11.69 8.82,11.62 8.83,11.62 8.83,11.69
no net on DXF_0731 (solid): 8.91,11.69 8.89,11.69 8.89,11.62 8.91,11.62 8.91,11.69
no net on DXF_0731 (solid): 8.91,11.69 8.9,11.69 8.9,11.62 8.91,11.62 8.91,11.69
no net on DXF_0731 (solid): 11.62,11.46 11.62,11.39 11.7,11.39 11.7,11.46 11.62,11.46
no net on DXF_0731 (solid): 11.62,11.47 11.62,11.39 11.7,11.39 11.7,11.47 11.62,11.47
no net on DXF_0731 (solid): 11.46,8.36 11.59,8.36 11.59,8.41 11.46,8.41 11.46,8.36
no net on DXF_0731 (solid): 11.47,8.36 11.59,8.36 11.59,8.41 11.47,8.41 11.47,8.36
no net on DXF_0731 (solid): 11.89,8.41 11.83,8.41 11.83,8.33 11.89,8.33 11.89,8.41
no net on DXF_0731 (solid): 11.89,8.41 11.84,8.41 11.84,8.33 11.89,8.33 11.89,8.41
no net on DXF_0731 (solid): 11.43,8.1 11.5,8.1 11.5,8.14 11.43,8.14 11.43,8.1
no net on DXF_0731 (solid): 11.43,8.1 11.49,8.1 11.49,8.13 11.43,8.13 11.43,8.1
no net on DXF_0731 (solid): 11.43,8.32 11.5,8.32 11.5,8.36 11.43,8.36 11.43,8.32
no net on DXF_0731 (solid): 11.43,8.32 11.49,8.32 11.49,8.35 11.43,8.35 11.43,8.32
no net on DXF_0731 (solid): 11.43,8.05 11.5,8.05 11.5,8.09 11.43,8.09 11.43,8.05
no net on DXF_0731 (solid): 11.43,8.06 11.49,8.06 11.49,8.09 11.43,8.09 11.43,8.06
no net on DXF_0731 (solid): 11.43,8.18 11.5,8.18 11.5,8.22 11.43,8.22 11.43,8.18
no net on DXF_0731 (solid): 11.43,8.19 11.49,8.19 11.49,8.22 11.43,8.22 11.43,8.19
no net on DXF_0731 (solid): 11.91,7.76 12.05,7.76 12.05,7.82 11.91,7.82 11.91,7.76
no net on DXF_0731 (solid): 11.91,8.35 12.04,8.35 12.04,8.41 11.91,8.41 11.91,8.35
no net on DXF_0731 (solid): 11.92,8.35 12.04,8.35 12.04,8.41 11.92,8.41 11.92,8.35
no net on DXF_0731 (solid): 11.43,8.27 11.5,8.27 11.5,8.31 11.43,8.31 11.43,8.27
no net on DXF_0731 (solid): 11.43,8.28 11.49,8.28 11.49,8.31 11.43,8.31 11.43,8.28
no net on DXF_0731 (solid): 11.43,7.97 11.5,7.97 11.5,8.01 11.43,8.01 11.43,7.97
no net on DXF_0731 (solid): 11.43,7.97 11.49,7.97 11.49,8 11.43,8 11.43,7.97
no net on DXF_0731 (solid): 11.43,8.01 11.5,8.01 11.5,8.05 11.43,8.05 11.43,8.01
no net on DXF_0731 (solid): 11.43,8.02 11.49,8.02 11.49,8.05 11.43,8.05 11.43,8.02
no net on DXF_0731 (solid): 11.43,8.23 11.5,8.23 11.5,8.27 11.43,8.27 11.43,8.23
no net on DXF_0731 (solid): 11.43,8.23 11.49,8.23 11.49,8.26 11.43,8.26 11.43,8.23
no net on DXF_0731 (solid): 11.47,7.76 11.62,7.76 11.62,7.83 11.47,7.83 11.47,7.76
no net on DXF_0731 (solid): 11.48,7.76 11.62,7.76 11.62,7.83 11.48,7.83 11.48,7.76
no net on DXF_0731 (solid): 11.43,8.14 11.5,8.14 11.5,8.18 11.43,8.18 11.43,8.14
no net on DXF_0731 (solid): 11.43,8.15 11.49,8.15 11.49,8.18 11.43,8.18 11.43,8.15
no net on DXF_0731 (solid): 6.35,11.57 6.35,11.64 6.27,11.64 6.27,11.57 6.35,11.57
no net on DXF_0731 (solid): 6.35,11.56 6.35,11.64 6.26,11.64 6.26,11.56 6.35,11.56
no net on DXF_0731 (solid): 10.19,12.72 10.16,12.72 10.16,12.64 10.19,12.64 10.19,12.72
no net on DXF_0731 (solid): 10.19,12.72 10.17,12.72 10.17,12.64 10.19,12.64 10.19,12.72
no net on DXF_0731 (solid): 10.23,12.72 10.2,12.72 10.2,12.64 10.23,12.64 10.23,12.72
no net on DXF_0731 (solid): 10.22,12.72 10.2,12.72 10.2,12.64 10.22,12.64 10.22,12.72
no net on DXF_0731 (solid): 10.41,12.72 10.39,12.72 10.39,12.64 10.41,12.64 10.41,12.72
no net on DXF_0731 (solid): 10.34,12.72 10.31,12.72 10.31,12.64 10.34,12.64 10.34,12.72
no net on DXF_0731 (solid): 10.34,12.72 10.32,12.72 10.32,12.64 10.34,12.64 10.34,12.72
no net on DXF_0731 (solid): 10.3,12.72 10.27,12.72 10.27,12.64 10.3,12.64 10.3,12.72
no net on DXF_0731 (solid): 10.3,12.72 10.28,12.72 10.28,12.64 10.3,12.64 10.3,12.72
no net on DXF_0731 (solid): 10.27,12.72 10.24,12.72 10.24,12.64 10.27,12.64 10.27,12.72
no net on DXF_0731 (solid): 10.26,12.72 10.24,12.72 10.24,12.64 10.26,12.64 10.26,12.72
no net on DXF_0731 (solid): 10.38,12.72 10.35,12.72 10.35,12.64 10.38,12.64 10.38,12.72
no net on DXF_0731 (solid): 10.37,12.72 10.35,12.72 10.35,12.64 10.37,12.64 10.37,12.72
no net on DXF_0731 (solid): 10.15,12.72 10.13,12.72 10.13,12.64 10.15,12.64 10.15,12.72
no net on DXF_0731 (solid): 6.03,8.38 5.98,8.38 5.98,8.27 6.03,8.27 6.03,8.38
no net on DXF_0731 (solid): 6.03,8.37 5.98,8.37 5.98,8.27 6.03,8.27 6.03,8.37
no net on DXF_0731 (solid): 6.16,8.38 6.07,8.38 6.07,8.27 6.16,8.27 6.16,8.38
no net on DXF_0731 (solid): 6.16,8.37 6.08,8.37 6.08,8.27 6.16,8.27 6.16,8.37
no net on DXF_0731 (solid): 6.09,8.06 6,8.06 6,7.95 6.09,7.95 6.09,8.06
no net on DXF_0731 (solid): 6.08,8.06 6.01,8.06 6.01,7.96 6.08,7.96 6.08,8.06
no net on DXF_0731 (solid): 5.96,8.06 5.9,8.06 5.9,7.95 5.96,7.95 5.96,8.06
no net on DXF_0731 (solid): 5.96,8.06 5.91,8.06 5.91,7.96 5.96,7.96 5.96,8.06
no net on DXF_0731 (solid): 6.45,8.06 6.36,8.06 6.36,7.95 6.45,7.95 6.45,8.06
no net on DXF_0731 (solid): 6.45,8.06 6.37,8.06 6.37,7.96 6.45,7.96 6.45,8.06
no net on DXF_0731 (solid): 6.51,8.24 6.51,8.15 6.62,8.15 6.62,8.24 6.51,8.24
no net on DXF_0731 (solid): 6.52,8.24 6.52,8.16 6.62,8.16 6.62,8.24 6.52,8.24
no net on DXF_0731 (solid): 9.41,6.38 9.41,6.12 9.85,6.12 9.85,6.38 9.41,6.38
no net on DXF_0731 (solid): 9.35,9.51 9.35,10.09 8.98,10.09 8.98,9.51 9.35,9.51
no net on DXF_0731 (solid): 17.2,9.72 21.57,9.72 21.57,13.22 17.2,13.22 17.2,9.72
no net on DXF_0731 (solid): 17.23,6.47 22.3,6.47 22.3,9.2 17.23,9.2 17.23,6.47
no net on DXF_0731 (solid): 9.78,9.46 9.9,9.46 9.9,10.42 9.78,10.42 9.78,9.46
no net on DXF_0731 (solid): 7.93,9.44 8.04,9.44 8.04,10.4 7.93,10.4 7.93,9.44
no net on LAY4 (solid): 23 vertices, not listed, extent -100,0 0,100
no net on LAY4 (solid): 23 vertices, not listed, extent 0,-100 100,0
no net on LAY4 (solid): 4715,3080 ccw(c4655,3080) 4655,3140 ccw(c4655,3080) 4595,3080 ccw(c4655,3080) 4655,3020 ccw(c4655,3080) 4715,3080
no net on LAY4 (solid): 4715,3080 ccw(c4655,3080) 4655,3140 ccw(c4655,3080) 4595,3080 ccw(c4655,3080) 4655,3020 ccw(c4655,3080) 4715,3080
no net on LAY4 (solid): 500,390 ccw(c440,390) 440,450 ccw(c440,390) 380,390 ccw(c440,390) 440,330 ccw(c440,390) 500,390
no net on LAY4 (solid): 500,390 ccw(c440,390) 440,450 ccw(c440,390) 380,390 ccw(c440,390) 440,330 ccw(c440,390) 500,390
no net on LAY4 (solid): 455,3055 ccw(c395,3055) 395,3115 ccw(c395,3055) 335,3055 ccw(c395,3055) 395,2995 ccw(c395,3055) 455,3055
no net on LAY4 (solid): 455,3055 ccw(c395,3055) 395,3115 ccw(c395,3055) 335,3055 ccw(c395,3055) 395,2995 ccw(c395,3055) 455,3055
no net on LAY4 (solid): 23 vertices, not listed, extent -100,0 0,100
no net on LAY4 (solid): 23 vertices, not listed, extent 0,-100 100,0
POE7 on BOTTOM "BOTTOM-POE7 3" (solid, pour order 0): 439 vertices, not listed, extent 3400,21 3935,195
POE7 on BOTTOM "BOTTOM-POE7 2" (solid, pour order 2): 24 vertices, not listed, extent 4275,690 4570,925
POE7 on BOTTOM "BOTTOM-POE7 1" (solid, pour order 4): 18 vertices, not listed, extent 1100.92,1951.78 1270.71,2111.79
POE7 on BOTTOM "BOTTOM-POE7" (solid, pour order 6): 4406.8,2460 4406.8,2514.22 4280,2514.22 4280,2550.62 4406.8,2550.62 4406.8,2612.66 4280,2612.66 4280,2625 4420,2625 4435,2610 4435,2475 4420,2460 4406.8,2460
POE4 on BOTTOM "BOTTOM-POE4" (solid, pour order 14): 45 vertices, not listed, extent 3615,2155 3945,2335
POE5 on BOTTOM "BOTTOM-POE5" (solid, pour order 16): 49 vertices, not listed, extent 4405,2270 4665,2465
NETC18_2 on BOTTOM "BOTTOM-NETC18_2" (solid, pour order 22): 4475,2495 4460,2510 4460,2660 4470,2670 4615,2670 4660,2625 4660,2557.02 4626.48,2557.02 4626.48,2512.98 4660,2512.98 4660,2505 4650,2495 4475,2495
3V3 on BOTTOM "BOTTOM-3V3 1" (solid, pour order 28): 1160,1715 1140,1735 1140,1820 1149.04,1829.04 1172.5,1829.04 1172.5,1773.44 1255.54,1773.44 1255.54,1829.04 1270.96,1829.04 1280,1820 1280,1725 1270,1715 1160,1715
3V3 on BOTTOM "BOTTOM-3V3" (solid, pour order 30): 127 vertices, not listed, extent 1475,1810 1605,2085
1V8 on BOTTOM "BOTTOM-1V8" (solid, pour order 34): 20 vertices, not listed, extent 907.02,1800.15 1273.86,2112.48
AGND on BOTTOM "BOTTOM-AGND" (solid, pour order 38): 120 vertices, not listed, extent 3900,2935 4595,3305
NETC153_2 on BOTTOM "BOTTOM-NETC153_2" (solid, pour order 40): 410 vertices, not listed, extent 2905,20.4 3390,325
5V_ST_LINK on BOTTOM "BOTTOM-5V_ST_LINK" (solid, pour order 42): 21 vertices, not listed, extent 4335,330 4455,405
5V_USB_CHARGER on BOTTOM "BOTTOM-5V_USB_CHARGER" (solid, pour order 44): 107 vertices, not listed, extent 3960,155 4475,360
VDD on BOTTOM "BOTTOM-VDD" (solid, pour order 46): 1635,1810 1625,1820 1625,1900.48 1676.02,1900.48 1676.02,1959.52 1625,1959.52 1625,2060 1640,2075 1760,2075 1775,2060 1775,1820 1765,1810 1635,1810
VIN on BOTTOM "BOTTOM-VIN" (solid, pour order 48): 67 vertices, not listed, extent 4095,625 4255,933
E5V on BOTTOM "BOTTOM-E5V" (solid, pour order 50): 24 vertices, not listed, extent 4135,916 4575,1175
POE7 on TOP "TOP-POE7" (solid, pour order 8): 34 vertices, not listed, extent 4160,2889.15 4495,2985
POE3 on TOP "TOP-POE3" (solid, pour order 10): 3440,2635 3425,2650 3425,2790 3445,2810 3520,2810 3590,2740 3687.5,2740 3687.5,2700 3590,2700 3525,2635 3440,2635
POE4 on TOP "TOP-POE4" (solid, pour order 12): 95 vertices, not listed, extent 3535,2155 3715,2265
NETC40_2 on TOP "TOP-NETC40_2" (solid, pour order 18): 123 vertices, not listed, extent 3415,2285.02 3690,2475
NETC18_2 on TOP "TOP-NETC18_2" (solid, pour order 20): 17 vertices, not listed, extent 4350,2600 4570,2730
NETC72_2 on TOP "TOP-NETC72_2" (solid, pour order 26): 300 vertices, not listed, extent 2217,2198 2358,2426
5V on TOP "TOP-5V" (solid, pour order 32): 21 vertices, not listed, extent 4330,390 4955,510
5V_POE on TOP "TOP-5V_POE" (solid, pour order 36): 94 vertices, not listed, extent 4170,2735 4485,2875
NETC4_1 on L4_SIG "L4_SIG-NETC4_1" (solid, pour order 24): 4160,3325 4180,3345 4575,3345 4590,3330 4590,3135 4560,3105 4530,3105 4490,3145 4340,3145 4330,3135 4330,3025 4315,3010 4180,3010 4160,3030 4160,3325
POE7 on L2_GND (split plane): 154 vertices, not listed, extent 20.1,20.1 4979.9,3444.46
POE7 on L2_GND (split plane): 649.9,1305.1 639.36,1305.1 639.36,1347.29 606.7,1347.29 606.7,1305.1 605.1,1305.1 605.1,1349.9 649.9,1349.9
POE7 on L2_GND (split plane): 649.9,1225.1 637.66,1225.1 637.66,1268.99 605.1,1268.99 605.1,1269.9 649.9,1269.9
POE1 on L2_GND (split plane): 49 vertices, not listed, extent 3380.09,2125.09 4574.91,3444.46
3V3 on L3_VCC (split plane): 243 vertices, not listed, extent 20.1,20.1 4979.9,3444.46
3V3 on L3_VCC (split plane): 719.9,1225.1 707.66,1225.1 707.66,1268.99 675.1,1268.99 675.1,1269.9 719.9,1269.9
1V8 on L3_VCC (split plane): 49 vertices, not listed, extent 620.09,1960.09 1244.91,2914.91
3V3_ST_LINK on L3_VCC (split plane): 29 vertices, not listed, extent 3420.09,20.1 4564.91,949.91
5V on L3_VCC (split plane): 45 vertices, not listed, extent 3110.09,20.1 4979.9,1909.91
3V3 on L3_VCC (split plane): 719.9,1305.1 709.36,1305.1 709.36,1347.29 676.7,1347.29 676.7,1305.1 675.1,1305.1 675.1,1349.9 719.9,1349.9
VDD on L3_VCC (split plane): 40 vertices, not listed, extent 1630.09,1610.09 3089.91,2559.91
POE7 on L5_GND (split plane): 154 vertices, not listed, extent 20.1,20.1 4979.9,3444.46
POE7 on L5_GND (split plane): 859.9,1348.99 827.34,1348.99 827.34,1305.1 815.1,1305.1 815.1,1349.9 859.9,1349.9
POE7 on L5_GND (split plane): 859.9,1225.1 855,1225.1 855,1268.99 822.34,1268.99 822.34,1225.1 815.1,1225.1 815.1,1269.9 859.9,1269.9
POE1 on L5_GND (split plane): 49 vertices, not listed, extent 3380.09,2125.09 4574.91,3444.46

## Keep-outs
TOP:
  circle w1: c4655,3080 r65
  circle w1: c4655,3080 r60
  circle w1: c440,390 r65
  circle w1: c440,390 r60
  circle w1: c395,3055 r60
  circle w1: c395,3055 r65
  circle w1: c4655,3080 r65
  circle w1: c4655,3080 r60
  circle w1: c440,390 r65
  circle w1: c440,390 r60
  circle w1: c395,3055 r60
  circle w1: c395,3055 r65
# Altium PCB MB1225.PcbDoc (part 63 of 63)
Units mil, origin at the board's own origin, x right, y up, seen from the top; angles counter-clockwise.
Board outline 5000 x 3464.56 mil, 6 copper layers (TOP, L2_GND, L3_VCC, L4_SIG, L5_GND, BOTTOM), stack 62.2 mil thick; 452 components, 378 nets, 1968 pads, 949 vias.

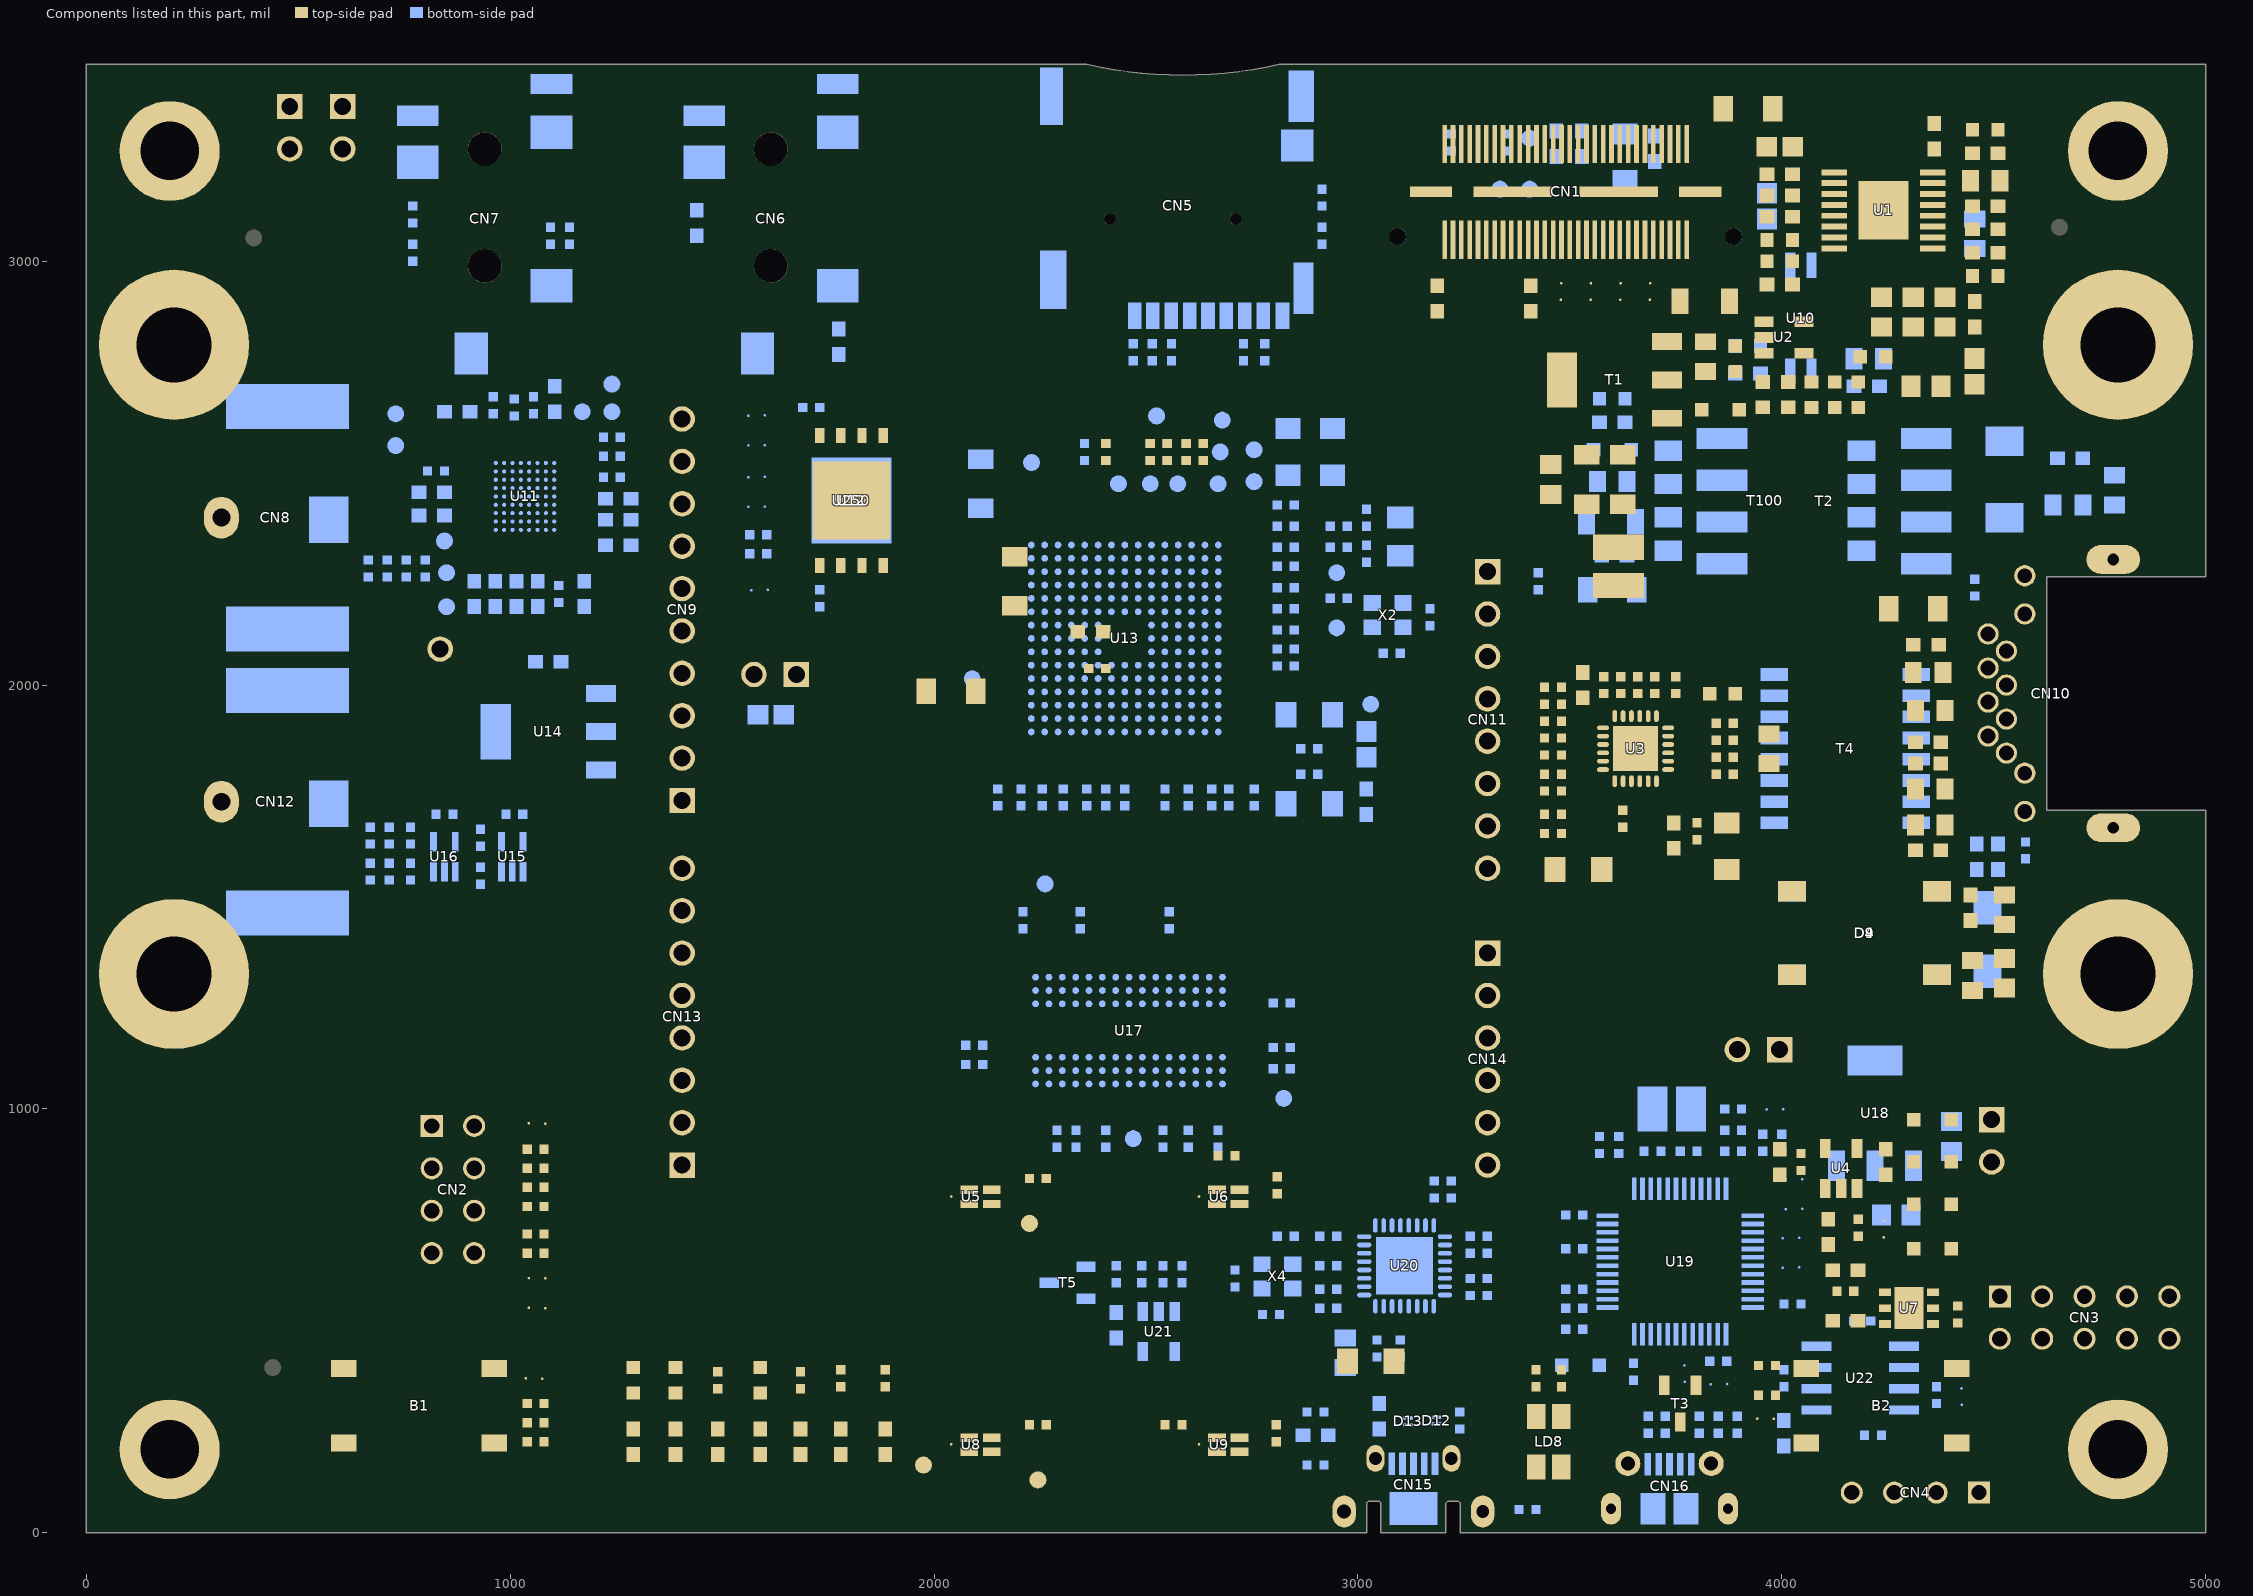
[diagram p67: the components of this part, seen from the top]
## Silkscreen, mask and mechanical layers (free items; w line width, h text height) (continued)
Drill Drawing:
  drawing of 1328 lines, arcs and shapes, not listed
  text "5" at 689,9177 h100
  text "IMPEDANCE TABLE" at 910,9140 h100
  text "IMPEDANCE TABLE" at 910,9140 h100
  text "LAYER" at 835,8846 h75
  text "LAYER" at 835,8846 h75
  text "TOLERANCE" at 4585,8846 h75
  text "TOLERANCE" at 4585,8846 h75
  text "TRACE" at 1585,8836 h75
  text "TRACE" at 1585,8836 h75
  text "SPACEING" at 2135,8836 h75
  text "SPACEING" at 2135,8836 h75
  text "IMPEDANCE" at 2885,8836 h75
  text "IMPEDANCE" at 2885,8836 h75
  text "IMPEDANCE" at 3785,8836 h75
  text "IMPEDANCE" at 3785,8836 h75
  text "(mil)" at 1635,8746 h50
  text "(mil)" at 1635,8746 h50
  text "(Single end)" at 2935,8746 h50
  text "(Single end)" at 2935,8746 h50
  text "(mil)" at 2235,8736 h50
  text "(mil)" at 2235,8736 h50
  text "(Differential)" at 3785,8736 h50
  text "(Differential)" at 3785,8736 h50
  text "4" at 6920,8610 h75
  text "4" at 6920,8610 h75
  text "LAYER STUCK-UP" at 7120,8610 h75
  text "LAYER STUCK-UP" at 7120,8610 h75
  text "1,6" at 830,8600 h75
  text "1,6" at 830,8600 h75
  text "5.0" at 1630,8590 h75
  text "5.0" at 1630,8590 h75
  text "N/A" at 2285,8536 h75
  text "N/A" at 2285,8536 h75
  text "55 OHM" at 2935,8526 h75
  text "55 OHM" at 2935,8526 h75
  text "N/A" at 3935,8526 h75
  text "N/A" at 3935,8526 h75
  text "+/-10%" at 4685,8526 h75
  text "+/-10%" at 4685,8526 h75
  text "4.0" at 1620,8470 h75
  text "4.0" at 1620,8470 h75
  text "4" at 830,8460 h75
  text "4" at 830,8460 h75
  text "SOLDERMASK & SILKSCREEN" at 8880,8370 h60
  text "SOLDERMASK & SILKSCREEN" at 8880,8370 h60
  text "N/A" at 3040,8290 h75
  text "5.1" at 1615,8285 h75
  text "9.9" at 2265,8285 h75
  text "100 OHM" at 3850,8280 h75
  text "+/-10%" at 4685,8276 h75
  text "+/-10%" at 4685,8276 h75
  text "1,6" at 830,8275 h75
  text "TOP     (0.5 oz cu+planted)" at 8880,8250 h60
  text "TOP     (0.5 oz cu+planted)" at 8880,8250 h60
  text "PREPREG  3.9 mil" at 7560,8085 h60
  text "PREPREG  3.9 mil" at 7560,8085 h60
  text "90 OHM" at 3844,8034 h75
  text "+/-10%" at 4691,8032 h75
  text "6.1" at 1610,8025 h75
  text "8.9" at 2260,8020 h75
  text "N/A" at 3045,8011 h75
  text "1,6" at 835,8005 h75
  text "LAYER 2 (1 oz)" at 8880,7950 h60
  text "LAYER 2 (1 oz)" at 8880,7950 h60
  text "CORE     4  mil" at 7560,7850 h60
  text "CORE     4  mil" at 7560,7850 h60
  text "LAYER 3 (1 oz)" at 8880,7750 h60
  text "LAYER 3 (1 oz)" at 8880,7750 h60
  text "1.2 mm" at 6688,7677.5 h75
  text "1.2 mm" at 6688,7677.5 h75
  text "PREPREG  ** mil" at 7560,7585 h60
  text "PREPREG  ** mil" at 7560,7585 h60
  text "+/-10%" at 6730,7570 h50
  text "+/-10%" at 6730,7570 h50
  text "LAYER 4 (1 oz)" at 8880,7450 h60
  text "LAYER 4 (1 oz)" at 8880,7450 h60
  text "CORE     4  mil" at 7560,7350 h60
  text "CORE     4  mil" at 7560,7350 h60
  text "LAYER 5 (1 oz)" at 8880,7250 h60
  text "LAYER 5 (1 oz)" at 8880,7250 h60
  text "PREPREG  3.9 mil" at 7560,7085 h60
  text "PREPREG  3.9 mil" at 7560,7085 h60
  text "BOTTOM  (0.5 oz cu+planted)" at 8880,6950 h60
  text "BOTTOM  (0.5 oz cu+planted)" at 8880,6950 h60
  text "SOLDERMASK & SILKSCREEN" at 8880,6830 h60
  text "SOLDERMASK & SILKSCREEN" at 8880,6830 h60
  text "6 LAYER STACKING" at 7500,6650 h75
  text "6 LAYER STACKING" at 7500,6650 h75
  text "PCB SPECIFICATIONS:" at 10537,5421 h85
  text "PCB SPECIFICATIONS:" at 10537,5421 h85
  text "A. MATERIAL;" at 10537,5221 h85
  text "A. MATERIAL;" at 10537,5221 h85
  text "FR-4," at 12287,5221 h85
  text "FR-4," at 12287,5221 h85
  text "TG-170" at 13237,5221 h85
  text "TG-170" at 13237,5221 h85
  text "TG-150" at 13987,5221 h85
  text "TG-150" at 13987,5221 h85
  text "TG-140" at 14837,5221 h85
  text "TG-140" at 14837,5221 h85
  text "B. MATERIAL FAMILY;" at 10537,5021 h85
  text "B. MATERIAL FAMILY;" at 10537,5021 h85
  text "N/A." at 12287,5021 h85
  text "N/A." at 12287,5021 h85
  text "C. SOLDERMASK COLOR;" at 10537,4821 h85
  text "C. SOLDERMASK COLOR;" at 10537,4821 h85
  text "GREEN" at 12437,4821 h85
  text "GREEN" at 12437,4821 h85
  text "BLUE" at 13187,4821 h85
  text "BLUE" at 13187,4821 h85
  text "RED" at 14037,4821 h85
  text "RED" at 14037,4821 h85
  text "BLACK" at 14887,4821 h85
  text "BLACK" at 14887,4821 h85
  text "D. SILKSCREEN COLOR;" at 10537,4621 h85
  text "D. SILKSCREEN COLOR;" at 10537,4621 h85
  text "WHITE" at 12437,4621 h85
  text "WHITE" at 12437,4621 h85
  text "YELLOW" at 13187,4621 h85
  text "YELLOW" at 13187,4621 h85
  text "BLACK" at 14037,4621 h85
  text "BLACK" at 14037,4621 h85
  text "E. SURFACE FINISH;" at 10537,4421 h85
  text "E. SURFACE FINISH;" at 10537,4421 h85
  text "ENIG" at 12437,4421 h85
  text "ENIG" at 12437,4421 h85
  text "IMMERSION SILVER" at 13187,4421 h85
  text "IMMERSION SILVER" at 13187,4421 h85
  text "IMMERSION TIN" at 14887,4421 h85
  text "IMMERSION TIN" at 14887,4421 h85
  text "HASL" at 12437,4221 h85
  text "HASL" at 12437,4221 h85
  text "HASL(PB-FREE)" at 13187,4221 h85
  text "HASL(PB-FREE)" at 13187,4221 h85
  text "GOLDEN FINGER" at 14887,4221 h85
  text "GOLDEN FINGER" at 14887,4221 h85
  text "F. IMPEDANCE CONTROL;" at 10537,4021 h85
  text "F. IMPEDANCE CONTROL;" at 10537,4021 h85
  text "NO" at 12437,4021 h85
  text "NO" at 12437,4021 h85
  text "YES" at 13187,4021 h85
  text "YES" at 13187,4021 h85
  text "(SEE IMPEDANCE TABLE FOR DETAIL INFORMATION)" at 13387,4021 h85
  text "(SEE IMPEDANCE TABLE FOR DETAIL INFORMATION)" at 13387,4021 h85
  text "G. THROUGH VIA;" at 10537,3821 h85
  text "G. THROUGH VIA;" at 10537,3821 h85
  text "PLUG THE VIAS WHICH ARE COVERED WITH SOLDERMASK ONE OR TWO SIDE." at 11987,3821 h85
  text "PLUG THE VIAS WHICH ARE COVERED WITH SOLDERMASK ONE OR TWO SIDE." at 11987,3821 h85
  text "PLUG MATERIAL:" at 11987,3621 h85
  text "PLUG MATERIAL:" at 11987,3621 h85
  text "SOLDERMASK" at 13587,3621 h85
  text "SOLDERMASK" at 13587,3621 h85
  text "NON-CONDUCTIVE EPOXY." at 14887,3621 h85
  text "NON-CONDUCTIVE EPOXY." at 14887,3621 h85
  text "H. STACK-UP;" at 10537,3421 h85
  text "H. STACK-UP;" at 10537,3421 h85
  text "SEE LAYER STACK-UP SEQUENCE FOR OVERALL THICKNESS." at 11987,3421 h85
  text "SEE LAYER STACK-UP SEQUENCE FOR OVERALL THICKNESS." at 11987,3421 h85
  text "Symbol" at 5689.18,3144.85 h120
  text "Hit Count" at 6159.33,3144.85 h120
  text "Finished Hole Size" at 6721.8,3144.85 h120
  text "Plated" at 7728.89,3144.85 h120
  text "Hole Length" at 8141.6,3144.85 h120
  text "Routed Path Length" at 8829.28,3144.85 h120
  text "PCB REQUIREMENTS:" at 10527,3121 h85
  text "PCB REQUIREMENTS:" at 10527,3121 h85
  text "27" at 6159.33,2937.88 h100
  text "0,15mm" at 6721.8,2937.88 h100
  text "PTH" at 7728.89,2937.88 h100
  text "-" at 8141.6,2937.88 h100
  text "-" at 8829.28,2937.88 h100
  text "D" at 5651.65,2927.89 h91.99
  text "1. THIS BOARD WILL CONFORM TO:" at 10477,2921 h85
  text "1. THIS BOARD WILL CONFORM TO:" at 10477,2921 h85
  text "IPC-A-600. CURRENT REV., CLASS II" at 10477,2771 h85
  text "IPC-A-600. CURRENT REV., CLASS II" at 10477,2771 h85
  text "219" at 6159.33,2730.91 h100
  text "0,20mm" at 6721.8,2730.91 h100
  text "PTH" at 7728.89,2730.91 h100
  text "-" at 8141.6,2730.91 h100
  text "-" at 8829.28,2730.91 h100
  text "C" at 5651.65,2720.93 h91.99
  text "IPC-6012, CURRENT REV., CLASS II" at 10477,2621 h85
  text "IPC-6012, CURRENT REV., CLASS II" at 10477,2621 h85
  text "354" at 6159.33,2523.94 h100
  text "0,25mm" at 6721.8,2523.94 h100
  text "PTH" at 7728.89,2523.94 h100
  text "-" at 8141.6,2523.94 h100
  text "-" at 8829.28,2523.94 h100
  text "A" at 5651.65,2513.96 h91.99
  text "2. UNLESS OTHERWISE SPECIFIED ALL HOLE DIMENSIONS APPLY AFTER PLATING." at 10477,2411 h85
  text "2. UNLESS OTHERWISE SPECIFIED ALL HOLE DIMENSIONS APPLY AFTER PLATING." at 10477,2411 h85
  text "349" at 6159.33,2316.97 h100
  text "0,31mm" at 6721.8,2316.97 h100
  text "PTH" at 7728.89,2316.97 h100
  text "-" at 8141.6,2316.97 h100
  text "-" at 8829.28,2316.97 h100
  text "B" at 5651.65,2306.99 h91.99
  text "ALL HOLES SHALL BE LOCATED WITHIN .003\" DIAMETER OF TRUE POSITION." at 10477,2261 h85
  text "ALL HOLES SHALL BE LOCATED WITHIN .003\" DIAMETER OF TRUE POSITION." at 10477,2261 h85
  text "2" at 6159.33,2110 h100
  text "0,61mm" at 6721.8,2110 h100
  text "PTH" at 7728.89,2110 h100
  text "1,30mm" at 8141.6,2110 h100
  text "0,69mm" at 8829.28,2110 h100
  text "3. PLATED HOLE WALL THICKNESS SHALL NOT BE LESS THAN .001 INCH MINIMUM" at 10477,2061 h85
  text "3. PLATED HOLE WALL THICKNESS SHALL NOT BE LESS THAN .001 INCH MINIMUM" at 10477,2061 h85
  text "AVERAGE, WITH NO READING LESS THAN .0008 BY COROSS SECTION." at 10657,1921 h85
  text "AVERAGE, WITH NO READING LESS THAN .0008 BY COROSS SECTION." at 10657,1921 h85
  text "2" at 6159.33,1903.04 h100
  text "0,71mm" at 6721.8,1903.04 h100
  text "PTH" at 7728.89,1903.04 h100
  text "-" at 8141.6,1903.04 h100
  text "-" at 8829.28,1903.04 h100
  text "4. MATERIAL FR4 RATING 94V-0 MINIMUM EPOXY GLASS LAMINATE." at 10477,1711 h85
  text "4. MATERIAL FR4 RATING 94V-0 MINIMUM EPOXY GLASS LAMINATE." at 10477,1711 h85
  text "2" at 6159.33,1696.07 h100
  text "0,71mm" at 6721.8,1696.07 h100
  text "PTH" at 7728.89,1696.07 h100
  text "2,21mm" at 8141.6,1696.07 h100
  text "1,50mm" at 8829.28,1696.07 h100
  text "5. BOARD SHALL BE LPI SOLDER MASKED OVER BARE COPPER BOTH SIDES PER" at 10477,1531 h85
  text "5. BOARD SHALL BE LPI SOLDER MASKED OVER BARE COPPER BOTH SIDES PER" at 10477,1531 h85
  text "2" at 6159.33,1489.1 h100
  text "0,76mm" at 6721.8,1489.1 h100
  text "PTH" at 7728.89,1489.1 h100
  text "0,84mm" at 8141.6,1489.1 h100
  text "0,08mm" at 8829.28,1489.1 h100
  text "IPC-SM-840 CLASS II." at 10477,1381 h85
  text "IPC-SM-840 CLASS II." at 10477,1381 h85
  text "1" at 6159.33,1282.13 h100
  text "0,76mm" at 6721.8,1282.13 h100
  text "PTH" at 7728.89,1282.13 h100
  text "1,50mm" at 8141.6,1282.13 h100
  text "0,74mm" at 8829.28,1282.13 h100
  text "6. SILKSCREEN SHALL BE PERMANENT NON-CONDUCTIVE INK AND WITH NO OVERLAP" at 10477,1181 h85
  text "6. SILKSCREEN SHALL BE PERMANENT NON-CONDUCTIVE INK AND WITH NO OVERLAP" at 10477,1181 h85
  text "2" at 6159.33,1075.16 h100
  text "0,84mm" at 6721.8,1075.16 h100
  text "PTH" at 7728.89,1075.16 h100
  text "-" at 8141.6,1075.16 h100
  text "-" at 8829.28,1075.16 h100
  text "ON ANY COMPONENT PAD OR THROUGH HOLE." at 10477,1031 h85
  text "ON ANY COMPONENT PAD OR THROUGH HOLE." at 10477,1031 h85
  text "1" at 6159.33,868.19 h100
  text "0,84mm" at 6721.8,868.19 h100
  text "PTH" at 7728.89,868.19 h100
  text "1,50mm" at 8141.6,868.19 h100
  text "0,66mm" at 8829.28,868.19 h100
  text "E" at 5651.65,858.21 h91.99
  text "7. MFGR, TO LEGIBLY ETCH OR STAMP/SCREEN WITH PERMANENT NON-CONDUCTIVE INK" at 10477,831 h85
  text "7. MFGR, TO LEGIBLY ETCH OR STAMP/SCREEN WITH PERMANENT NON-CONDUCTIVE INK" at 10477,831 h85
  text "D. MFGR. LOGO" at 12327,701 h85
  text "D. MFGR. LOGO" at 12327,701 h85
  text "A. U.L. CODE" at 10767,681 h85
  text "A. U.L. CODE" at 10767,681 h85
  text "12" at 6159.33,661.22 h100
  text "0,89mm" at 6721.8,661.22 h100
  text "PTH" at 7728.89,661.22 h100
  text "-" at 8141.6,661.22 h100
  text "-" at 8829.28,661.22 h100
  text "E. SUCCESSFUL ELECTRICAL BOARD TEST." at 12327,561 h85
  text "E. SUCCESSFUL ELECTRICAL BOARD TEST." at 12327,561 h85
  text "B. DATE CODE" at 10767,541 h85
  text "B. DATE CODE" at 10767,541 h85
  text "22" at 6159.33,454.26 h100
  text "0,91mm" at 6721.8,454.26 h100
  text "PTH" at 7728.89,454.26 h100
  text "-" at 8141.6,454.26 h100
  text "-" at 8829.28,454.26 h100
  text "C. FLAMMABILITY RATING" at 10767,401 h85
  text "C. FLAMMABILITY RATING" at 10767,401 h85
  text "45" at 6159.33,247.29 h100
  text "1,02mm" at 6721.8,247.29 h100
  text "PTH" at 7728.89,247.29 h100
  text "-" at 8141.6,247.29 h100
  text "-" at 8829.28,247.29 h100
  text "8. REMOVE THE FLASHS WHICH SMALLER THAN HOLE SIZE." at 10477,191 h85
  text "8. REMOVE THE FLASHS WHICH SMALLER THAN HOLE SIZE." at 10477,191 h85
  text "2" at 6159.33,40.32 h100
  text "1,07mm" at 6721.8,40.32 h100
  text "PTH" at 7728.89,40.32 h100
  text "1,47mm" at 8141.6,40.32 h100
  text "0,41mm" at 8829.28,40.32 h100
  text "9. REMOVE ALL SHAPE EDGES AND BURRS .005 MAXIMUM." at 10477,-9 h85
  text "9. REMOVE ALL SHAPE EDGES AND BURRS .005 MAXIMUM." at 10477,-9 h85
  text "4" at 6159.33,-166.65 h100
  text "2,01mm" at 6721.8,-166.65 h100
  text "PTH" at 7728.89,-166.65 h100
  text "-" at 8141.6,-166.65 h100
  text "-" at 8829.28,-166.65 h100
  text "10. PLEASE USE THE SUPPLIED IPC 356 NETLIST TO VERIFY BOARD BEFORE" at 10477,-219 h85
  text "10. PLEASE USE THE SUPPLIED IPC 356 NETLIST TO VERIFY BOARD BEFORE" at 10477,-219 h85
  text "FABRICATING BOARD." at 10477,-369 h85
  text "FABRICATING BOARD." at 10477,-369 h85
  text "4" at 6159.33,-373.62 h100
  text "3,51mm" at 6721.8,-373.62 h100
  text "PTH" at 7728.89,-373.62 h100
  text "-" at 8141.6,-373.62 h100
  text "-" at 8829.28,-373.62 h100
  text "4" at 6159.33,-580.59 h100
  text "4,50mm" at 6721.8,-580.59 h100
  text "PTH" at 7728.89,-580.59 h100
  text "-" at 8141.6,-580.59 h100
  text "-" at 8829.28,-580.59 h100
  text "1054 Total" at 6159.33,-787.56 h100
  text "Slot definitions :" at 5689.18,-932.44 h100
  text "Routed Path Length" at 6371.21,-932.44 h100
  text "= Calculated from tool start centre position to tool end centre position." at 7216.12,-932.44 h100
  text "Hole Length" at 6371.21,-1015.22 h100
  text "= Routed Path Length + Tool Size = Slot length as defined in the PCB layout" at 6902.46,-1015.22 h100
REVISION_BLOCK:
  lines w1: 13590,9610 13590,10860 13590,9610 ; 13590,9810 17740,9810 13590,9810 ; 13590,10010 17740,10010 13590,10010 ; 13590,10210 17740,10210 13590,10210 ; 13590,10410 17740,10410 13590,10410 ; 13590,10610 17740,10610 13590,10610 ; 13990,9610 13990,10610 13990,9610 ; 16190,9610 16190,10610 16190,9610 ; 16940,9610 16940,10610 16940,9610
TITLE_BLOCK:
  drawing of 24712 lines, arcs and shapes, not listed
  text "COMPANY NAME:" at 3735,-1740 h60
  text "COMPANY NAME:" at 3735,-1740 h60
  text "LAYER:" at 2135,-1790 h75
  text "LAYER:" at 2135,-1790 h75
  text "ST" at 3885,-1890 h75
  text "ST" at 3885,-1890 h75
  text "PROJECT NAME:" at 3735,-2040 h60
  text "PROJECT NAME:" at 3735,-2040 h60
  text "DESIGNED BY SOFER" at 865,-2060 h60
  text "DESIGNED BY SOFER" at 865,-2060 h60
  text "www.sofer.com.cn" at 885,-2160 h60
  text "www.sofer.com.cn" at 885,-2160 h60
  text "DESIGNER:" at 2185,-2190 h60
  text "DESIGNER:" at 2185,-2190 h60
  text "Shelley" at 2685,-2190 h60
  text "Shelley" at 2685,-2190 h60
  text "MB1225" at 3885,-2190 h75
  text "MB1225" at 3885,-2190 h75
  text "Tel : +86 21 - 6482 6908" at 685,-2340 h60
  text "Tel : +86 21 - 6482 6908" at 685,-2340 h60
  text "PROJECT NUMBER:" at 3735,-2340 h60
  text "PROJECT NUMBER:" at 3735,-2340 h60
  text "REV" at 4935,-2340 h60
  text "REV" at 4935,-2340 h60
  text "Mail: design@sofer.com.cn" at 685,-2440 h60
  text "Mail: design@sofer.com.cn" at 685,-2440 h60
  text "DATE:" at 2185,-2440 h60
  text "DATE:" at 2185,-2440 h60
  text "2016.02.18" at 2485,-2440 h60
  text "2016.02.18" at 2485,-2440 h60
  text "D031-019A2" at 3885,-2490 h75
  text "D031-019A2" at 3885,-2490 h75
  text "B" at 5035,-2490 h75
  text "B" at 5035,-2490 h75
REVISION_DATA:
  text "REVISIONS" at 15140,10710 h85
  text "REVISIONS" at 15140,10710 h85
  text "REV" at 13690,10460 h75
  text "REV" at 13690,10460 h75
  text "DESCRIPTION" at 14240,10460 h75
  text "DESCRIPTION" at 14240,10460 h75
  text "DATE" at 16390,10460 h75
  text "DATE" at 16390,10460 h75
  text "APPROVED" at 17090,10460 h75
  text "APPROVED" at 17090,10460 h75
  text "1.0" at 13690,10260 h75
  text "1.0" at 13690,10260 h75
  text "EDITION ORIGINALE" at 14240,10260 h75
  text "EDITION ORIGINALE" at 14240,10260 h75
  text "2008-**-**" at 16240,10260 h75
  text "2008-**-**" at 16240,10260 h75
  text "***" at 17250,10260 h75
  text "***" at 17250,10260 h75
TITLE_DATA:
  text "UNLESS OTHERWISE SPECIFIED" at 10590,-3440 h75
  text "UNLESS OTHERWISE SPECIFIED" at 10590,-3440 h75
  text "SIGNATURES" at 12490,-3490 h75
  text "SIGNATURES" at 12490,-3490 h75
  text "DATE" at 13890,-3490 h75
  text "DATE" at 13890,-3490 h75
  text "LOGO" at 14590,-3640 h130
  text "LOGO" at 14590,-3640 h130
  text "COMPANY NAME" at 16090,-3640 h130
  text "COMPANY NAME" at 16090,-3640 h130
  text "DRAWN" at 12490,-3690 h75
  text "DRAWN" at 12490,-3690 h75
  text "YY-MM-DD" at 13790,-3690 h75
  text "YY-MM-DD" at 13790,-3690 h75
  text "DIMENSIONS ARE IN INCHES" at 10640,-3740 h75
  text "DIMENSIONS ARE IN INCHES" at 10640,-3740 h75
  text "TOLERANCES ON;" at 10640,-3890 h75
  text "TOLERANCES ON;" at 10640,-3890 h75
  text "CHECKED" at 12490,-3890 h75
  text "CHECKED" at 12490,-3890 h75
  text "YY-MM-DD" at 13790,-3890 h75
  text "YY-MM-DD" at 13790,-3890 h75
  text "2 PL DECIMALS +" at 10640,-4040 h75
  text "2 PL DECIMALS +" at 10640,-4040 h75
  text "TITLE" at 14490,-4040 h100
  text "TITLE" at 14490,-4040 h100
  text "ENGRG" at 12490,-4090 h75
  text "ENGRG" at 12490,-4090 h75
  text "YY-MM-DD" at 13790,-4090 h75
  text "YY-MM-DD" at 13790,-4090 h75
  text "PROJECT NAME *" at 15240,-4140 h130
  text "PROJECT NAME *" at 15240,-4140 h130
  text "3 PL DECIMALS +" at 10640,-4190 h75
  text "3 PL DECIMALS +" at 10640,-4190 h75
  text "ISSUED" at 12490,-4290 h75
  text "ISSUED" at 12490,-4290 h75
  text "ANGLES +" at 10640,-4340 h75
  text "ANGLES +" at 10640,-4340 h75
  text "SIZE" at 14515,-4415 h75
  text "SIZE" at 14515,-4415 h75
  text "B" at 14915,-4415 h75
  text "B" at 14915,-4415 h75
  text "DWG NO" at 15265,-4415 h75
  text "DWG NO" at 15265,-4415 h75
  text "*********" at 15865,-4415 h75
  text "*********" at 15865,-4415 h75
  text "REV" at 17165,-4415 h75
  text "REV" at 17165,-4415 h75
  text "**" at 17465,-4415 h75
  text "**" at 17465,-4415 h75
  text "FRACTIONS +" at 10640,-4490 h75
  text "FRACTIONS +" at 10640,-4490 h75
  text "SCALE" at 14515,-4665 h75
  text "SCALE" at 14515,-4665 h75
  text "1:1" at 14915,-4665 h75
  text "1:1" at 14915,-4665 h75
  text "SHEET" at 16515,-4665 h75
  text "SHEET" at 16515,-4665 h75
  text "1 OF 1" at 17115,-4665 h75
  text "1 OF 1" at 17115,-4665 h75
LAY6:
  the board outline again, w6
DFA_BOUND_BOTTOM:
  circle w1: c0,0 r100
  circle w1: c0,0 r100
  lines w1: -150,0 150,0 -150,0 ; 0,-150 0,150 0,-150
  text "/XX" at 2635,-1790 h75
  text "14" at 2635,-1790 h75
  text "16" at 2635,-1790 h75
  text "/XX" at 2635,-1790 h75
  text "14" at 2635,-1790 h75
  text "16" at 2635,-1790 h75
  text "LAYER 14(INTERNAL SIGNAL)" at 2185,-1940 h60
  text "LAYER 16(INTERNAL SIGNAL)" at 2185,-1940 h60
  text "ASSEMBLY (PRIMARY)" at 2185,-1940 h60
  text "MUTI-PACK DRAWING" at 2185,-1940 h60
  text "LAYER 14(INTERNAL SIGNAL)" at 2185,-1940 h60
  text "LAYER 16(INTERNAL SIGNAL)" at 2185,-1940 h60
  text "ASSEMBLY (PRIMARY)" at 2185,-1940 h60
  text "MUTI-PACK DRAWING" at 2185,-1940 h60
  text "ASSEMBLY (SECONDARY)" at 3289,-1951 h60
